VERSION 5.8 ;
BUSBITCHARS "[]" ;
DIVIDERCHAR "/" ;
UNITS
    DATABASE MICRONS 1000 ;
END UNITS

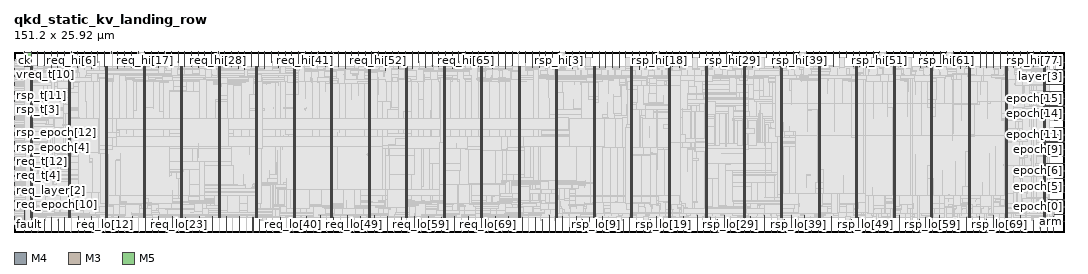
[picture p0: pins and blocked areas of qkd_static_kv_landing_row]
MACRO qkd_static_kv_landing_row
  FOREIGN qkd_static_kv_landing_row 0 0 ;
  CLASS BLOCK ;
  SIZE 151.2 BY 25.92 ;
  PIN arm
    DIRECTION INPUT ;
    USE SIGNAL ;
    PORT
      LAYER M4 ;
        RECT  151.116 1.488 151.2 1.512 ;
    END
    PORT
      LAYER M4 ;
        RECT  149.857 1.488 151.164 1.512 ;
    END
  END arm
  PIN ck
    DIRECTION INPUT ;
    USE SIGNAL ;
    PORT
      LAYER M3 ;
        RECT  1.476 25.882 1.494 25.92 ;
    END
    PORT
      LAYER M3 ;
        RECT  1.476 25.819 1.494 25.901 ;
    END
  END ck
  PIN epoch[0]
    DIRECTION INPUT ;
    USE SIGNAL ;
    PORT
      LAYER M4 ;
        RECT  151.116 2.544 151.2 2.568 ;
    END
    PORT
      LAYER M4 ;
        RECT  149.857 2.544 151.164 2.568 ;
    END
  END epoch[0]
  PIN epoch[10]
    DIRECTION INPUT ;
    USE SIGNAL ;
    PORT
      LAYER M4 ;
        RECT  151.116 12.96 151.2 12.984 ;
    END
    PORT
      LAYER M4 ;
        RECT  148.504 12.96 151.164 12.984 ;
    END
  END epoch[10]
  PIN epoch[11]
    DIRECTION INPUT ;
    USE SIGNAL ;
    PORT
      LAYER M4 ;
        RECT  151.116 13.968 151.2 13.992 ;
    END
    PORT
      LAYER M4 ;
        RECT  149.857 13.968 151.164 13.992 ;
    END
  END epoch[11]
  PIN epoch[12]
    DIRECTION INPUT ;
    USE SIGNAL ;
    PORT
      LAYER M4 ;
        RECT  151.116 15.024 151.2 15.048 ;
    END
    PORT
      LAYER M4 ;
        RECT  149.857 15.024 151.164 15.048 ;
    END
  END epoch[12]
  PIN epoch[13]
    DIRECTION INPUT ;
    USE SIGNAL ;
    PORT
      LAYER M4 ;
        RECT  151.116 16.08 151.2 16.104 ;
    END
    PORT
      LAYER M4 ;
        RECT  149.857 16.08 151.164 16.104 ;
    END
  END epoch[13]
  PIN epoch[14]
    DIRECTION INPUT ;
    USE SIGNAL ;
    PORT
      LAYER M4 ;
        RECT  151.116 17.088 151.2 17.112 ;
    END
    PORT
      LAYER M4 ;
        RECT  149.857 17.088 151.164 17.112 ;
    END
  END epoch[14]
  PIN epoch[15]
    DIRECTION INPUT ;
    USE SIGNAL ;
    PORT
      LAYER M4 ;
        RECT  151.116 18.144 151.2 18.168 ;
    END
    PORT
      LAYER M4 ;
        RECT  148.504 18.144 151.164 18.168 ;
    END
  END epoch[15]
  PIN epoch[1]
    DIRECTION INPUT ;
    USE SIGNAL ;
    PORT
      LAYER M4 ;
        RECT  151.116 3.6 151.2 3.624 ;
    END
    PORT
      LAYER M4 ;
        RECT  149.533 3.6 151.164 3.624 ;
    END
  END epoch[1]
  PIN epoch[2]
    DIRECTION INPUT ;
    USE SIGNAL ;
    PORT
      LAYER M4 ;
        RECT  151.116 4.608 151.2 4.632 ;
    END
    PORT
      LAYER M4 ;
        RECT  148.925 4.608 151.164 4.632 ;
    END
  END epoch[2]
  PIN epoch[3]
    DIRECTION INPUT ;
    USE SIGNAL ;
    PORT
      LAYER M4 ;
        RECT  151.116 5.664 151.2 5.688 ;
    END
    PORT
      LAYER M4 ;
        RECT  149.497 5.664 151.164 5.688 ;
    END
  END epoch[3]
  PIN epoch[4]
    DIRECTION INPUT ;
    USE SIGNAL ;
    PORT
      LAYER M4 ;
        RECT  151.116 6.72 151.2 6.744 ;
    END
    PORT
      LAYER M4 ;
        RECT  148.817 6.72 151.164 6.744 ;
    END
  END epoch[4]
  PIN epoch[5]
    DIRECTION INPUT ;
    USE SIGNAL ;
    PORT
      LAYER M4 ;
        RECT  151.116 7.728 151.2 7.752 ;
    END
    PORT
      LAYER M4 ;
        RECT  149.857 7.728 151.164 7.752 ;
    END
  END epoch[5]
  PIN epoch[6]
    DIRECTION INPUT ;
    USE SIGNAL ;
    PORT
      LAYER M4 ;
        RECT  151.116 8.784 151.2 8.808 ;
    END
    PORT
      LAYER M4 ;
        RECT  149.857 8.784 151.164 8.808 ;
    END
  END epoch[6]
  PIN epoch[7]
    DIRECTION INPUT ;
    USE SIGNAL ;
    PORT
      LAYER M4 ;
        RECT  151.116 9.84 151.2 9.864 ;
    END
    PORT
      LAYER M4 ;
        RECT  148.504 9.84 151.164 9.864 ;
    END
  END epoch[7]
  PIN epoch[8]
    DIRECTION INPUT ;
    USE SIGNAL ;
    PORT
      LAYER M4 ;
        RECT  151.116 10.848 151.2 10.872 ;
    END
    PORT
      LAYER M4 ;
        RECT  148.504 10.848 151.164 10.872 ;
    END
  END epoch[8]
  PIN epoch[9]
    DIRECTION INPUT ;
    USE SIGNAL ;
    PORT
      LAYER M4 ;
        RECT  151.116 11.904 151.2 11.928 ;
    END
    PORT
      LAYER M4 ;
        RECT  149.857 11.904 151.164 11.928 ;
    END
  END epoch[9]
  PIN fault
    DIRECTION OUTPUT ;
    USE SIGNAL ;
    PORT
      LAYER M4 ;
        RECT  0 1.104 0.084 1.128 ;
    END
  END fault
  PIN layer[0]
    DIRECTION INPUT ;
    USE SIGNAL ;
    PORT
      LAYER M4 ;
        RECT  151.116 19.2 151.2 19.224 ;
    END
    PORT
      LAYER M4 ;
        RECT  148.504 19.2 151.164 19.224 ;
    END
  END layer[0]
  PIN layer[1]
    DIRECTION INPUT ;
    USE SIGNAL ;
    PORT
      LAYER M4 ;
        RECT  151.116 20.208 151.2 20.232 ;
    END
    PORT
      LAYER M4 ;
        RECT  148.504 20.208 151.164 20.232 ;
    END
  END layer[1]
  PIN layer[2]
    DIRECTION INPUT ;
    USE SIGNAL ;
    PORT
      LAYER M4 ;
        RECT  151.116 21.264 151.2 21.288 ;
    END
    PORT
      LAYER M4 ;
        RECT  148.504 21.264 151.164 21.288 ;
    END
  END layer[2]
  PIN layer[3]
    DIRECTION INPUT ;
    USE SIGNAL ;
    PORT
      LAYER M4 ;
        RECT  151.116 22.32 151.2 22.344 ;
    END
    PORT
      LAYER M4 ;
        RECT  149.893 22.32 151.164 22.344 ;
    END
  END layer[3]
  PIN layer[4]
    DIRECTION INPUT ;
    USE SIGNAL ;
    PORT
      LAYER M4 ;
        RECT  151.116 23.328 151.2 23.352 ;
    END
    PORT
      LAYER M4 ;
        RECT  149.857 23.328 151.164 23.352 ;
    END
  END layer[4]
  PIN layer[5]
    DIRECTION INPUT ;
    USE SIGNAL ;
    PORT
      LAYER M4 ;
        RECT  151.116 24.384 151.2 24.408 ;
    END
    PORT
      LAYER M4 ;
        RECT  149.893 24.384 151.164 24.408 ;
    END
  END layer[5]
  PIN req_epoch[0]
    DIRECTION INPUT ;
    USE SIGNAL ;
    PORT
      LAYER M4 ;
        RECT  0 1.392 0.084 1.416 ;
    END
  END req_epoch[0]
  PIN req_epoch[10]
    DIRECTION INPUT ;
    USE SIGNAL ;
    PORT
      LAYER M4 ;
        RECT  0 3.936 0.084 3.96 ;
    END
  END req_epoch[10]
  PIN req_epoch[11]
    DIRECTION INPUT ;
    USE SIGNAL ;
    PORT
      LAYER M4 ;
        RECT  0 4.224 0.084 4.248 ;
    END
  END req_epoch[11]
  PIN req_epoch[12]
    DIRECTION INPUT ;
    USE SIGNAL ;
    PORT
      LAYER M4 ;
        RECT  0 4.464 0.084 4.488 ;
    END
  END req_epoch[12]
  PIN req_epoch[13]
    DIRECTION INPUT ;
    USE SIGNAL ;
    PORT
      LAYER M4 ;
        RECT  0 4.704 0.084 4.728 ;
    END
  END req_epoch[13]
  PIN req_epoch[14]
    DIRECTION INPUT ;
    USE SIGNAL ;
    PORT
      LAYER M4 ;
        RECT  0 4.992 0.084 5.016 ;
    END
  END req_epoch[14]
  PIN req_epoch[15]
    DIRECTION INPUT ;
    USE SIGNAL ;
    PORT
      LAYER M4 ;
        RECT  0 5.232 0.084 5.256 ;
    END
  END req_epoch[15]
  PIN req_epoch[1]
    DIRECTION INPUT ;
    USE SIGNAL ;
    PORT
      LAYER M4 ;
        RECT  0 1.632 0.084 1.656 ;
    END
  END req_epoch[1]
  PIN req_epoch[2]
    DIRECTION INPUT ;
    USE SIGNAL ;
    PORT
      LAYER M4 ;
        RECT  0 1.872 0.084 1.896 ;
    END
  END req_epoch[2]
  PIN req_epoch[3]
    DIRECTION INPUT ;
    USE SIGNAL ;
    PORT
      LAYER M4 ;
        RECT  0 2.16 0.084 2.184 ;
    END
  END req_epoch[3]
  PIN req_epoch[4]
    DIRECTION INPUT ;
    USE SIGNAL ;
    PORT
      LAYER M4 ;
        RECT  0 2.4 0.084 2.424 ;
    END
  END req_epoch[4]
  PIN req_epoch[5]
    DIRECTION INPUT ;
    USE SIGNAL ;
    PORT
      LAYER M4 ;
        RECT  0 2.64 0.084 2.664 ;
    END
  END req_epoch[5]
  PIN req_epoch[6]
    DIRECTION INPUT ;
    USE SIGNAL ;
    PORT
      LAYER M4 ;
        RECT  0 2.928 0.084 2.952 ;
    END
  END req_epoch[6]
  PIN req_epoch[7]
    DIRECTION INPUT ;
    USE SIGNAL ;
    PORT
      LAYER M4 ;
        RECT  0 3.168 0.084 3.192 ;
    END
  END req_epoch[7]
  PIN req_epoch[8]
    DIRECTION INPUT ;
    USE SIGNAL ;
    PORT
      LAYER M4 ;
        RECT  0 3.408 0.084 3.432 ;
    END
  END req_epoch[8]
  PIN req_epoch[9]
    DIRECTION INPUT ;
    USE SIGNAL ;
    PORT
      LAYER M4 ;
        RECT  0 3.696 0.084 3.72 ;
    END
  END req_epoch[9]
  PIN req_hi[0]
    DIRECTION OUTPUT ;
    USE SIGNAL ;
    PORT
      LAYER M5 ;
        RECT  2.448 25.836 2.472 25.92 ;
    END
    PORT
      LAYER M5 ;
        RECT  1.488 23.783 2.472 25.859 ;
    END
    PORT
      LAYER M5 ;
        RECT  2.448 25.859 2.472 25.872 ;
    END
  END req_hi[0]
  PIN req_hi[10]
    DIRECTION OUTPUT ;
    USE SIGNAL ;
    PORT
      LAYER M5 ;
        RECT  12.048 25.836 12.072 25.92 ;
    END
    PORT
      LAYER M5 ;
        RECT  12.048 24.469 12.072 25.872 ;
    END
  END req_hi[10]
  PIN req_hi[11]
    DIRECTION OUTPUT ;
    USE SIGNAL ;
    PORT
      LAYER M3 ;
        RECT  13.032 25.882 13.05 25.92 ;
    END
    PORT
      LAYER M3 ;
        RECT  13.032 23.777 13.05 25.901 ;
    END
  END req_hi[11]
  PIN req_hi[12]
    DIRECTION OUTPUT ;
    USE SIGNAL ;
    PORT
      LAYER M5 ;
        RECT  13.968 25.836 13.992 25.92 ;
    END
    PORT
      LAYER M5 ;
        RECT  13.968 25.765 13.992 25.872 ;
    END
  END req_hi[12]
  PIN req_hi[13]
    DIRECTION OUTPUT ;
    USE SIGNAL ;
    PORT
      LAYER M3 ;
        RECT  14.94 25.882 14.958 25.92 ;
    END
    PORT
      LAYER M3 ;
        RECT  14.94 23.585 14.958 25.901 ;
    END
  END req_hi[13]
  PIN req_hi[14]
    DIRECTION OUTPUT ;
    USE SIGNAL ;
    PORT
      LAYER M5 ;
        RECT  15.888 25.836 15.912 25.92 ;
    END
    PORT
      LAYER M5 ;
        RECT  15.888 23.893 15.912 25.872 ;
    END
  END req_hi[14]
  PIN req_hi[15]
    DIRECTION OUTPUT ;
    USE SIGNAL ;
    PORT
      LAYER M3 ;
        RECT  16.884 25.882 16.902 25.92 ;
    END
    PORT
      LAYER M3 ;
        RECT  16.884 23.729 16.902 25.901 ;
    END
  END req_hi[15]
  PIN req_hi[16]
    DIRECTION OUTPUT ;
    USE SIGNAL ;
    PORT
      LAYER M5 ;
        RECT  17.856 25.836 17.88 25.92 ;
    END
    PORT
      LAYER M5 ;
        RECT  17.856 25.765 17.88 25.872 ;
    END
  END req_hi[16]
  PIN req_hi[17]
    DIRECTION OUTPUT ;
    USE SIGNAL ;
    PORT
      LAYER M3 ;
        RECT  18.792 25.882 18.81 25.92 ;
    END
    PORT
      LAYER M3 ;
        RECT  18.792 25.805 18.81 25.901 ;
    END
  END req_hi[17]
  PIN req_hi[18]
    DIRECTION OUTPUT ;
    USE SIGNAL ;
    PORT
      LAYER M5 ;
        RECT  19.776 25.836 19.8 25.92 ;
    END
    PORT
      LAYER M5 ;
        RECT  19.776 23.893 19.8 25.872 ;
    END
  END req_hi[18]
  PIN req_hi[19]
    DIRECTION OUTPUT ;
    USE SIGNAL ;
    PORT
      LAYER M3 ;
        RECT  20.736 25.882 20.754 25.92 ;
    END
    PORT
      LAYER M3 ;
        RECT  20.736 23.729 20.754 25.901 ;
    END
  END req_hi[19]
  PIN req_hi[1]
    DIRECTION OUTPUT ;
    USE SIGNAL ;
    PORT
      LAYER M3 ;
        RECT  3.384 25.882 3.402 25.92 ;
    END
    PORT
      LAYER M3 ;
        RECT  3.384 23.933 3.402 25.901 ;
    END
  END req_hi[1]
  PIN req_hi[20]
    DIRECTION OUTPUT ;
    USE SIGNAL ;
    PORT
      LAYER M5 ;
        RECT  21.696 25.836 21.72 25.92 ;
    END
    PORT
      LAYER M5 ;
        RECT  21.696 25.765 21.72 25.872 ;
    END
  END req_hi[20]
  PIN req_hi[21]
    DIRECTION OUTPUT ;
    USE SIGNAL ;
    PORT
      LAYER M3 ;
        RECT  22.644 25.882 22.662 25.92 ;
    END
    PORT
      LAYER M3 ;
        RECT  22.644 25.861 22.734 25.889 ;
    END
    PORT
      LAYER M3 ;
        RECT  22.644 25.889 22.662 25.901 ;
    END
  END req_hi[21]
  PIN req_hi[22]
    DIRECTION OUTPUT ;
    USE SIGNAL ;
    PORT
      LAYER M5 ;
        RECT  23.616 25.836 23.64 25.92 ;
    END
    PORT
      LAYER M5 ;
        RECT  23.616 24.469 23.64 25.872 ;
    END
  END req_hi[22]
  PIN req_hi[23]
    DIRECTION OUTPUT ;
    USE SIGNAL ;
    PORT
      LAYER M3 ;
        RECT  24.588 25.882 24.606 25.92 ;
    END
    PORT
      LAYER M3 ;
        RECT  24.588 23.777 24.606 25.901 ;
    END
  END req_hi[23]
  PIN req_hi[24]
    DIRECTION OUTPUT ;
    USE SIGNAL ;
    PORT
      LAYER M5 ;
        RECT  25.536 25.836 25.56 25.92 ;
    END
    PORT
      LAYER M5 ;
        RECT  25.536 23.893 25.56 25.872 ;
    END
  END req_hi[24]
  PIN req_hi[25]
    DIRECTION OUTPUT ;
    USE SIGNAL ;
    PORT
      LAYER M3 ;
        RECT  26.496 25.882 26.514 25.92 ;
    END
    PORT
      LAYER M3 ;
        RECT  26.496 23.621 26.514 25.901 ;
    END
  END req_hi[25]
  PIN req_hi[26]
    DIRECTION OUTPUT ;
    USE SIGNAL ;
    PORT
      LAYER M5 ;
        RECT  27.456 25.836 27.48 25.92 ;
    END
    PORT
      LAYER M5 ;
        RECT  27.456 23.893 27.48 25.872 ;
    END
  END req_hi[26]
  PIN req_hi[27]
    DIRECTION OUTPUT ;
    USE SIGNAL ;
    PORT
      LAYER M3 ;
        RECT  28.44 25.882 28.458 25.92 ;
    END
    PORT
      LAYER M3 ;
        RECT  28.44 23.729 28.458 25.901 ;
    END
  END req_hi[27]
  PIN req_hi[28]
    DIRECTION OUTPUT ;
    USE SIGNAL ;
    PORT
      LAYER M5 ;
        RECT  29.376 25.836 29.4 25.92 ;
    END
    PORT
      LAYER M5 ;
        RECT  29.376 25.765 29.4 25.872 ;
    END
  END req_hi[28]
  PIN req_hi[29]
    DIRECTION OUTPUT ;
    USE SIGNAL ;
    PORT
      LAYER M3 ;
        RECT  30.348 25.882 30.366 25.92 ;
    END
    PORT
      LAYER M3 ;
        RECT  30.348 23.621 30.366 25.901 ;
    END
  END req_hi[29]
  PIN req_hi[2]
    DIRECTION OUTPUT ;
    USE SIGNAL ;
    PORT
      LAYER M5 ;
        RECT  4.368 25.836 4.392 25.92 ;
    END
    PORT
      LAYER M5 ;
        RECT  4.368 23.941 4.392 25.872 ;
    END
  END req_hi[2]
  PIN req_hi[30]
    DIRECTION OUTPUT ;
    USE SIGNAL ;
    PORT
      LAYER M5 ;
        RECT  31.296 25.836 31.32 25.92 ;
    END
    PORT
      LAYER M5 ;
        RECT  31.296 23.893 31.32 25.872 ;
    END
  END req_hi[30]
  PIN req_hi[31]
    DIRECTION OUTPUT ;
    USE SIGNAL ;
    PORT
      LAYER M3 ;
        RECT  32.292 25.882 32.31 25.92 ;
    END
    PORT
      LAYER M3 ;
        RECT  32.292 23.549 32.31 25.901 ;
    END
  END req_hi[31]
  PIN req_hi[32]
    DIRECTION OUTPUT ;
    USE SIGNAL ;
    PORT
      LAYER M5 ;
        RECT  33.216 25.836 33.24 25.92 ;
    END
    PORT
      LAYER M5 ;
        RECT  33.216 23.365 33.24 25.872 ;
    END
  END req_hi[32]
  PIN req_hi[33]
    DIRECTION OUTPUT ;
    USE SIGNAL ;
    PORT
      LAYER M3 ;
        RECT  34.2 25.882 34.218 25.92 ;
    END
    PORT
      LAYER M3 ;
        RECT  34.2 23.777 34.218 25.901 ;
    END
  END req_hi[33]
  PIN req_hi[34]
    DIRECTION OUTPUT ;
    USE SIGNAL ;
    PORT
      LAYER M5 ;
        RECT  35.184 25.836 35.208 25.92 ;
    END
    PORT
      LAYER M5 ;
        RECT  35.184 23.893 35.208 25.872 ;
    END
  END req_hi[34]
  PIN req_hi[35]
    DIRECTION OUTPUT ;
    USE SIGNAL ;
    PORT
      LAYER M3 ;
        RECT  36.108 25.882 36.126 25.92 ;
    END
    PORT
      LAYER M3 ;
        RECT  36.108 23.549 36.126 25.901 ;
    END
  END req_hi[35]
  PIN req_hi[36]
    DIRECTION OUTPUT ;
    USE SIGNAL ;
    PORT
      LAYER M5 ;
        RECT  37.104 25.836 37.128 25.92 ;
    END
    PORT
      LAYER M5 ;
        RECT  37.104 24.469 37.128 25.872 ;
    END
  END req_hi[36]
  PIN req_hi[37]
    DIRECTION OUTPUT ;
    USE SIGNAL ;
    PORT
      LAYER M3 ;
        RECT  38.052 25.882 38.07 25.92 ;
    END
    PORT
      LAYER M3 ;
        RECT  38.052 23.693 38.07 25.901 ;
    END
  END req_hi[37]
  PIN req_hi[38]
    DIRECTION OUTPUT ;
    USE SIGNAL ;
    PORT
      LAYER M5 ;
        RECT  39.024 25.836 39.048 25.92 ;
    END
    PORT
      LAYER M5 ;
        RECT  39.024 24.469 39.048 25.872 ;
    END
  END req_hi[38]
  PIN req_hi[39]
    DIRECTION OUTPUT ;
    USE SIGNAL ;
    PORT
      LAYER M3 ;
        RECT  39.96 25.882 39.978 25.92 ;
    END
    PORT
      LAYER M3 ;
        RECT  39.96 23.777 39.978 25.901 ;
    END
  END req_hi[39]
  PIN req_hi[3]
    DIRECTION OUTPUT ;
    USE SIGNAL ;
    PORT
      LAYER M3 ;
        RECT  5.328 25.882 5.346 25.92 ;
    END
    PORT
      LAYER M3 ;
        RECT  5.328 23.729 5.346 25.901 ;
    END
  END req_hi[3]
  PIN req_hi[40]
    DIRECTION OUTPUT ;
    USE SIGNAL ;
    PORT
      LAYER M5 ;
        RECT  40.944 25.836 40.968 25.92 ;
    END
    PORT
      LAYER M5 ;
        RECT  40.944 23.893 40.968 25.872 ;
    END
  END req_hi[40]
  PIN req_hi[41]
    DIRECTION OUTPUT ;
    USE SIGNAL ;
    PORT
      LAYER M3 ;
        RECT  41.904 25.882 41.922 25.92 ;
    END
    PORT
      LAYER M3 ;
        RECT  41.832 25.861 41.922 25.889 ;
    END
    PORT
      LAYER M3 ;
        RECT  41.904 25.889 41.922 25.901 ;
    END
  END req_hi[41]
  PIN req_hi[42]
    DIRECTION OUTPUT ;
    USE SIGNAL ;
    PORT
      LAYER M5 ;
        RECT  42.864 25.836 42.888 25.92 ;
    END
    PORT
      LAYER M5 ;
        RECT  42.864 24.469 42.888 25.872 ;
    END
  END req_hi[42]
  PIN req_hi[43]
    DIRECTION OUTPUT ;
    USE SIGNAL ;
    PORT
      LAYER M3 ;
        RECT  43.812 25.882 43.83 25.92 ;
    END
    PORT
      LAYER M3 ;
        RECT  43.74 25.861 43.83 25.889 ;
    END
    PORT
      LAYER M3 ;
        RECT  43.812 25.889 43.83 25.901 ;
    END
  END req_hi[43]
  PIN req_hi[44]
    DIRECTION OUTPUT ;
    USE SIGNAL ;
    PORT
      LAYER M5 ;
        RECT  44.784 25.836 44.808 25.92 ;
    END
    PORT
      LAYER M5 ;
        RECT  44.784 23.893 44.808 25.872 ;
    END
  END req_hi[44]
  PIN req_hi[45]
    DIRECTION OUTPUT ;
    USE SIGNAL ;
    PORT
      LAYER M3 ;
        RECT  45.756 25.882 45.774 25.92 ;
    END
    PORT
      LAYER M3 ;
        RECT  45.756 25.861 45.954 25.889 ;
    END
    PORT
      LAYER M3 ;
        RECT  45.756 25.889 45.774 25.901 ;
    END
  END req_hi[45]
  PIN req_hi[46]
    DIRECTION OUTPUT ;
    USE SIGNAL ;
    PORT
      LAYER M5 ;
        RECT  46.704 25.836 46.728 25.92 ;
    END
    PORT
      LAYER M5 ;
        RECT  46.704 23.769 46.728 25.872 ;
    END
  END req_hi[46]
  PIN req_hi[47]
    DIRECTION OUTPUT ;
    USE SIGNAL ;
    PORT
      LAYER M3 ;
        RECT  47.664 25.882 47.682 25.92 ;
    END
    PORT
      LAYER M3 ;
        RECT  47.664 23.585 47.682 25.901 ;
    END
  END req_hi[47]
  PIN req_hi[48]
    DIRECTION OUTPUT ;
    USE SIGNAL ;
    PORT
      LAYER M5 ;
        RECT  48.624 25.836 48.648 25.92 ;
    END
    PORT
      LAYER M5 ;
        RECT  48.624 24.469 48.648 25.872 ;
    END
  END req_hi[48]
  PIN req_hi[49]
    DIRECTION OUTPUT ;
    USE SIGNAL ;
    PORT
      LAYER M3 ;
        RECT  49.608 25.882 49.626 25.92 ;
    END
    PORT
      LAYER M3 ;
        RECT  49.608 24.509 49.626 25.901 ;
    END
  END req_hi[49]
  PIN req_hi[4]
    DIRECTION OUTPUT ;
    USE SIGNAL ;
    PORT
      LAYER M5 ;
        RECT  6.288 25.836 6.312 25.92 ;
    END
    PORT
      LAYER M5 ;
        RECT  6.288 23.701 6.312 25.872 ;
    END
  END req_hi[4]
  PIN req_hi[50]
    DIRECTION OUTPUT ;
    USE SIGNAL ;
    PORT
      LAYER M5 ;
        RECT  50.544 25.836 50.568 25.92 ;
    END
    PORT
      LAYER M5 ;
        RECT  50.544 23.783 50.568 25.872 ;
    END
  END req_hi[50]
  PIN req_hi[51]
    DIRECTION OUTPUT ;
    USE SIGNAL ;
    PORT
      LAYER M3 ;
        RECT  51.516 25.882 51.534 25.92 ;
    END
    PORT
      LAYER M3 ;
        RECT  51.516 23.777 51.534 25.901 ;
    END
  END req_hi[51]
  PIN req_hi[52]
    DIRECTION OUTPUT ;
    USE SIGNAL ;
    PORT
      LAYER M5 ;
        RECT  52.464 25.836 52.488 25.92 ;
    END
    PORT
      LAYER M5 ;
        RECT  52.464 24.469 52.488 25.872 ;
    END
  END req_hi[52]
  PIN req_hi[53]
    DIRECTION OUTPUT ;
    USE SIGNAL ;
    PORT
      LAYER M3 ;
        RECT  53.46 25.882 53.478 25.92 ;
    END
    PORT
      LAYER M3 ;
        RECT  53.46 23.279 53.478 25.901 ;
    END
  END req_hi[53]
  PIN req_hi[54]
    DIRECTION OUTPUT ;
    USE SIGNAL ;
    PORT
      LAYER M5 ;
        RECT  54.432 25.836 54.456 25.92 ;
    END
    PORT
      LAYER M5 ;
        RECT  54.432 24.469 54.456 25.872 ;
    END
  END req_hi[54]
  PIN req_hi[55]
    DIRECTION OUTPUT ;
    USE SIGNAL ;
    PORT
      LAYER M3 ;
        RECT  55.368 25.882 55.386 25.92 ;
    END
    PORT
      LAYER M3 ;
        RECT  55.368 23.585 55.386 25.901 ;
    END
  END req_hi[55]
  PIN req_hi[56]
    DIRECTION OUTPUT ;
    USE SIGNAL ;
    PORT
      LAYER M5 ;
        RECT  56.352 25.836 56.376 25.92 ;
    END
    PORT
      LAYER M5 ;
        RECT  56.352 24.469 56.376 25.872 ;
    END
  END req_hi[56]
  PIN req_hi[57]
    DIRECTION OUTPUT ;
    USE SIGNAL ;
    PORT
      LAYER M3 ;
        RECT  57.312 25.882 57.33 25.92 ;
    END
    PORT
      LAYER M3 ;
        RECT  57.312 23.507 57.33 25.901 ;
    END
  END req_hi[57]
  PIN req_hi[58]
    DIRECTION OUTPUT ;
    USE SIGNAL ;
    PORT
      LAYER M5 ;
        RECT  58.272 25.836 58.296 25.92 ;
    END
    PORT
      LAYER M5 ;
        RECT  58.272 24.469 58.296 25.872 ;
    END
  END req_hi[58]
  PIN req_hi[59]
    DIRECTION OUTPUT ;
    USE SIGNAL ;
    PORT
      LAYER M3 ;
        RECT  59.22 25.882 59.238 25.92 ;
    END
    PORT
      LAYER M3 ;
        RECT  59.22 23.621 59.238 25.901 ;
    END
  END req_hi[59]
  PIN req_hi[5]
    DIRECTION OUTPUT ;
    USE SIGNAL ;
    PORT
      LAYER M3 ;
        RECT  7.236 25.882 7.254 25.92 ;
    END
    PORT
      LAYER M3 ;
        RECT  7.236 23.777 7.254 25.901 ;
    END
  END req_hi[5]
  PIN req_hi[60]
    DIRECTION OUTPUT ;
    USE SIGNAL ;
    PORT
      LAYER M5 ;
        RECT  60.192 25.836 60.216 25.92 ;
    END
    PORT
      LAYER M5 ;
        RECT  60.192 23.893 60.216 25.872 ;
    END
  END req_hi[60]
  PIN req_hi[61]
    DIRECTION OUTPUT ;
    USE SIGNAL ;
    PORT
      LAYER M3 ;
        RECT  61.164 25.882 61.182 25.92 ;
    END
    PORT
      LAYER M3 ;
        RECT  61.164 23.777 61.182 25.901 ;
    END
  END req_hi[61]
  PIN req_hi[62]
    DIRECTION OUTPUT ;
    USE SIGNAL ;
    PORT
      LAYER M5 ;
        RECT  62.112 25.836 62.136 25.92 ;
    END
    PORT
      LAYER M5 ;
        RECT  62.112 23.893 62.136 25.872 ;
    END
  END req_hi[62]
  PIN req_hi[63]
    DIRECTION OUTPUT ;
    USE SIGNAL ;
    PORT
      LAYER M3 ;
        RECT  63.072 25.882 63.09 25.92 ;
    END
    PORT
      LAYER M3 ;
        RECT  63.072 23.549 63.09 25.901 ;
    END
  END req_hi[63]
  PIN req_hi[64]
    DIRECTION OUTPUT ;
    USE SIGNAL ;
    PORT
      LAYER M5 ;
        RECT  64.032 25.836 64.056 25.92 ;
    END
    PORT
      LAYER M5 ;
        RECT  64.032 24.469 64.056 25.872 ;
    END
  END req_hi[64]
  PIN req_hi[65]
    DIRECTION OUTPUT ;
    USE SIGNAL ;
    PORT
      LAYER M3 ;
        RECT  65.016 25.882 65.034 25.92 ;
    END
    PORT
      LAYER M3 ;
        RECT  65.016 24.509 65.034 25.901 ;
    END
  END req_hi[65]
  PIN req_hi[66]
    DIRECTION OUTPUT ;
    USE SIGNAL ;
    PORT
      LAYER M5 ;
        RECT  65.952 25.836 65.976 25.92 ;
    END
    PORT
      LAYER M5 ;
        RECT  65.952 24.469 65.976 25.872 ;
    END
  END req_hi[66]
  PIN req_hi[67]
    DIRECTION OUTPUT ;
    USE SIGNAL ;
    PORT
      LAYER M3 ;
        RECT  66.924 25.882 66.942 25.92 ;
    END
    PORT
      LAYER M3 ;
        RECT  66.924 23.777 66.942 25.901 ;
    END
  END req_hi[67]
  PIN req_hi[68]
    DIRECTION OUTPUT ;
    USE SIGNAL ;
    PORT
      LAYER M5 ;
        RECT  67.872 25.836 67.896 25.92 ;
    END
    PORT
      LAYER M5 ;
        RECT  67.872 24.469 67.896 25.872 ;
    END
  END req_hi[68]
  PIN req_hi[69]
    DIRECTION OUTPUT ;
    USE SIGNAL ;
    PORT
      LAYER M3 ;
        RECT  68.868 25.882 68.886 25.92 ;
    END
    PORT
      LAYER M3 ;
        RECT  68.868 23.585 68.886 25.901 ;
    END
  END req_hi[69]
  PIN req_hi[6]
    DIRECTION OUTPUT ;
    USE SIGNAL ;
    PORT
      LAYER M5 ;
        RECT  8.208 25.836 8.232 25.92 ;
    END
    PORT
      LAYER M5 ;
        RECT  8.208 25.765 8.232 25.872 ;
    END
  END req_hi[6]
  PIN req_hi[70]
    DIRECTION OUTPUT ;
    USE SIGNAL ;
    PORT
      LAYER M5 ;
        RECT  69.792 25.836 69.816 25.92 ;
    END
    PORT
      LAYER M5 ;
        RECT  69.792 23.941 69.816 25.872 ;
    END
  END req_hi[70]
  PIN req_hi[71]
    DIRECTION OUTPUT ;
    USE SIGNAL ;
    PORT
      LAYER M3 ;
        RECT  70.776 25.882 70.794 25.92 ;
    END
    PORT
      LAYER M3 ;
        RECT  70.776 23.549 70.794 25.901 ;
    END
  END req_hi[71]
  PIN req_hi[72]
    DIRECTION OUTPUT ;
    USE SIGNAL ;
    PORT
      LAYER M5 ;
        RECT  71.76 25.836 71.784 25.92 ;
    END
    PORT
      LAYER M5 ;
        RECT  71.76 23.941 71.784 25.872 ;
    END
  END req_hi[72]
  PIN req_hi[73]
    DIRECTION OUTPUT ;
    USE SIGNAL ;
    PORT
      LAYER M3 ;
        RECT  72.72 25.882 72.738 25.92 ;
    END
    PORT
      LAYER M3 ;
        RECT  72.576 25.861 72.738 25.889 ;
    END
    PORT
      LAYER M3 ;
        RECT  72.72 25.889 72.738 25.901 ;
    END
  END req_hi[73]
  PIN req_hi[74]
    DIRECTION OUTPUT ;
    USE SIGNAL ;
    PORT
      LAYER M5 ;
        RECT  73.68 25.836 73.704 25.92 ;
    END
    PORT
      LAYER M5 ;
        RECT  73.68 24.469 73.704 25.872 ;
    END
  END req_hi[74]
  PIN req_hi[75]
    DIRECTION OUTPUT ;
    USE SIGNAL ;
    PORT
      LAYER M3 ;
        RECT  74.628 25.882 74.646 25.92 ;
    END
    PORT
      LAYER M3 ;
        RECT  74.628 23.741 74.646 25.901 ;
    END
  END req_hi[75]
  PIN req_hi[7]
    DIRECTION OUTPUT ;
    USE SIGNAL ;
    PORT
      LAYER M3 ;
        RECT  9.18 25.882 9.198 25.92 ;
    END
    PORT
      LAYER M3 ;
        RECT  9.18 23.657 9.198 25.901 ;
    END
  END req_hi[7]
  PIN req_hi[8]
    DIRECTION OUTPUT ;
    USE SIGNAL ;
    PORT
      LAYER M5 ;
        RECT  10.128 25.836 10.152 25.92 ;
    END
    PORT
      LAYER M5 ;
        RECT  10.128 24.469 10.152 25.872 ;
    END
  END req_hi[8]
  PIN req_hi[9]
    DIRECTION OUTPUT ;
    USE SIGNAL ;
    PORT
      LAYER M3 ;
        RECT  11.088 25.882 11.106 25.92 ;
    END
    PORT
      LAYER M3 ;
        RECT  11.088 23.549 11.106 25.901 ;
    END
  END req_hi[9]
  PIN req_layer[0]
    DIRECTION INPUT ;
    USE SIGNAL ;
    PORT
      LAYER M4 ;
        RECT  0 5.472 0.084 5.496 ;
    END
  END req_layer[0]
  PIN req_layer[1]
    DIRECTION INPUT ;
    USE SIGNAL ;
    PORT
      LAYER M4 ;
        RECT  0 5.76 0.084 5.784 ;
    END
  END req_layer[1]
  PIN req_layer[2]
    DIRECTION INPUT ;
    USE SIGNAL ;
    PORT
      LAYER M4 ;
        RECT  0 6 0.084 6.024 ;
    END
  END req_layer[2]
  PIN req_layer[3]
    DIRECTION INPUT ;
    USE SIGNAL ;
    PORT
      LAYER M4 ;
        RECT  0 6.24 0.084 6.264 ;
    END
  END req_layer[3]
  PIN req_layer[4]
    DIRECTION INPUT ;
    USE SIGNAL ;
    PORT
      LAYER M4 ;
        RECT  0 6.528 0.084 6.552 ;
    END
  END req_layer[4]
  PIN req_layer[5]
    DIRECTION INPUT ;
    USE SIGNAL ;
    PORT
      LAYER M4 ;
        RECT  0 6.768 0.084 6.792 ;
    END
  END req_layer[5]
  PIN req_lo[0]
    DIRECTION OUTPUT ;
    USE SIGNAL ;
    PORT
      LAYER M3 ;
        RECT  1.476 0 1.494 0.038 ;
    END
    PORT
      LAYER M3 ;
        RECT  1.476 0.012 1.494 3.299 ;
    END
  END req_lo[0]
  PIN req_lo[10]
    DIRECTION OUTPUT ;
    USE SIGNAL ;
    PORT
      LAYER M3 ;
        RECT  11.16 0 11.178 0.038 ;
    END
    PORT
      LAYER M3 ;
        RECT  11.16 0.012 11.178 2.191 ;
    END
  END req_lo[10]
  PIN req_lo[11]
    DIRECTION OUTPUT ;
    USE SIGNAL ;
    PORT
      LAYER M5 ;
        RECT  12.144 0 12.168 0.084 ;
    END
    PORT
      LAYER M5 ;
        RECT  12.144 0.016 12.168 0.131 ;
    END
  END req_lo[11]
  PIN req_lo[12]
    DIRECTION OUTPUT ;
    USE SIGNAL ;
    PORT
      LAYER M3 ;
        RECT  13.104 0 13.122 0.038 ;
    END
    PORT
      LAYER M3 ;
        RECT  13.104 0.012 13.122 0.031 ;
    END
    PORT
      LAYER M3 ;
        RECT  13.104 0.031 13.194 0.059 ;
    END
  END req_lo[12]
  PIN req_lo[13]
    DIRECTION OUTPUT ;
    USE SIGNAL ;
    PORT
      LAYER M5 ;
        RECT  14.064 0 14.088 0.084 ;
    END
    PORT
      LAYER M5 ;
        RECT  14.064 0.016 14.088 0.131 ;
    END
  END req_lo[13]
  PIN req_lo[14]
    DIRECTION OUTPUT ;
    USE SIGNAL ;
    PORT
      LAYER M3 ;
        RECT  15.048 0 15.066 0.038 ;
    END
    PORT
      LAYER M3 ;
        RECT  15.048 0.012 15.066 2.191 ;
    END
  END req_lo[14]
  PIN req_lo[15]
    DIRECTION OUTPUT ;
    USE SIGNAL ;
    PORT
      LAYER M5 ;
        RECT  15.984 0 16.008 0.084 ;
    END
    PORT
      LAYER M5 ;
        RECT  15.984 0.016 16.008 0.131 ;
    END
  END req_lo[15]
  PIN req_lo[16]
    DIRECTION OUTPUT ;
    USE SIGNAL ;
    PORT
      LAYER M3 ;
        RECT  16.992 0 17.01 0.038 ;
    END
    PORT
      LAYER M3 ;
        RECT  16.992 0.012 17.01 2.263 ;
    END
  END req_lo[16]
  PIN req_lo[17]
    DIRECTION OUTPUT ;
    USE SIGNAL ;
    PORT
      LAYER M5 ;
        RECT  17.952 0 17.976 0.084 ;
    END
    PORT
      LAYER M5 ;
        RECT  17.952 0.016 17.976 0.131 ;
    END
  END req_lo[17]
  PIN req_lo[18]
    DIRECTION OUTPUT ;
    USE SIGNAL ;
    PORT
      LAYER M3 ;
        RECT  18.9 0 18.918 0.038 ;
    END
    PORT
      LAYER M3 ;
        RECT  18.9 0.012 18.918 2.143 ;
    END
  END req_lo[18]
  PIN req_lo[19]
    DIRECTION OUTPUT ;
    USE SIGNAL ;
    PORT
      LAYER M5 ;
        RECT  19.872 0 19.896 0.084 ;
    END
    PORT
      LAYER M5 ;
        RECT  19.872 0.016 19.896 1.763 ;
    END
  END req_lo[19]
  PIN req_lo[1]
    DIRECTION OUTPUT ;
    USE SIGNAL ;
    PORT
      LAYER M5 ;
        RECT  2.448 0 2.472 0.084 ;
    END
    PORT
      LAYER M5 ;
        RECT  2.448 0.016 2.472 2.137 ;
    END
  END req_lo[1]
  PIN req_lo[20]
    DIRECTION OUTPUT ;
    USE SIGNAL ;
    PORT
      LAYER M3 ;
        RECT  20.844 0 20.862 0.038 ;
    END
    PORT
      LAYER M3 ;
        RECT  20.844 0.012 20.862 2.191 ;
    END
  END req_lo[20]
  PIN req_lo[21]
    DIRECTION OUTPUT ;
    USE SIGNAL ;
    PORT
      LAYER M5 ;
        RECT  21.84 0 21.864 0.084 ;
    END
    PORT
      LAYER M5 ;
        RECT  21.84 0.016 21.864 0.131 ;
    END
  END req_lo[21]
  PIN req_lo[22]
    DIRECTION OUTPUT ;
    USE SIGNAL ;
    PORT
      LAYER M3 ;
        RECT  22.788 0 22.806 0.038 ;
    END
    PORT
      LAYER M3 ;
        RECT  22.788 0.012 22.806 2.191 ;
    END
  END req_lo[22]
  PIN req_lo[23]
    DIRECTION OUTPUT ;
    USE SIGNAL ;
    PORT
      LAYER M5 ;
        RECT  23.76 0 23.784 0.084 ;
    END
    PORT
      LAYER M5 ;
        RECT  23.76 0.016 23.784 0.131 ;
    END
  END req_lo[23]
  PIN req_lo[24]
    DIRECTION OUTPUT ;
    USE SIGNAL ;
    PORT
      LAYER M3 ;
        RECT  24.732 0 24.75 0.038 ;
    END
    PORT
      LAYER M3 ;
        RECT  24.732 0.012 24.75 2.143 ;
    END
  END req_lo[24]
  PIN req_lo[25]
    DIRECTION OUTPUT ;
    USE SIGNAL ;
    PORT
      LAYER M5 ;
        RECT  25.68 0 25.704 0.084 ;
    END
    PORT
      LAYER M5 ;
        RECT  25.68 0.016 25.704 0.131 ;
    END
  END req_lo[25]
  PIN req_lo[26]
    DIRECTION OUTPUT ;
    USE SIGNAL ;
    PORT
      LAYER M3 ;
        RECT  26.676 0 26.694 0.038 ;
    END
    PORT
      LAYER M3 ;
        RECT  26.676 0.012 26.694 2.191 ;
    END
  END req_lo[26]
  PIN req_lo[27]
    DIRECTION OUTPUT ;
    USE SIGNAL ;
    PORT
      LAYER M5 ;
        RECT  27.648 0 27.672 0.084 ;
    END
    PORT
      LAYER M5 ;
        RECT  27.648 0.016 27.672 0.131 ;
    END
  END req_lo[27]
  PIN req_lo[28]
    DIRECTION OUTPUT ;
    USE SIGNAL ;
    PORT
      LAYER M3 ;
        RECT  28.62 0 28.638 0.038 ;
    END
    PORT
      LAYER M3 ;
        RECT  28.62 0.012 28.638 2.191 ;
    END
  END req_lo[28]
  PIN req_lo[29]
    DIRECTION OUTPUT ;
    USE SIGNAL ;
    PORT
      LAYER M5 ;
        RECT  29.568 0 29.592 0.084 ;
    END
    PORT
      LAYER M5 ;
        RECT  29.568 0.016 29.592 0.131 ;
    END
  END req_lo[29]
  PIN req_lo[2]
    DIRECTION OUTPUT ;
    USE SIGNAL ;
    PORT
      LAYER M3 ;
        RECT  3.42 0 3.438 0.038 ;
    END
    PORT
      LAYER M3 ;
        RECT  3.42 0.012 3.438 0.031 ;
    END
    PORT
      LAYER M3 ;
        RECT  3.42 0.031 3.51 0.059 ;
    END
  END req_lo[2]
  PIN req_lo[30]
    DIRECTION OUTPUT ;
    USE SIGNAL ;
    PORT
      LAYER M3 ;
        RECT  30.528 0 30.546 0.038 ;
    END
    PORT
      LAYER M3 ;
        RECT  30.528 0.012 30.546 2.191 ;
    END
  END req_lo[30]
  PIN req_lo[31]
    DIRECTION OUTPUT ;
    USE SIGNAL ;
    PORT
      LAYER M5 ;
        RECT  31.488 0 31.512 0.084 ;
    END
    PORT
      LAYER M5 ;
        RECT  31.488 0.016 31.512 0.131 ;
    END
  END req_lo[31]
  PIN req_lo[32]
    DIRECTION OUTPUT ;
    USE SIGNAL ;
    PORT
      LAYER M3 ;
        RECT  32.472 0 32.49 0.038 ;
    END
    PORT
      LAYER M3 ;
        RECT  32.472 0.012 32.49 2.191 ;
    END
  END req_lo[32]
  PIN req_lo[33]
    DIRECTION OUTPUT ;
    USE SIGNAL ;
    PORT
      LAYER M5 ;
        RECT  33.456 0 33.48 0.084 ;
    END
    PORT
      LAYER M5 ;
        RECT  33.456 0.016 33.48 0.131 ;
    END
  END req_lo[33]
  PIN req_lo[34]
    DIRECTION OUTPUT ;
    USE SIGNAL ;
    PORT
      LAYER M3 ;
        RECT  34.416 0 34.434 0.038 ;
    END
    PORT
      LAYER M3 ;
        RECT  34.416 0.012 34.434 2.101 ;
    END
  END req_lo[34]
  PIN req_lo[35]
    DIRECTION OUTPUT ;
    USE SIGNAL ;
    PORT
      LAYER M5 ;
        RECT  35.376 0 35.4 0.084 ;
    END
    PORT
      LAYER M5 ;
        RECT  35.376 0.016 35.4 1.763 ;
    END
  END req_lo[35]
  PIN req_lo[36]
    DIRECTION OUTPUT ;
    USE SIGNAL ;
    PORT
      LAYER M3 ;
        RECT  36.36 0 36.378 0.038 ;
    END
    PORT
      LAYER M3 ;
        RECT  36.36 0.012 36.378 1.723 ;
    END
  END req_lo[36]
  PIN req_lo[37]
    DIRECTION OUTPUT ;
    USE SIGNAL ;
    PORT
      LAYER M5 ;
        RECT  37.296 0 37.32 0.084 ;
    END
    PORT
      LAYER M5 ;
        RECT  37.296 0.016 37.32 0.131 ;
    END
  END req_lo[37]
  PIN req_lo[38]
    DIRECTION OUTPUT ;
    USE SIGNAL ;
    PORT
      LAYER M3 ;
        RECT  38.304 0 38.322 0.038 ;
    END
    PORT
      LAYER M3 ;
        RECT  38.304 0.012 38.322 2.101 ;
    END
  END req_lo[38]
  PIN req_lo[39]
    DIRECTION OUTPUT ;
    USE SIGNAL ;
    PORT
      LAYER M5 ;
        RECT  39.264 0 39.288 0.084 ;
    END
    PORT
      LAYER M5 ;
        RECT  39.264 0.016 39.288 0.131 ;
    END
  END req_lo[39]
  PIN req_lo[3]
    DIRECTION OUTPUT ;
    USE SIGNAL ;
    PORT
      LAYER M5 ;
        RECT  4.368 0 4.392 0.084 ;
    END
    PORT
      LAYER M5 ;
        RECT  4.368 0.016 4.392 1.763 ;
    END
  END req_lo[3]
  PIN req_lo[40]
    DIRECTION OUTPUT ;
    USE SIGNAL ;
    PORT
      LAYER M3 ;
        RECT  40.212 0 40.23 0.038 ;
    END
    PORT
      LAYER M3 ;
        RECT  40.212 0.012 40.23 0.031 ;
    END
    PORT
      LAYER M3 ;
        RECT  40.14 0.031 40.23 0.059 ;
    END
  END req_lo[40]
  PIN req_lo[41]
    DIRECTION OUTPUT ;
    USE SIGNAL ;
    PORT
      LAYER M5 ;
        RECT  41.184 0 41.208 0.084 ;
    END
    PORT
      LAYER M5 ;
        RECT  41.184 0.016 41.208 0.131 ;
    END
  END req_lo[41]
  PIN req_lo[42]
    DIRECTION OUTPUT ;
    USE SIGNAL ;
    PORT
      LAYER M3 ;
        RECT  42.156 0 42.174 0.038 ;
    END
    PORT
      LAYER M3 ;
        RECT  42.156 0.012 42.174 2.191 ;
    END
  END req_lo[42]
  PIN req_lo[43]
    DIRECTION OUTPUT ;
    USE SIGNAL ;
    PORT
      LAYER M5 ;
        RECT  43.152 0 43.176 0.084 ;
    END
    PORT
      LAYER M5 ;
        RECT  43.152 0.016 43.176 0.131 ;
    END
  END req_lo[43]
  PIN req_lo[44]
    DIRECTION OUTPUT ;
    USE SIGNAL ;
    PORT
      LAYER M3 ;
        RECT  44.1 0 44.118 0.038 ;
    END
    PORT
      LAYER M3 ;
        RECT  44.1 0.012 44.118 2.335 ;
    END
  END req_lo[44]
  PIN req_lo[45]
    DIRECTION OUTPUT ;
    USE SIGNAL ;
    PORT
      LAYER M5 ;
        RECT  45.072 0 45.096 0.084 ;
    END
    PORT
      LAYER M5 ;
        RECT  45.072 0.016 45.096 0.131 ;
    END
  END req_lo[45]
  PIN req_lo[46]
    DIRECTION OUTPUT ;
    USE SIGNAL ;
    PORT
      LAYER M3 ;
        RECT  46.044 0 46.062 0.038 ;
    END
    PORT
      LAYER M3 ;
        RECT  46.044 0.012 46.062 2.143 ;
    END
  END req_lo[46]
  PIN req_lo[47]
    DIRECTION OUTPUT ;
    USE SIGNAL ;
    PORT
      LAYER M5 ;
        RECT  46.992 0 47.016 0.084 ;
    END
    PORT
      LAYER M5 ;
        RECT  46.992 0.016 47.016 0.131 ;
    END
  END req_lo[47]
  PIN req_lo[48]
    DIRECTION OUTPUT ;
    USE SIGNAL ;
    PORT
      LAYER M3 ;
        RECT  47.988 0 48.006 0.038 ;
    END
    PORT
      LAYER M3 ;
        RECT  47.988 0.012 48.006 2.335 ;
    END
  END req_lo[48]
  PIN req_lo[49]
    DIRECTION OUTPUT ;
    USE SIGNAL ;
    PORT
      LAYER M5 ;
        RECT  48.96 0 48.984 0.084 ;
    END
    PORT
      LAYER M5 ;
        RECT  48.96 0.016 48.984 0.131 ;
    END
  END req_lo[49]
  PIN req_lo[4]
    DIRECTION OUTPUT ;
    USE SIGNAL ;
    PORT
      LAYER M3 ;
        RECT  5.364 0 5.382 0.038 ;
    END
    PORT
      LAYER M3 ;
        RECT  5.364 0.012 5.382 2.101 ;
    END
  END req_lo[4]
  PIN req_lo[50]
    DIRECTION OUTPUT ;
    USE SIGNAL ;
    PORT
      LAYER M3 ;
        RECT  49.932 0 49.95 0.038 ;
    END
    PORT
      LAYER M3 ;
        RECT  49.932 0.012 49.95 2.191 ;
    END
  END req_lo[50]
  PIN req_lo[51]
    DIRECTION OUTPUT ;
    USE SIGNAL ;
    PORT
      LAYER M5 ;
        RECT  50.88 0 50.904 0.084 ;
    END
    PORT
      LAYER M5 ;
        RECT  50.88 0.016 50.904 0.131 ;
    END
  END req_lo[51]
  PIN req_lo[52]
    DIRECTION OUTPUT ;
    USE SIGNAL ;
    PORT
      LAYER M3 ;
        RECT  51.84 0 51.858 0.038 ;
    END
    PORT
      LAYER M3 ;
        RECT  51.84 0.012 51.858 2.371 ;
    END
  END req_lo[52]
  PIN req_lo[53]
    DIRECTION OUTPUT ;
    USE SIGNAL ;
    PORT
      LAYER M5 ;
        RECT  52.8 0 52.824 0.084 ;
    END
    PORT
      LAYER M5 ;
        RECT  52.8 0.016 52.824 0.131 ;
    END
  END req_lo[53]
  PIN req_lo[54]
    DIRECTION OUTPUT ;
    USE SIGNAL ;
    PORT
      LAYER M3 ;
        RECT  53.784 0 53.802 0.038 ;
    END
    PORT
      LAYER M3 ;
        RECT  53.784 0.012 53.802 2.191 ;
    END
  END req_lo[54]
  PIN req_lo[55]
    DIRECTION OUTPUT ;
    USE SIGNAL ;
    PORT
      LAYER M5 ;
        RECT  54.768 0 54.792 0.084 ;
    END
    PORT
      LAYER M5 ;
        RECT  54.768 0.016 54.792 0.131 ;
    END
  END req_lo[55]
  PIN req_lo[56]
    DIRECTION OUTPUT ;
    USE SIGNAL ;
    PORT
      LAYER M3 ;
        RECT  55.728 0 55.746 0.038 ;
    END
    PORT
      LAYER M3 ;
        RECT  55.728 0.012 55.746 2.143 ;
    END
  END req_lo[56]
  PIN req_lo[57]
    DIRECTION OUTPUT ;
    USE SIGNAL ;
    PORT
      LAYER M5 ;
        RECT  56.688 0 56.712 0.084 ;
    END
    PORT
      LAYER M5 ;
        RECT  56.688 0.016 56.712 0.563 ;
    END
  END req_lo[57]
  PIN req_lo[58]
    DIRECTION OUTPUT ;
    USE SIGNAL ;
    PORT
      LAYER M3 ;
        RECT  57.672 0 57.69 0.038 ;
    END
    PORT
      LAYER M3 ;
        RECT  57.672 0.012 57.69 2.191 ;
    END
  END req_lo[58]
  PIN req_lo[59]
    DIRECTION OUTPUT ;
    USE SIGNAL ;
    PORT
      LAYER M5 ;
        RECT  58.656 0 58.68 0.084 ;
    END
    PORT
      LAYER M5 ;
        RECT  58.656 0.016 58.68 0.131 ;
    END
  END req_lo[59]
  PIN req_lo[5]
    DIRECTION OUTPUT ;
    USE SIGNAL ;
    PORT
      LAYER M5 ;
        RECT  6.336 0 6.36 0.084 ;
    END
    PORT
      LAYER M5 ;
        RECT  6.336 0.016 6.36 1.763 ;
    END
  END req_lo[5]
  PIN req_lo[60]
    DIRECTION OUTPUT ;
    USE SIGNAL ;
    PORT
      LAYER M3 ;
        RECT  59.616 0 59.634 0.038 ;
    END
    PORT
      LAYER M3 ;
        RECT  59.616 0.012 59.634 2.191 ;
    END
  END req_lo[60]
  PIN req_lo[61]
    DIRECTION OUTPUT ;
    USE SIGNAL ;
    PORT
      LAYER M5 ;
        RECT  60.576 0 60.6 0.084 ;
    END
    PORT
      LAYER M5 ;
        RECT  60.576 0.016 60.6 0.131 ;
    END
  END req_lo[61]
  PIN req_lo[62]
    DIRECTION OUTPUT ;
    USE SIGNAL ;
    PORT
      LAYER M3 ;
        RECT  61.56 0 61.578 0.038 ;
    END
    PORT
      LAYER M3 ;
        RECT  61.56 0.012 61.578 2.143 ;
    END
  END req_lo[62]
  PIN req_lo[63]
    DIRECTION OUTPUT ;
    USE SIGNAL ;
    PORT
      LAYER M5 ;
        RECT  62.496 0 62.52 0.084 ;
    END
    PORT
      LAYER M5 ;
        RECT  62.496 0.016 62.52 0.131 ;
    END
  END req_lo[63]
  PIN req_lo[64]
    DIRECTION OUTPUT ;
    USE SIGNAL ;
    PORT
      LAYER M3 ;
        RECT  63.468 0 63.486 0.038 ;
    END
    PORT
      LAYER M3 ;
        RECT  63.468 0.012 63.486 2.227 ;
    END
  END req_lo[64]
  PIN req_lo[65]
    DIRECTION OUTPUT ;
    USE SIGNAL ;
    PORT
      LAYER M5 ;
        RECT  64.464 0 64.488 0.084 ;
    END
    PORT
      LAYER M5 ;
        RECT  64.464 0.016 64.488 0.131 ;
    END
  END req_lo[65]
  PIN req_lo[66]
    DIRECTION OUTPUT ;
    USE SIGNAL ;
    PORT
      LAYER M3 ;
        RECT  65.412 0 65.43 0.038 ;
    END
    PORT
      LAYER M3 ;
        RECT  65.412 0.012 65.43 2.191 ;
    END
  END req_lo[66]
  PIN req_lo[67]
    DIRECTION OUTPUT ;
    USE SIGNAL ;
    PORT
      LAYER M5 ;
        RECT  66.384 0 66.408 0.084 ;
    END
    PORT
      LAYER M5 ;
        RECT  66.384 0.016 66.408 0.131 ;
    END
  END req_lo[67]
  PIN req_lo[68]
    DIRECTION OUTPUT ;
    USE SIGNAL ;
    PORT
      LAYER M3 ;
        RECT  67.356 0 67.374 0.038 ;
    END
    PORT
      LAYER M3 ;
        RECT  67.356 0.012 67.374 2.143 ;
    END
  END req_lo[68]
  PIN req_lo[69]
    DIRECTION OUTPUT ;
    USE SIGNAL ;
    PORT
      LAYER M5 ;
        RECT  68.304 0 68.328 0.084 ;
    END
    PORT
      LAYER M5 ;
        RECT  68.304 0.016 68.328 0.131 ;
    END
  END req_lo[69]
  PIN req_lo[6]
    DIRECTION OUTPUT ;
    USE SIGNAL ;
    PORT
      LAYER M3 ;
        RECT  7.272 0 7.29 0.038 ;
    END
    PORT
      LAYER M3 ;
        RECT  7.272 0.012 7.29 2.101 ;
    END
  END req_lo[6]
  PIN req_lo[70]
    DIRECTION OUTPUT ;
    USE SIGNAL ;
    PORT
      LAYER M3 ;
        RECT  69.3 0 69.318 0.038 ;
    END
    PORT
      LAYER M3 ;
        RECT  69.3 0.012 69.318 2.191 ;
    END
  END req_lo[70]
  PIN req_lo[71]
    DIRECTION OUTPUT ;
    USE SIGNAL ;
    PORT
      LAYER M5 ;
        RECT  70.272 0 70.296 0.084 ;
    END
    PORT
      LAYER M5 ;
        RECT  70.272 0.016 70.296 0.131 ;
    END
  END req_lo[71]
  PIN req_lo[72]
    DIRECTION OUTPUT ;
    USE SIGNAL ;
    PORT
      LAYER M3 ;
        RECT  71.244 0 71.262 0.038 ;
    END
    PORT
      LAYER M3 ;
        RECT  71.244 0.012 71.262 2.191 ;
    END
  END req_lo[72]
  PIN req_lo[73]
    DIRECTION OUTPUT ;
    USE SIGNAL ;
    PORT
      LAYER M5 ;
        RECT  72.192 0 72.216 0.084 ;
    END
    PORT
      LAYER M5 ;
        RECT  72.192 0.016 72.216 0.131 ;
    END
  END req_lo[73]
  PIN req_lo[74]
    DIRECTION OUTPUT ;
    USE SIGNAL ;
    PORT
      LAYER M3 ;
        RECT  73.152 0 73.17 0.038 ;
    END
    PORT
      LAYER M3 ;
        RECT  73.152 0.012 73.17 2.143 ;
    END
  END req_lo[74]
  PIN req_lo[75]
    DIRECTION OUTPUT ;
    USE SIGNAL ;
    PORT
      LAYER M5 ;
        RECT  74.112 0 74.136 0.084 ;
    END
    PORT
      LAYER M5 ;
        RECT  74.112 0.016 74.136 0.131 ;
    END
  END req_lo[75]
  PIN req_lo[7]
    DIRECTION OUTPUT ;
    USE SIGNAL ;
    PORT
      LAYER M5 ;
        RECT  8.256 0 8.28 0.084 ;
    END
    PORT
      LAYER M5 ;
        RECT  8.256 0.016 8.28 0.131 ;
    END
  END req_lo[7]
  PIN req_lo[8]
    DIRECTION OUTPUT ;
    USE SIGNAL ;
    PORT
      LAYER M3 ;
        RECT  9.216 0 9.234 0.038 ;
    END
    PORT
      LAYER M3 ;
        RECT  9.216 0.012 9.234 2.191 ;
    END
  END req_lo[8]
  PIN req_lo[9]
    DIRECTION OUTPUT ;
    USE SIGNAL ;
    PORT
      LAYER M5 ;
        RECT  10.176 0 10.2 0.084 ;
    END
    PORT
      LAYER M5 ;
        RECT  10.176 0.016 10.2 1.763 ;
    END
  END req_lo[9]
  PIN req_t[0]
    DIRECTION INPUT ;
    USE SIGNAL ;
    PORT
      LAYER M4 ;
        RECT  0 7.056 0.084 7.08 ;
    END
  END req_t[0]
  PIN req_t[10]
    DIRECTION INPUT ;
    USE SIGNAL ;
    PORT
      LAYER M4 ;
        RECT  0 9.6 0.084 9.624 ;
    END
  END req_t[10]
  PIN req_t[11]
    DIRECTION INPUT ;
    USE SIGNAL ;
    PORT
      LAYER M4 ;
        RECT  0 9.84 0.084 9.864 ;
    END
  END req_t[11]
  PIN req_t[12]
    DIRECTION INPUT ;
    USE SIGNAL ;
    PORT
      LAYER M4 ;
        RECT  0 10.128 0.084 10.152 ;
    END
  END req_t[12]
  PIN req_t[13]
    DIRECTION INPUT ;
    USE SIGNAL ;
    PORT
      LAYER M4 ;
        RECT  0 10.368 0.084 10.392 ;
    END
  END req_t[13]
  PIN req_t[1]
    DIRECTION INPUT ;
    USE SIGNAL ;
    PORT
      LAYER M4 ;
        RECT  0 7.296 0.084 7.32 ;
    END
  END req_t[1]
  PIN req_t[2]
    DIRECTION INPUT ;
    USE SIGNAL ;
    PORT
      LAYER M4 ;
        RECT  0 7.536 0.084 7.56 ;
    END
  END req_t[2]
  PIN req_t[3]
    DIRECTION INPUT ;
    USE SIGNAL ;
    PORT
      LAYER M4 ;
        RECT  0 7.824 0.084 7.848 ;
    END
  END req_t[3]
  PIN req_t[4]
    DIRECTION INPUT ;
    USE SIGNAL ;
    PORT
      LAYER M4 ;
        RECT  0 8.064 0.084 8.088 ;
    END
  END req_t[4]
  PIN req_t[5]
    DIRECTION INPUT ;
    USE SIGNAL ;
    PORT
      LAYER M4 ;
        RECT  0 8.304 0.084 8.328 ;
    END
  END req_t[5]
  PIN req_t[6]
    DIRECTION INPUT ;
    USE SIGNAL ;
    PORT
      LAYER M4 ;
        RECT  0 8.592 0.084 8.616 ;
    END
  END req_t[6]
  PIN req_t[7]
    DIRECTION INPUT ;
    USE SIGNAL ;
    PORT
      LAYER M4 ;
        RECT  0 8.832 0.084 8.856 ;
    END
  END req_t[7]
  PIN req_t[8]
    DIRECTION INPUT ;
    USE SIGNAL ;
    PORT
      LAYER M4 ;
        RECT  0 9.072 0.084 9.096 ;
    END
  END req_t[8]
  PIN req_t[9]
    DIRECTION INPUT ;
    USE SIGNAL ;
    PORT
      LAYER M4 ;
        RECT  0 9.36 0.084 9.384 ;
    END
  END req_t[9]
  PIN req_v
    DIRECTION INPUT ;
    USE SIGNAL ;
    PORT
      LAYER M4 ;
        RECT  0 10.656 0.084 10.68 ;
    END
  END req_v
  PIN req_valid
    DIRECTION INPUT ;
    USE SIGNAL ;
    PORT
      LAYER M4 ;
        RECT  0 10.896 0.084 10.92 ;
    END
  END req_valid
  PIN rsp_epoch[0]
    DIRECTION OUTPUT ;
    USE SIGNAL ;
    PORT
      LAYER M4 ;
        RECT  0 11.136 0.084 11.16 ;
    END
  END rsp_epoch[0]
  PIN rsp_epoch[10]
    DIRECTION OUTPUT ;
    USE SIGNAL ;
    PORT
      LAYER M4 ;
        RECT  0 13.728 0.084 13.752 ;
    END
  END rsp_epoch[10]
  PIN rsp_epoch[11]
    DIRECTION OUTPUT ;
    USE SIGNAL ;
    PORT
      LAYER M4 ;
        RECT  0 13.968 0.084 13.992 ;
    END
  END rsp_epoch[11]
  PIN rsp_epoch[12]
    DIRECTION OUTPUT ;
    USE SIGNAL ;
    PORT
      LAYER M4 ;
        RECT  0 14.256 0.084 14.28 ;
    END
  END rsp_epoch[12]
  PIN rsp_epoch[13]
    DIRECTION OUTPUT ;
    USE SIGNAL ;
    PORT
      LAYER M4 ;
        RECT  0 14.496 0.084 14.52 ;
    END
  END rsp_epoch[13]
  PIN rsp_epoch[14]
    DIRECTION OUTPUT ;
    USE SIGNAL ;
    PORT
      LAYER M4 ;
        RECT  0 14.736 0.084 14.76 ;
    END
  END rsp_epoch[14]
  PIN rsp_epoch[15]
    DIRECTION OUTPUT ;
    USE SIGNAL ;
    PORT
      LAYER M4 ;
        RECT  0 15.024 0.084 15.048 ;
    END
  END rsp_epoch[15]
  PIN rsp_epoch[1]
    DIRECTION OUTPUT ;
    USE SIGNAL ;
    PORT
      LAYER M4 ;
        RECT  0 11.424 0.084 11.448 ;
    END
  END rsp_epoch[1]
  PIN rsp_epoch[2]
    DIRECTION OUTPUT ;
    USE SIGNAL ;
    PORT
      LAYER M4 ;
        RECT  0 11.664 0.084 11.688 ;
    END
  END rsp_epoch[2]
  PIN rsp_epoch[3]
    DIRECTION OUTPUT ;
    USE SIGNAL ;
    PORT
      LAYER M4 ;
        RECT  0 11.904 0.084 11.928 ;
    END
  END rsp_epoch[3]
  PIN rsp_epoch[4]
    DIRECTION OUTPUT ;
    USE SIGNAL ;
    PORT
      LAYER M4 ;
        RECT  0 12.192 0.084 12.216 ;
    END
  END rsp_epoch[4]
  PIN rsp_epoch[5]
    DIRECTION OUTPUT ;
    USE SIGNAL ;
    PORT
      LAYER M4 ;
        RECT  0 12.432 0.084 12.456 ;
    END
  END rsp_epoch[5]
  PIN rsp_epoch[6]
    DIRECTION OUTPUT ;
    USE SIGNAL ;
    PORT
      LAYER M4 ;
        RECT  0 12.672 0.084 12.696 ;
    END
  END rsp_epoch[6]
  PIN rsp_epoch[7]
    DIRECTION OUTPUT ;
    USE SIGNAL ;
    PORT
      LAYER M4 ;
        RECT  0 12.96 0.084 12.984 ;
    END
  END rsp_epoch[7]
  PIN rsp_epoch[8]
    DIRECTION OUTPUT ;
    USE SIGNAL ;
    PORT
      LAYER M4 ;
        RECT  0 13.2 0.084 13.224 ;
    END
  END rsp_epoch[8]
  PIN rsp_epoch[9]
    DIRECTION OUTPUT ;
    USE SIGNAL ;
    PORT
      LAYER M4 ;
        RECT  0 13.44 0.084 13.464 ;
    END
  END rsp_epoch[9]
  PIN rsp_hi[0]
    DIRECTION INPUT ;
    USE SIGNAL ;
    PORT
      LAYER M5 ;
        RECT  75.6 25.836 75.624 25.92 ;
    END
    PORT
      LAYER M5 ;
        RECT  75.6 23.701 75.624 25.872 ;
    END
  END rsp_hi[0]
  PIN rsp_hi[10]
    DIRECTION INPUT ;
    USE SIGNAL ;
    PORT
      LAYER M5 ;
        RECT  85.2 25.836 85.224 25.92 ;
    END
    PORT
      LAYER M5 ;
        RECT  85.2 23.701 85.224 25.872 ;
    END
  END rsp_hi[10]
  PIN rsp_hi[11]
    DIRECTION INPUT ;
    USE SIGNAL ;
    PORT
      LAYER M3 ;
        RECT  86.184 25.882 86.202 25.92 ;
    END
    PORT
      LAYER M3 ;
        RECT  86.184 23.741 86.202 25.901 ;
    END
  END rsp_hi[11]
  PIN rsp_hi[12]
    DIRECTION INPUT ;
    USE SIGNAL ;
    PORT
      LAYER M5 ;
        RECT  87.12 25.836 87.144 25.92 ;
    END
    PORT
      LAYER M5 ;
        RECT  87.12 23.701 87.144 25.872 ;
    END
  END rsp_hi[12]
  PIN rsp_hi[13]
    DIRECTION INPUT ;
    USE SIGNAL ;
    PORT
      LAYER M3 ;
        RECT  88.092 25.882 88.11 25.92 ;
    END
    PORT
      LAYER M3 ;
        RECT  88.092 25.133 88.11 25.901 ;
    END
  END rsp_hi[13]
  PIN rsp_hi[14]
    DIRECTION INPUT ;
    USE SIGNAL ;
    PORT
      LAYER M5 ;
        RECT  89.088 25.836 89.112 25.92 ;
    END
    PORT
      LAYER M5 ;
        RECT  89.088 25.093 89.112 25.872 ;
    END
  END rsp_hi[14]
  PIN rsp_hi[15]
    DIRECTION INPUT ;
    USE SIGNAL ;
    PORT
      LAYER M3 ;
        RECT  90.036 25.882 90.054 25.92 ;
    END
    PORT
      LAYER M3 ;
        RECT  90.036 23.431 90.054 25.901 ;
    END
  END rsp_hi[15]
  PIN rsp_hi[16]
    DIRECTION INPUT ;
    USE SIGNAL ;
    PORT
      LAYER M5 ;
        RECT  91.008 25.836 91.032 25.92 ;
    END
    PORT
      LAYER M5 ;
        RECT  91.008 23.701 91.032 25.872 ;
    END
  END rsp_hi[16]
  PIN rsp_hi[17]
    DIRECTION INPUT ;
    USE SIGNAL ;
    PORT
      LAYER M3 ;
        RECT  91.944 25.882 91.962 25.92 ;
    END
    PORT
      LAYER M3 ;
        RECT  91.944 23.549 91.962 25.901 ;
    END
  END rsp_hi[17]
  PIN rsp_hi[18]
    DIRECTION INPUT ;
    USE SIGNAL ;
    PORT
      LAYER M5 ;
        RECT  92.928 25.836 92.952 25.92 ;
    END
    PORT
      LAYER M5 ;
        RECT  92.928 25.765 92.952 25.872 ;
    END
  END rsp_hi[18]
  PIN rsp_hi[19]
    DIRECTION INPUT ;
    USE SIGNAL ;
    PORT
      LAYER M3 ;
        RECT  93.888 25.882 93.906 25.92 ;
    END
    PORT
      LAYER M3 ;
        RECT  93.888 23.777 93.906 25.901 ;
    END
  END rsp_hi[19]
  PIN rsp_hi[1]
    DIRECTION INPUT ;
    USE SIGNAL ;
    PORT
      LAYER M3 ;
        RECT  76.572 25.882 76.59 25.92 ;
    END
    PORT
      LAYER M3 ;
        RECT  76.572 25.133 76.59 25.901 ;
    END
  END rsp_hi[1]
  PIN rsp_hi[20]
    DIRECTION INPUT ;
    USE SIGNAL ;
    PORT
      LAYER M5 ;
        RECT  94.848 25.836 94.872 25.92 ;
    END
    PORT
      LAYER M5 ;
        RECT  94.848 23.893 94.872 25.872 ;
    END
  END rsp_hi[20]
  PIN rsp_hi[21]
    DIRECTION INPUT ;
    USE SIGNAL ;
    PORT
      LAYER M3 ;
        RECT  95.796 25.882 95.814 25.92 ;
    END
    PORT
      LAYER M3 ;
        RECT  95.796 23.741 95.814 25.901 ;
    END
  END rsp_hi[21]
  PIN rsp_hi[22]
    DIRECTION INPUT ;
    USE SIGNAL ;
    PORT
      LAYER M5 ;
        RECT  96.768 25.836 96.792 25.92 ;
    END
    PORT
      LAYER M5 ;
        RECT  96.768 23.701 96.792 25.872 ;
    END
  END rsp_hi[22]
  PIN rsp_hi[23]
    DIRECTION INPUT ;
    USE SIGNAL ;
    PORT
      LAYER M3 ;
        RECT  97.74 25.882 97.758 25.92 ;
    END
    PORT
      LAYER M3 ;
        RECT  97.74 25.133 97.758 25.901 ;
    END
  END rsp_hi[23]
  PIN rsp_hi[24]
    DIRECTION INPUT ;
    USE SIGNAL ;
    PORT
      LAYER M5 ;
        RECT  98.688 25.836 98.712 25.92 ;
    END
    PORT
      LAYER M5 ;
        RECT  98.688 25.093 98.712 25.872 ;
    END
  END rsp_hi[24]
  PIN rsp_hi[25]
    DIRECTION INPUT ;
    USE SIGNAL ;
    PORT
      LAYER M3 ;
        RECT  99.648 25.882 99.666 25.92 ;
    END
    PORT
      LAYER M3 ;
        RECT  99.648 23.933 99.666 25.901 ;
    END
  END rsp_hi[25]
  PIN rsp_hi[26]
    DIRECTION INPUT ;
    USE SIGNAL ;
    PORT
      LAYER M5 ;
        RECT  100.608 25.836 100.632 25.92 ;
    END
    PORT
      LAYER M5 ;
        RECT  100.608 23.893 100.632 25.872 ;
    END
  END rsp_hi[26]
  PIN rsp_hi[27]
    DIRECTION INPUT ;
    USE SIGNAL ;
    PORT
      LAYER M3 ;
        RECT  101.592 25.882 101.61 25.92 ;
    END
    PORT
      LAYER M3 ;
        RECT  101.592 23.933 101.61 25.901 ;
    END
  END rsp_hi[27]
  PIN rsp_hi[28]
    DIRECTION INPUT ;
    USE SIGNAL ;
    PORT
      LAYER M5 ;
        RECT  102.528 25.836 102.552 25.92 ;
    END
    PORT
      LAYER M5 ;
        RECT  102.528 23.893 102.552 25.872 ;
    END
  END rsp_hi[28]
  PIN rsp_hi[29]
    DIRECTION INPUT ;
    USE SIGNAL ;
    PORT
      LAYER M3 ;
        RECT  103.5 25.882 103.518 25.92 ;
    END
    PORT
      LAYER M3 ;
        RECT  103.5 25.133 103.518 25.901 ;
    END
  END rsp_hi[29]
  PIN rsp_hi[2]
    DIRECTION INPUT ;
    USE SIGNAL ;
    PORT
      LAYER M5 ;
        RECT  77.52 25.836 77.544 25.92 ;
    END
    PORT
      LAYER M5 ;
        RECT  77.52 25.093 77.544 25.872 ;
    END
  END rsp_hi[2]
  PIN rsp_hi[30]
    DIRECTION INPUT ;
    USE SIGNAL ;
    PORT
      LAYER M5 ;
        RECT  104.448 25.836 104.472 25.92 ;
    END
    PORT
      LAYER M5 ;
        RECT  104.448 25.093 104.472 25.872 ;
    END
  END rsp_hi[30]
  PIN rsp_hi[31]
    DIRECTION INPUT ;
    USE SIGNAL ;
    PORT
      LAYER M3 ;
        RECT  105.444 25.882 105.462 25.92 ;
    END
    PORT
      LAYER M3 ;
        RECT  105.444 23.777 105.462 25.901 ;
    END
  END rsp_hi[31]
  PIN rsp_hi[32]
    DIRECTION INPUT ;
    USE SIGNAL ;
    PORT
      LAYER M5 ;
        RECT  106.368 25.836 106.392 25.92 ;
    END
    PORT
      LAYER M5 ;
        RECT  106.368 23.701 106.392 25.872 ;
    END
  END rsp_hi[32]
  PIN rsp_hi[33]
    DIRECTION INPUT ;
    USE SIGNAL ;
    PORT
      LAYER M3 ;
        RECT  107.352 25.882 107.37 25.92 ;
    END
    PORT
      LAYER M3 ;
        RECT  107.352 25.133 107.37 25.901 ;
    END
  END rsp_hi[33]
  PIN rsp_hi[34]
    DIRECTION INPUT ;
    USE SIGNAL ;
    PORT
      LAYER M5 ;
        RECT  108.336 25.836 108.36 25.92 ;
    END
    PORT
      LAYER M5 ;
        RECT  108.336 25.093 108.36 25.872 ;
    END
  END rsp_hi[34]
  PIN rsp_hi[35]
    DIRECTION INPUT ;
    USE SIGNAL ;
    PORT
      LAYER M3 ;
        RECT  109.296 25.882 109.314 25.92 ;
    END
    PORT
      LAYER M3 ;
        RECT  109.296 23.741 109.314 25.901 ;
    END
  END rsp_hi[35]
  PIN rsp_hi[36]
    DIRECTION INPUT ;
    USE SIGNAL ;
    PORT
      LAYER M5 ;
        RECT  110.256 25.836 110.28 25.92 ;
    END
    PORT
      LAYER M5 ;
        RECT  110.256 23.783 110.28 25.872 ;
    END
  END rsp_hi[36]
  PIN rsp_hi[37]
    DIRECTION INPUT ;
    USE SIGNAL ;
    PORT
      LAYER M3 ;
        RECT  111.204 25.882 111.222 25.92 ;
    END
    PORT
      LAYER M3 ;
        RECT  111.204 23.777 111.222 25.901 ;
    END
  END rsp_hi[37]
  PIN rsp_hi[38]
    DIRECTION INPUT ;
    USE SIGNAL ;
    PORT
      LAYER M5 ;
        RECT  112.176 25.836 112.2 25.92 ;
    END
    PORT
      LAYER M5 ;
        RECT  112.176 23.701 112.2 25.872 ;
    END
  END rsp_hi[38]
  PIN rsp_hi[39]
    DIRECTION INPUT ;
    USE SIGNAL ;
    PORT
      LAYER M3 ;
        RECT  113.148 25.882 113.166 25.92 ;
    END
    PORT
      LAYER M3 ;
        RECT  113.148 25.805 113.166 25.901 ;
    END
  END rsp_hi[39]
  PIN rsp_hi[3]
    DIRECTION INPUT ;
    USE SIGNAL ;
    PORT
      LAYER M3 ;
        RECT  78.48 25.882 78.498 25.92 ;
    END
    PORT
      LAYER M3 ;
        RECT  78.48 25.805 78.498 25.901 ;
    END
  END rsp_hi[3]
  PIN rsp_hi[40]
    DIRECTION INPUT ;
    USE SIGNAL ;
    PORT
      LAYER M5 ;
        RECT  114.096 25.836 114.12 25.92 ;
    END
    PORT
      LAYER M5 ;
        RECT  114.096 25.765 114.12 25.872 ;
    END
  END rsp_hi[40]
  PIN rsp_hi[41]
    DIRECTION INPUT ;
    USE SIGNAL ;
    PORT
      LAYER M3 ;
        RECT  115.056 25.882 115.074 25.92 ;
    END
    PORT
      LAYER M3 ;
        RECT  115.056 25.133 115.074 25.901 ;
    END
  END rsp_hi[41]
  PIN rsp_hi[42]
    DIRECTION INPUT ;
    USE SIGNAL ;
    PORT
      LAYER M5 ;
        RECT  116.016 25.836 116.04 25.92 ;
    END
    PORT
      LAYER M5 ;
        RECT  116.016 25.093 116.04 25.872 ;
    END
  END rsp_hi[42]
  PIN rsp_hi[43]
    DIRECTION INPUT ;
    USE SIGNAL ;
    PORT
      LAYER M3 ;
        RECT  117 25.882 117.018 25.92 ;
    END
    PORT
      LAYER M3 ;
        RECT  117 23.933 117.018 25.901 ;
    END
  END rsp_hi[43]
  PIN rsp_hi[44]
    DIRECTION INPUT ;
    USE SIGNAL ;
    PORT
      LAYER M5 ;
        RECT  117.936 25.836 117.96 25.92 ;
    END
    PORT
      LAYER M5 ;
        RECT  117.936 23.893 117.96 25.872 ;
    END
  END rsp_hi[44]
  PIN rsp_hi[45]
    DIRECTION INPUT ;
    USE SIGNAL ;
    PORT
      LAYER M3 ;
        RECT  118.908 25.882 118.926 25.92 ;
    END
    PORT
      LAYER M3 ;
        RECT  118.908 25.133 118.926 25.901 ;
    END
  END rsp_hi[45]
  PIN rsp_hi[46]
    DIRECTION INPUT ;
    USE SIGNAL ;
    PORT
      LAYER M5 ;
        RECT  119.856 25.836 119.88 25.92 ;
    END
    PORT
      LAYER M5 ;
        RECT  119.856 25.093 119.88 25.872 ;
    END
  END rsp_hi[46]
  PIN rsp_hi[47]
    DIRECTION INPUT ;
    USE SIGNAL ;
    PORT
      LAYER M3 ;
        RECT  120.816 25.882 120.834 25.92 ;
    END
    PORT
      LAYER M3 ;
        RECT  120.816 23.777 120.834 25.901 ;
    END
  END rsp_hi[47]
  PIN rsp_hi[48]
    DIRECTION INPUT ;
    USE SIGNAL ;
    PORT
      LAYER M5 ;
        RECT  121.776 25.836 121.8 25.92 ;
    END
    PORT
      LAYER M5 ;
        RECT  121.776 23.783 121.8 25.872 ;
    END
  END rsp_hi[48]
  PIN rsp_hi[49]
    DIRECTION INPUT ;
    USE SIGNAL ;
    PORT
      LAYER M3 ;
        RECT  122.76 25.882 122.778 25.92 ;
    END
    PORT
      LAYER M3 ;
        RECT  122.76 23.665 122.778 25.901 ;
    END
  END rsp_hi[49]
  PIN rsp_hi[4]
    DIRECTION INPUT ;
    USE SIGNAL ;
    PORT
      LAYER M5 ;
        RECT  79.44 25.836 79.464 25.92 ;
    END
    PORT
      LAYER M5 ;
        RECT  79.44 25.765 79.464 25.872 ;
    END
  END rsp_hi[4]
  PIN rsp_hi[50]
    DIRECTION INPUT ;
    USE SIGNAL ;
    PORT
      LAYER M5 ;
        RECT  123.696 25.836 123.72 25.92 ;
    END
    PORT
      LAYER M5 ;
        RECT  123.696 25.093 123.72 25.872 ;
    END
  END rsp_hi[50]
  PIN rsp_hi[51]
    DIRECTION INPUT ;
    USE SIGNAL ;
    PORT
      LAYER M3 ;
        RECT  124.668 25.882 124.686 25.92 ;
    END
    PORT
      LAYER M3 ;
        RECT  124.668 25.805 124.686 25.901 ;
    END
  END rsp_hi[51]
  PIN rsp_hi[52]
    DIRECTION INPUT ;
    USE SIGNAL ;
    PORT
      LAYER M5 ;
        RECT  125.664 25.836 125.688 25.92 ;
    END
    PORT
      LAYER M5 ;
        RECT  125.664 25.765 125.688 25.872 ;
    END
  END rsp_hi[52]
  PIN rsp_hi[53]
    DIRECTION INPUT ;
    USE SIGNAL ;
    PORT
      LAYER M3 ;
        RECT  126.612 25.882 126.63 25.92 ;
    END
    PORT
      LAYER M3 ;
        RECT  126.612 23.855 126.63 25.901 ;
    END
  END rsp_hi[53]
  PIN rsp_hi[54]
    DIRECTION INPUT ;
    USE SIGNAL ;
    PORT
      LAYER M5 ;
        RECT  127.584 25.836 127.608 25.92 ;
    END
    PORT
      LAYER M5 ;
        RECT  127.584 23.893 127.608 25.872 ;
    END
  END rsp_hi[54]
  PIN rsp_hi[55]
    DIRECTION INPUT ;
    USE SIGNAL ;
    PORT
      LAYER M3 ;
        RECT  128.52 25.882 128.538 25.92 ;
    END
    PORT
      LAYER M3 ;
        RECT  128.52 25.133 128.538 25.901 ;
    END
  END rsp_hi[55]
  PIN rsp_hi[56]
    DIRECTION INPUT ;
    USE SIGNAL ;
    PORT
      LAYER M5 ;
        RECT  129.504 25.836 129.528 25.92 ;
    END
    PORT
      LAYER M5 ;
        RECT  129.504 25.093 129.528 25.872 ;
    END
  END rsp_hi[56]
  PIN rsp_hi[57]
    DIRECTION INPUT ;
    USE SIGNAL ;
    PORT
      LAYER M3 ;
        RECT  130.464 25.882 130.482 25.92 ;
    END
    PORT
      LAYER M3 ;
        RECT  130.464 23.741 130.482 25.901 ;
    END
  END rsp_hi[57]
  PIN rsp_hi[58]
    DIRECTION INPUT ;
    USE SIGNAL ;
    PORT
      LAYER M5 ;
        RECT  131.424 25.836 131.448 25.92 ;
    END
    PORT
      LAYER M5 ;
        RECT  131.424 23.783 131.448 25.872 ;
    END
  END rsp_hi[58]
  PIN rsp_hi[59]
    DIRECTION INPUT ;
    USE SIGNAL ;
    PORT
      LAYER M3 ;
        RECT  132.372 25.882 132.39 25.92 ;
    END
    PORT
      LAYER M3 ;
        RECT  132.372 23.933 132.39 25.901 ;
    END
  END rsp_hi[59]
  PIN rsp_hi[5]
    DIRECTION INPUT ;
    USE SIGNAL ;
    PORT
      LAYER M3 ;
        RECT  80.388 25.882 80.406 25.92 ;
    END
    PORT
      LAYER M3 ;
        RECT  80.388 23.549 80.406 25.901 ;
    END
  END rsp_hi[5]
  PIN rsp_hi[60]
    DIRECTION INPUT ;
    USE SIGNAL ;
    PORT
      LAYER M5 ;
        RECT  133.344 25.836 133.368 25.92 ;
    END
    PORT
      LAYER M5 ;
        RECT  133.344 23.893 133.368 25.872 ;
    END
  END rsp_hi[60]
  PIN rsp_hi[61]
    DIRECTION INPUT ;
    USE SIGNAL ;
    PORT
      LAYER M3 ;
        RECT  134.316 25.882 134.334 25.92 ;
    END
    PORT
      LAYER M3 ;
        RECT  134.316 25.805 134.334 25.901 ;
    END
  END rsp_hi[61]
  PIN rsp_hi[62]
    DIRECTION INPUT ;
    USE SIGNAL ;
    PORT
      LAYER M5 ;
        RECT  135.264 25.836 135.288 25.92 ;
    END
    PORT
      LAYER M5 ;
        RECT  135.264 25.765 135.288 25.872 ;
    END
  END rsp_hi[62]
  PIN rsp_hi[63]
    DIRECTION INPUT ;
    USE SIGNAL ;
    PORT
      LAYER M3 ;
        RECT  136.224 25.882 136.242 25.92 ;
    END
    PORT
      LAYER M3 ;
        RECT  136.224 23.557 136.242 25.901 ;
    END
  END rsp_hi[63]
  PIN rsp_hi[64]
    DIRECTION INPUT ;
    USE SIGNAL ;
    PORT
      LAYER M5 ;
        RECT  137.184 25.836 137.208 25.92 ;
    END
    PORT
      LAYER M5 ;
        RECT  137.184 23.893 137.208 25.872 ;
    END
  END rsp_hi[64]
  PIN rsp_hi[65]
    DIRECTION INPUT ;
    USE SIGNAL ;
    PORT
      LAYER M3 ;
        RECT  138.168 25.882 138.186 25.92 ;
    END
    PORT
      LAYER M3 ;
        RECT  138.168 23.777 138.186 25.901 ;
    END
  END rsp_hi[65]
  PIN rsp_hi[66]
    DIRECTION INPUT ;
    USE SIGNAL ;
    PORT
      LAYER M5 ;
        RECT  139.104 25.836 139.128 25.92 ;
    END
    PORT
      LAYER M5 ;
        RECT  139.104 23.701 139.128 25.872 ;
    END
  END rsp_hi[66]
  PIN rsp_hi[67]
    DIRECTION INPUT ;
    USE SIGNAL ;
    PORT
      LAYER M3 ;
        RECT  140.076 25.882 140.094 25.92 ;
    END
    PORT
      LAYER M3 ;
        RECT  140.076 23.741 140.094 25.901 ;
    END
  END rsp_hi[67]
  PIN rsp_hi[68]
    DIRECTION INPUT ;
    USE SIGNAL ;
    PORT
      LAYER M5 ;
        RECT  141.024 25.836 141.048 25.92 ;
    END
    PORT
      LAYER M5 ;
        RECT  141.024 23.701 141.048 25.872 ;
    END
  END rsp_hi[68]
  PIN rsp_hi[69]
    DIRECTION INPUT ;
    USE SIGNAL ;
    PORT
      LAYER M3 ;
        RECT  142.02 25.882 142.038 25.92 ;
    END
    PORT
      LAYER M3 ;
        RECT  142.02 23.557 142.038 25.901 ;
    END
  END rsp_hi[69]
  PIN rsp_hi[6]
    DIRECTION INPUT ;
    USE SIGNAL ;
    PORT
      LAYER M5 ;
        RECT  81.36 25.836 81.384 25.92 ;
    END
    PORT
      LAYER M5 ;
        RECT  81.36 23.893 81.384 25.872 ;
    END
  END rsp_hi[6]
  PIN rsp_hi[70]
    DIRECTION INPUT ;
    USE SIGNAL ;
    PORT
      LAYER M5 ;
        RECT  142.992 25.836 143.016 25.92 ;
    END
    PORT
      LAYER M5 ;
        RECT  142.992 23.783 143.016 25.872 ;
    END
  END rsp_hi[70]
  PIN rsp_hi[71]
    DIRECTION INPUT ;
    USE SIGNAL ;
    PORT
      LAYER M3 ;
        RECT  143.928 25.882 143.946 25.92 ;
    END
    PORT
      LAYER M3 ;
        RECT  143.928 23.665 143.946 25.901 ;
    END
  END rsp_hi[71]
  PIN rsp_hi[72]
    DIRECTION INPUT ;
    USE SIGNAL ;
    PORT
      LAYER M5 ;
        RECT  144.912 25.836 144.936 25.92 ;
    END
    PORT
      LAYER M5 ;
        RECT  144.912 23.701 144.936 25.872 ;
    END
  END rsp_hi[72]
  PIN rsp_hi[73]
    DIRECTION INPUT ;
    USE SIGNAL ;
    PORT
      LAYER M3 ;
        RECT  145.872 25.882 145.89 25.92 ;
    END
    PORT
      LAYER M3 ;
        RECT  145.872 23.933 145.89 25.901 ;
    END
  END rsp_hi[73]
  PIN rsp_hi[74]
    DIRECTION INPUT ;
    USE SIGNAL ;
    PORT
      LAYER M5 ;
        RECT  146.832 25.836 146.856 25.92 ;
    END
    PORT
      LAYER M5 ;
        RECT  146.832 23.893 146.856 25.872 ;
    END
  END rsp_hi[74]
  PIN rsp_hi[75]
    DIRECTION INPUT ;
    USE SIGNAL ;
    PORT
      LAYER M3 ;
        RECT  147.78 25.882 147.798 25.92 ;
    END
    PORT
      LAYER M3 ;
        RECT  147.78 23.777 147.798 25.901 ;
    END
  END rsp_hi[75]
  PIN rsp_hi[76]
    DIRECTION INPUT ;
    USE SIGNAL ;
    PORT
      LAYER M5 ;
        RECT  148.752 25.836 148.776 25.92 ;
    END
    PORT
      LAYER M5 ;
        RECT  148.752 23.783 148.776 25.872 ;
    END
  END rsp_hi[76]
  PIN rsp_hi[77]
    DIRECTION INPUT ;
    USE SIGNAL ;
    PORT
      LAYER M3 ;
        RECT  149.724 25.882 149.742 25.92 ;
    END
    PORT
      LAYER M3 ;
        RECT  149.724 24.413 149.742 25.901 ;
    END
  END rsp_hi[77]
  PIN rsp_hi[7]
    DIRECTION INPUT ;
    USE SIGNAL ;
    PORT
      LAYER M3 ;
        RECT  82.332 25.882 82.35 25.92 ;
    END
    PORT
      LAYER M3 ;
        RECT  82.332 25.133 82.35 25.901 ;
    END
  END rsp_hi[7]
  PIN rsp_hi[8]
    DIRECTION INPUT ;
    USE SIGNAL ;
    PORT
      LAYER M5 ;
        RECT  83.28 25.836 83.304 25.92 ;
    END
    PORT
      LAYER M5 ;
        RECT  83.28 25.093 83.304 25.872 ;
    END
  END rsp_hi[8]
  PIN rsp_hi[9]
    DIRECTION INPUT ;
    USE SIGNAL ;
    PORT
      LAYER M3 ;
        RECT  84.24 25.882 84.258 25.92 ;
    END
    PORT
      LAYER M3 ;
        RECT  84.24 23.741 84.258 25.901 ;
    END
  END rsp_hi[9]
  PIN rsp_layer[0]
    DIRECTION OUTPUT ;
    USE SIGNAL ;
    PORT
      LAYER M4 ;
        RECT  0 15.264 0.084 15.288 ;
    END
  END rsp_layer[0]
  PIN rsp_layer[1]
    DIRECTION OUTPUT ;
    USE SIGNAL ;
    PORT
      LAYER M4 ;
        RECT  0 15.504 0.084 15.528 ;
    END
  END rsp_layer[1]
  PIN rsp_layer[2]
    DIRECTION OUTPUT ;
    USE SIGNAL ;
    PORT
      LAYER M4 ;
        RECT  0 15.792 0.084 15.816 ;
    END
  END rsp_layer[2]
  PIN rsp_layer[3]
    DIRECTION OUTPUT ;
    USE SIGNAL ;
    PORT
      LAYER M4 ;
        RECT  0 16.032 0.084 16.056 ;
    END
  END rsp_layer[3]
  PIN rsp_layer[4]
    DIRECTION OUTPUT ;
    USE SIGNAL ;
    PORT
      LAYER M4 ;
        RECT  0 16.272 0.084 16.296 ;
    END
  END rsp_layer[4]
  PIN rsp_layer[5]
    DIRECTION OUTPUT ;
    USE SIGNAL ;
    PORT
      LAYER M4 ;
        RECT  0 16.56 0.084 16.584 ;
    END
  END rsp_layer[5]
  PIN rsp_lo[0]
    DIRECTION INPUT ;
    USE SIGNAL ;
    PORT
      LAYER M3 ;
        RECT  75.096 0 75.114 0.038 ;
    END
    PORT
      LAYER M3 ;
        RECT  75.096 0.012 75.114 2.101 ;
    END
  END rsp_lo[0]
  PIN rsp_lo[10]
    DIRECTION INPUT ;
    USE SIGNAL ;
    PORT
      LAYER M3 ;
        RECT  84.78 0 84.798 0.038 ;
    END
    PORT
      LAYER M3 ;
        RECT  84.78 0.012 84.798 2.291 ;
    END
  END rsp_lo[10]
  PIN rsp_lo[11]
    DIRECTION INPUT ;
    USE SIGNAL ;
    PORT
      LAYER M5 ;
        RECT  85.776 0 85.8 0.084 ;
    END
    PORT
      LAYER M5 ;
        RECT  85.776 0.016 85.8 1.763 ;
    END
  END rsp_lo[11]
  PIN rsp_lo[12]
    DIRECTION INPUT ;
    USE SIGNAL ;
    PORT
      LAYER M3 ;
        RECT  86.724 0 86.742 0.038 ;
    END
    PORT
      LAYER M3 ;
        RECT  86.724 0.012 86.742 1.723 ;
    END
  END rsp_lo[12]
  PIN rsp_lo[13]
    DIRECTION INPUT ;
    USE SIGNAL ;
    PORT
      LAYER M5 ;
        RECT  87.696 0 87.72 0.084 ;
    END
    PORT
      LAYER M5 ;
        RECT  87.696 0.016 87.72 1.763 ;
    END
  END rsp_lo[13]
  PIN rsp_lo[14]
    DIRECTION INPUT ;
    USE SIGNAL ;
    PORT
      LAYER M3 ;
        RECT  88.668 0 88.686 0.038 ;
    END
    PORT
      LAYER M3 ;
        RECT  88.668 0.012 88.686 2.143 ;
    END
  END rsp_lo[14]
  PIN rsp_lo[15]
    DIRECTION INPUT ;
    USE SIGNAL ;
    PORT
      LAYER M5 ;
        RECT  89.616 0 89.64 0.084 ;
    END
    PORT
      LAYER M5 ;
        RECT  89.616 0.016 89.64 0.611 ;
    END
  END rsp_lo[15]
  PIN rsp_lo[16]
    DIRECTION INPUT ;
    USE SIGNAL ;
    PORT
      LAYER M3 ;
        RECT  90.612 0 90.63 0.038 ;
    END
    PORT
      LAYER M3 ;
        RECT  90.612 0.012 90.63 1.723 ;
    END
  END rsp_lo[16]
  PIN rsp_lo[17]
    DIRECTION INPUT ;
    USE SIGNAL ;
    PORT
      LAYER M5 ;
        RECT  91.584 0 91.608 0.084 ;
    END
    PORT
      LAYER M5 ;
        RECT  91.584 0.016 91.608 1.763 ;
    END
  END rsp_lo[17]
  PIN rsp_lo[18]
    DIRECTION INPUT ;
    USE SIGNAL ;
    PORT
      LAYER M3 ;
        RECT  92.556 0 92.574 0.038 ;
    END
    PORT
      LAYER M3 ;
        RECT  92.556 0.012 92.574 2.291 ;
    END
  END rsp_lo[18]
  PIN rsp_lo[19]
    DIRECTION INPUT ;
    USE SIGNAL ;
    PORT
      LAYER M5 ;
        RECT  93.504 0 93.528 0.084 ;
    END
    PORT
      LAYER M5 ;
        RECT  93.504 0.016 93.528 0.611 ;
    END
  END rsp_lo[19]
  PIN rsp_lo[1]
    DIRECTION INPUT ;
    USE SIGNAL ;
    PORT
      LAYER M5 ;
        RECT  76.08 0 76.104 0.084 ;
    END
    PORT
      LAYER M5 ;
        RECT  76.08 0.016 76.104 1.763 ;
    END
  END rsp_lo[1]
  PIN rsp_lo[20]
    DIRECTION INPUT ;
    USE SIGNAL ;
    PORT
      LAYER M3 ;
        RECT  94.5 0 94.518 0.038 ;
    END
    PORT
      LAYER M3 ;
        RECT  94.5 0.012 94.518 1.723 ;
    END
  END rsp_lo[20]
  PIN rsp_lo[21]
    DIRECTION INPUT ;
    USE SIGNAL ;
    PORT
      LAYER M5 ;
        RECT  95.472 0 95.496 0.084 ;
    END
    PORT
      LAYER M5 ;
        RECT  95.472 0.016 95.496 1.763 ;
    END
  END rsp_lo[21]
  PIN rsp_lo[22]
    DIRECTION INPUT ;
    USE SIGNAL ;
    PORT
      LAYER M3 ;
        RECT  96.408 0 96.426 0.038 ;
    END
    PORT
      LAYER M3 ;
        RECT  96.408 0.012 96.426 2.263 ;
    END
  END rsp_lo[22]
  PIN rsp_lo[23]
    DIRECTION INPUT ;
    USE SIGNAL ;
    PORT
      LAYER M5 ;
        RECT  97.392 0 97.416 0.084 ;
    END
    PORT
      LAYER M5 ;
        RECT  97.392 0.016 97.416 1.763 ;
    END
  END rsp_lo[23]
  PIN rsp_lo[24]
    DIRECTION INPUT ;
    USE SIGNAL ;
    PORT
      LAYER M3 ;
        RECT  98.352 0 98.37 0.038 ;
    END
    PORT
      LAYER M3 ;
        RECT  98.352 0.012 98.37 2.371 ;
    END
  END rsp_lo[24]
  PIN rsp_lo[25]
    DIRECTION INPUT ;
    USE SIGNAL ;
    PORT
      LAYER M5 ;
        RECT  99.312 0 99.336 0.084 ;
    END
    PORT
      LAYER M5 ;
        RECT  99.312 0.016 99.336 0.611 ;
    END
  END rsp_lo[25]
  PIN rsp_lo[26]
    DIRECTION INPUT ;
    USE SIGNAL ;
    PORT
      LAYER M3 ;
        RECT  100.296 0 100.314 0.038 ;
    END
    PORT
      LAYER M3 ;
        RECT  100.296 0.012 100.314 2.143 ;
    END
  END rsp_lo[26]
  PIN rsp_lo[27]
    DIRECTION INPUT ;
    USE SIGNAL ;
    PORT
      LAYER M5 ;
        RECT  101.28 0 101.304 0.084 ;
    END
    PORT
      LAYER M5 ;
        RECT  101.28 0.016 101.304 1.763 ;
    END
  END rsp_lo[27]
  PIN rsp_lo[28]
    DIRECTION INPUT ;
    USE SIGNAL ;
    PORT
      LAYER M3 ;
        RECT  102.24 0 102.258 0.038 ;
    END
    PORT
      LAYER M3 ;
        RECT  102.24 0.012 102.258 2.371 ;
    END
  END rsp_lo[28]
  PIN rsp_lo[29]
    DIRECTION INPUT ;
    USE SIGNAL ;
    PORT
      LAYER M5 ;
        RECT  103.2 0 103.224 0.084 ;
    END
    PORT
      LAYER M5 ;
        RECT  103.2 0.016 103.224 0.611 ;
    END
  END rsp_lo[29]
  PIN rsp_lo[2]
    DIRECTION INPUT ;
    USE SIGNAL ;
    PORT
      LAYER M3 ;
        RECT  77.04 0 77.058 0.038 ;
    END
    PORT
      LAYER M3 ;
        RECT  77.04 0.012 77.058 2.371 ;
    END
  END rsp_lo[2]
  PIN rsp_lo[30]
    DIRECTION INPUT ;
    USE SIGNAL ;
    PORT
      LAYER M3 ;
        RECT  104.184 0 104.202 0.038 ;
    END
    PORT
      LAYER M3 ;
        RECT  104.184 0.012 104.202 1.723 ;
    END
  END rsp_lo[30]
  PIN rsp_lo[31]
    DIRECTION INPUT ;
    USE SIGNAL ;
    PORT
      LAYER M5 ;
        RECT  105.12 0 105.144 0.084 ;
    END
    PORT
      LAYER M5 ;
        RECT  105.12 0.016 105.144 2.137 ;
    END
  END rsp_lo[31]
  PIN rsp_lo[32]
    DIRECTION INPUT ;
    USE SIGNAL ;
    PORT
      LAYER M3 ;
        RECT  106.092 0 106.11 0.038 ;
    END
    PORT
      LAYER M3 ;
        RECT  106.092 0.012 106.11 2.191 ;
    END
  END rsp_lo[32]
  PIN rsp_lo[33]
    DIRECTION INPUT ;
    USE SIGNAL ;
    PORT
      LAYER M5 ;
        RECT  107.088 0 107.112 0.084 ;
    END
    PORT
      LAYER M5 ;
        RECT  107.088 0.016 107.112 1.763 ;
    END
  END rsp_lo[33]
  PIN rsp_lo[34]
    DIRECTION INPUT ;
    USE SIGNAL ;
    PORT
      LAYER M3 ;
        RECT  108.036 0 108.054 0.038 ;
    END
    PORT
      LAYER M3 ;
        RECT  108.036 0.012 108.054 2.371 ;
    END
  END rsp_lo[34]
  PIN rsp_lo[35]
    DIRECTION INPUT ;
    USE SIGNAL ;
    PORT
      LAYER M5 ;
        RECT  109.008 0 109.032 0.084 ;
    END
    PORT
      LAYER M5 ;
        RECT  109.008 0.016 109.032 0.611 ;
    END
  END rsp_lo[35]
  PIN rsp_lo[36]
    DIRECTION INPUT ;
    USE SIGNAL ;
    PORT
      LAYER M3 ;
        RECT  109.98 0 109.998 0.038 ;
    END
    PORT
      LAYER M3 ;
        RECT  109.98 0.012 109.998 1.723 ;
    END
  END rsp_lo[36]
  PIN rsp_lo[37]
    DIRECTION INPUT ;
    USE SIGNAL ;
    PORT
      LAYER M5 ;
        RECT  110.928 0 110.952 0.084 ;
    END
    PORT
      LAYER M5 ;
        RECT  110.928 0.016 110.952 1.763 ;
    END
  END rsp_lo[37]
  PIN rsp_lo[38]
    DIRECTION INPUT ;
    USE SIGNAL ;
    PORT
      LAYER M3 ;
        RECT  111.924 0 111.942 0.038 ;
    END
    PORT
      LAYER M3 ;
        RECT  111.924 0.012 111.942 2.371 ;
    END
  END rsp_lo[38]
  PIN rsp_lo[39]
    DIRECTION INPUT ;
    USE SIGNAL ;
    PORT
      LAYER M5 ;
        RECT  112.896 0 112.92 0.084 ;
    END
    PORT
      LAYER M5 ;
        RECT  112.896 0.016 112.92 0.611 ;
    END
  END rsp_lo[39]
  PIN rsp_lo[3]
    DIRECTION INPUT ;
    USE SIGNAL ;
    PORT
      LAYER M5 ;
        RECT  78 0 78.024 0.084 ;
    END
    PORT
      LAYER M5 ;
        RECT  78 0.016 78.024 2.137 ;
    END
  END rsp_lo[3]
  PIN rsp_lo[40]
    DIRECTION INPUT ;
    USE SIGNAL ;
    PORT
      LAYER M3 ;
        RECT  113.868 0 113.886 0.038 ;
    END
    PORT
      LAYER M3 ;
        RECT  113.868 0.012 113.886 2.371 ;
    END
  END rsp_lo[40]
  PIN rsp_lo[41]
    DIRECTION INPUT ;
    USE SIGNAL ;
    PORT
      LAYER M5 ;
        RECT  114.816 0 114.84 0.084 ;
    END
    PORT
      LAYER M5 ;
        RECT  114.816 0.016 114.84 0.611 ;
    END
  END rsp_lo[41]
  PIN rsp_lo[42]
    DIRECTION INPUT ;
    USE SIGNAL ;
    PORT
      LAYER M3 ;
        RECT  115.812 0 115.83 0.038 ;
    END
    PORT
      LAYER M3 ;
        RECT  115.812 0.012 115.83 1.723 ;
    END
  END rsp_lo[42]
  PIN rsp_lo[43]
    DIRECTION INPUT ;
    USE SIGNAL ;
    PORT
      LAYER M5 ;
        RECT  116.784 0 116.808 0.084 ;
    END
    PORT
      LAYER M5 ;
        RECT  116.784 0.016 116.808 1.763 ;
    END
  END rsp_lo[43]
  PIN rsp_lo[44]
    DIRECTION INPUT ;
    USE SIGNAL ;
    PORT
      LAYER M3 ;
        RECT  117.72 0 117.738 0.038 ;
    END
    PORT
      LAYER M3 ;
        RECT  117.72 0.012 117.738 2.291 ;
    END
  END rsp_lo[44]
  PIN rsp_lo[45]
    DIRECTION INPUT ;
    USE SIGNAL ;
    PORT
      LAYER M5 ;
        RECT  118.704 0 118.728 0.084 ;
    END
    PORT
      LAYER M5 ;
        RECT  118.704 0.016 118.728 0.611 ;
    END
  END rsp_lo[45]
  PIN rsp_lo[46]
    DIRECTION INPUT ;
    USE SIGNAL ;
    PORT
      LAYER M3 ;
        RECT  119.664 0 119.682 0.038 ;
    END
    PORT
      LAYER M3 ;
        RECT  119.664 0.012 119.682 1.723 ;
    END
  END rsp_lo[46]
  PIN rsp_lo[47]
    DIRECTION INPUT ;
    USE SIGNAL ;
    PORT
      LAYER M5 ;
        RECT  120.624 0 120.648 0.084 ;
    END
    PORT
      LAYER M5 ;
        RECT  120.624 0.016 120.648 1.763 ;
    END
  END rsp_lo[47]
  PIN rsp_lo[48]
    DIRECTION INPUT ;
    USE SIGNAL ;
    PORT
      LAYER M3 ;
        RECT  121.608 0 121.626 0.038 ;
    END
    PORT
      LAYER M3 ;
        RECT  121.608 0.012 121.626 2.101 ;
    END
  END rsp_lo[48]
  PIN rsp_lo[49]
    DIRECTION INPUT ;
    USE SIGNAL ;
    PORT
      LAYER M5 ;
        RECT  122.592 0 122.616 0.084 ;
    END
    PORT
      LAYER M5 ;
        RECT  122.592 0.016 122.616 0.611 ;
    END
  END rsp_lo[49]
  PIN rsp_lo[4]
    DIRECTION INPUT ;
    USE SIGNAL ;
    PORT
      LAYER M3 ;
        RECT  78.984 0 79.002 0.038 ;
    END
    PORT
      LAYER M3 ;
        RECT  78.984 0.012 79.002 2.191 ;
    END
  END rsp_lo[4]
  PIN rsp_lo[50]
    DIRECTION INPUT ;
    USE SIGNAL ;
    PORT
      LAYER M3 ;
        RECT  123.552 0 123.57 0.038 ;
    END
    PORT
      LAYER M3 ;
        RECT  123.552 0.012 123.57 1.723 ;
    END
  END rsp_lo[50]
  PIN rsp_lo[51]
    DIRECTION INPUT ;
    USE SIGNAL ;
    PORT
      LAYER M5 ;
        RECT  124.512 0 124.536 0.084 ;
    END
    PORT
      LAYER M5 ;
        RECT  124.512 0.016 124.536 1.763 ;
    END
  END rsp_lo[51]
  PIN rsp_lo[52]
    DIRECTION INPUT ;
    USE SIGNAL ;
    PORT
      LAYER M3 ;
        RECT  125.496 0 125.514 0.038 ;
    END
    PORT
      LAYER M3 ;
        RECT  125.496 0.012 125.514 1.723 ;
    END
  END rsp_lo[52]
  PIN rsp_lo[53]
    DIRECTION INPUT ;
    USE SIGNAL ;
    PORT
      LAYER M5 ;
        RECT  126.432 0 126.456 0.084 ;
    END
    PORT
      LAYER M5 ;
        RECT  126.432 0.016 126.456 1.763 ;
    END
  END rsp_lo[53]
  PIN rsp_lo[54]
    DIRECTION INPUT ;
    USE SIGNAL ;
    PORT
      LAYER M3 ;
        RECT  127.44 0 127.458 0.038 ;
    END
    PORT
      LAYER M3 ;
        RECT  127.44 0.012 127.458 2.371 ;
    END
  END rsp_lo[54]
  PIN rsp_lo[55]
    DIRECTION INPUT ;
    USE SIGNAL ;
    PORT
      LAYER M5 ;
        RECT  128.4 0 128.424 0.084 ;
    END
    PORT
      LAYER M5 ;
        RECT  128.4 0.016 128.424 0.611 ;
    END
  END rsp_lo[55]
  PIN rsp_lo[56]
    DIRECTION INPUT ;
    USE SIGNAL ;
    PORT
      LAYER M3 ;
        RECT  129.348 0 129.366 0.038 ;
    END
    PORT
      LAYER M3 ;
        RECT  129.348 0.012 129.366 1.723 ;
    END
  END rsp_lo[56]
  PIN rsp_lo[57]
    DIRECTION INPUT ;
    USE SIGNAL ;
    PORT
      LAYER M5 ;
        RECT  130.32 0 130.344 0.084 ;
    END
    PORT
      LAYER M5 ;
        RECT  130.32 0.016 130.344 1.763 ;
    END
  END rsp_lo[57]
  PIN rsp_lo[58]
    DIRECTION INPUT ;
    USE SIGNAL ;
    PORT
      LAYER M3 ;
        RECT  131.292 0 131.31 0.038 ;
    END
    PORT
      LAYER M3 ;
        RECT  131.292 0.012 131.31 2.143 ;
    END
  END rsp_lo[58]
  PIN rsp_lo[59]
    DIRECTION INPUT ;
    USE SIGNAL ;
    PORT
      LAYER M5 ;
        RECT  132.288 0 132.312 0.084 ;
    END
    PORT
      LAYER M5 ;
        RECT  132.288 0.016 132.312 0.611 ;
    END
  END rsp_lo[59]
  PIN rsp_lo[5]
    DIRECTION INPUT ;
    USE SIGNAL ;
    PORT
      LAYER M5 ;
        RECT  79.968 0 79.992 0.084 ;
    END
    PORT
      LAYER M5 ;
        RECT  79.968 0.016 79.992 0.611 ;
    END
  END rsp_lo[5]
  PIN rsp_lo[60]
    DIRECTION INPUT ;
    USE SIGNAL ;
    PORT
      LAYER M3 ;
        RECT  133.236 0 133.254 0.038 ;
    END
    PORT
      LAYER M3 ;
        RECT  133.236 0.012 133.254 2.371 ;
    END
  END rsp_lo[60]
  PIN rsp_lo[61]
    DIRECTION INPUT ;
    USE SIGNAL ;
    PORT
      LAYER M5 ;
        RECT  134.208 0 134.232 0.084 ;
    END
    PORT
      LAYER M5 ;
        RECT  134.208 0.016 134.232 1.763 ;
    END
  END rsp_lo[61]
  PIN rsp_lo[62]
    DIRECTION INPUT ;
    USE SIGNAL ;
    PORT
      LAYER M3 ;
        RECT  135.18 0 135.198 0.038 ;
    END
    PORT
      LAYER M3 ;
        RECT  135.18 0.012 135.198 1.723 ;
    END
  END rsp_lo[62]
  PIN rsp_lo[63]
    DIRECTION INPUT ;
    USE SIGNAL ;
    PORT
      LAYER M5 ;
        RECT  136.128 0 136.152 0.084 ;
    END
    PORT
      LAYER M5 ;
        RECT  136.128 0.016 136.152 1.763 ;
    END
  END rsp_lo[63]
  PIN rsp_lo[64]
    DIRECTION INPUT ;
    USE SIGNAL ;
    PORT
      LAYER M3 ;
        RECT  137.124 0 137.142 0.038 ;
    END
    PORT
      LAYER M3 ;
        RECT  137.124 0.012 137.142 2.143 ;
    END
  END rsp_lo[64]
  PIN rsp_lo[65]
    DIRECTION INPUT ;
    USE SIGNAL ;
    PORT
      LAYER M5 ;
        RECT  138.096 0 138.12 0.084 ;
    END
    PORT
      LAYER M5 ;
        RECT  138.096 0.016 138.12 0.611 ;
    END
  END rsp_lo[65]
  PIN rsp_lo[66]
    DIRECTION INPUT ;
    USE SIGNAL ;
    PORT
      LAYER M3 ;
        RECT  139.032 0 139.05 0.038 ;
    END
    PORT
      LAYER M3 ;
        RECT  139.032 0.012 139.05 2.263 ;
    END
  END rsp_lo[66]
  PIN rsp_lo[67]
    DIRECTION INPUT ;
    USE SIGNAL ;
    PORT
      LAYER M5 ;
        RECT  140.016 0 140.04 0.084 ;
    END
    PORT
      LAYER M5 ;
        RECT  140.016 0.016 140.04 1.763 ;
    END
  END rsp_lo[67]
  PIN rsp_lo[68]
    DIRECTION INPUT ;
    USE SIGNAL ;
    PORT
      LAYER M3 ;
        RECT  140.976 0 140.994 0.038 ;
    END
    PORT
      LAYER M3 ;
        RECT  140.976 0.012 140.994 2.371 ;
    END
  END rsp_lo[68]
  PIN rsp_lo[69]
    DIRECTION INPUT ;
    USE SIGNAL ;
    PORT
      LAYER M5 ;
        RECT  141.936 0 141.96 0.084 ;
    END
    PORT
      LAYER M5 ;
        RECT  141.936 0.016 141.96 0.611 ;
    END
  END rsp_lo[69]
  PIN rsp_lo[6]
    DIRECTION INPUT ;
    USE SIGNAL ;
    PORT
      LAYER M3 ;
        RECT  80.928 0 80.946 0.038 ;
    END
    PORT
      LAYER M3 ;
        RECT  80.928 0.012 80.946 2.191 ;
    END
  END rsp_lo[6]
  PIN rsp_lo[70]
    DIRECTION INPUT ;
    USE SIGNAL ;
    PORT
      LAYER M3 ;
        RECT  142.92 0 142.938 0.038 ;
    END
    PORT
      LAYER M3 ;
        RECT  142.92 0.012 142.938 1.723 ;
    END
  END rsp_lo[70]
  PIN rsp_lo[71]
    DIRECTION INPUT ;
    USE SIGNAL ;
    PORT
      LAYER M5 ;
        RECT  143.904 0 143.928 0.084 ;
    END
    PORT
      LAYER M5 ;
        RECT  143.904 0.016 143.928 1.763 ;
    END
  END rsp_lo[71]
  PIN rsp_lo[72]
    DIRECTION INPUT ;
    USE SIGNAL ;
    PORT
      LAYER M3 ;
        RECT  144.864 0 144.882 0.038 ;
    END
    PORT
      LAYER M3 ;
        RECT  144.864 0.012 144.882 2.371 ;
    END
  END rsp_lo[72]
  PIN rsp_lo[73]
    DIRECTION INPUT ;
    USE SIGNAL ;
    PORT
      LAYER M5 ;
        RECT  145.824 0 145.848 0.084 ;
    END
    PORT
      LAYER M5 ;
        RECT  145.824 0.016 145.848 1.763 ;
    END
  END rsp_lo[73]
  PIN rsp_lo[74]
    DIRECTION INPUT ;
    USE SIGNAL ;
    PORT
      LAYER M3 ;
        RECT  146.808 0 146.826 0.038 ;
    END
    PORT
      LAYER M3 ;
        RECT  146.808 0.012 146.826 1.723 ;
    END
  END rsp_lo[74]
  PIN rsp_lo[75]
    DIRECTION INPUT ;
    USE SIGNAL ;
    PORT
      LAYER M5 ;
        RECT  147.744 0 147.768 0.084 ;
    END
    PORT
      LAYER M5 ;
        RECT  147.744 0.016 147.768 0.611 ;
    END
  END rsp_lo[75]
  PIN rsp_lo[76]
    DIRECTION INPUT ;
    USE SIGNAL ;
    PORT
      LAYER M3 ;
        RECT  148.752 0 148.77 0.038 ;
    END
    PORT
      LAYER M3 ;
        RECT  148.752 0.012 148.77 2.143 ;
    END
  END rsp_lo[76]
  PIN rsp_lo[77]
    DIRECTION INPUT ;
    USE SIGNAL ;
    PORT
      LAYER M5 ;
        RECT  149.712 0 149.736 0.084 ;
    END
    PORT
      LAYER M5 ;
        RECT  149.712 0.016 149.736 2.291 ;
    END
  END rsp_lo[77]
  PIN rsp_lo[7]
    DIRECTION INPUT ;
    USE SIGNAL ;
    PORT
      LAYER M5 ;
        RECT  81.888 0 81.912 0.084 ;
    END
    PORT
      LAYER M5 ;
        RECT  81.888 0.016 81.912 1.763 ;
    END
  END rsp_lo[7]
  PIN rsp_lo[8]
    DIRECTION INPUT ;
    USE SIGNAL ;
    PORT
      LAYER M3 ;
        RECT  82.872 0 82.89 0.038 ;
    END
    PORT
      LAYER M3 ;
        RECT  82.872 0.012 82.89 2.143 ;
    END
  END rsp_lo[8]
  PIN rsp_lo[9]
    DIRECTION INPUT ;
    USE SIGNAL ;
    PORT
      LAYER M5 ;
        RECT  83.808 0 83.832 0.084 ;
    END
    PORT
      LAYER M5 ;
        RECT  83.808 0.016 83.832 0.611 ;
    END
  END rsp_lo[9]
  PIN rsp_t[0]
    DIRECTION OUTPUT ;
    USE SIGNAL ;
    PORT
      LAYER M4 ;
        RECT  0 16.8 0.084 16.824 ;
    END
  END rsp_t[0]
  PIN rsp_t[10]
    DIRECTION OUTPUT ;
    USE SIGNAL ;
    PORT
      LAYER M4 ;
        RECT  0 19.392 0.084 19.416 ;
    END
  END rsp_t[10]
  PIN rsp_t[11]
    DIRECTION OUTPUT ;
    USE SIGNAL ;
    PORT
      LAYER M4 ;
        RECT  0 19.632 0.084 19.656 ;
    END
  END rsp_t[11]
  PIN rsp_t[12]
    DIRECTION OUTPUT ;
    USE SIGNAL ;
    PORT
      LAYER M4 ;
        RECT  0 19.872 0.084 19.896 ;
    END
  END rsp_t[12]
  PIN rsp_t[13]
    DIRECTION OUTPUT ;
    USE SIGNAL ;
    PORT
      LAYER M4 ;
        RECT  0 20.16 0.084 20.184 ;
    END
  END rsp_t[13]
  PIN rsp_t[1]
    DIRECTION OUTPUT ;
    USE SIGNAL ;
    PORT
      LAYER M4 ;
        RECT  0 17.04 0.084 17.064 ;
    END
  END rsp_t[1]
  PIN rsp_t[2]
    DIRECTION OUTPUT ;
    USE SIGNAL ;
    PORT
      LAYER M4 ;
        RECT  0 17.328 0.084 17.352 ;
    END
  END rsp_t[2]
  PIN rsp_t[3]
    DIRECTION OUTPUT ;
    USE SIGNAL ;
    PORT
      LAYER M4 ;
        RECT  0 17.568 0.084 17.592 ;
    END
  END rsp_t[3]
  PIN rsp_t[4]
    DIRECTION OUTPUT ;
    USE SIGNAL ;
    PORT
      LAYER M4 ;
        RECT  0 17.856 0.084 17.88 ;
    END
  END rsp_t[4]
  PIN rsp_t[5]
    DIRECTION OUTPUT ;
    USE SIGNAL ;
    PORT
      LAYER M4 ;
        RECT  0 18.096 0.084 18.12 ;
    END
  END rsp_t[5]
  PIN rsp_t[6]
    DIRECTION OUTPUT ;
    USE SIGNAL ;
    PORT
      LAYER M4 ;
        RECT  0 18.336 0.084 18.36 ;
    END
  END rsp_t[6]
  PIN rsp_t[7]
    DIRECTION OUTPUT ;
    USE SIGNAL ;
    PORT
      LAYER M4 ;
        RECT  0 18.624 0.084 18.648 ;
    END
  END rsp_t[7]
  PIN rsp_t[8]
    DIRECTION OUTPUT ;
    USE SIGNAL ;
    PORT
      LAYER M4 ;
        RECT  0 18.864 0.084 18.888 ;
    END
  END rsp_t[8]
  PIN rsp_t[9]
    DIRECTION OUTPUT ;
    USE SIGNAL ;
    PORT
      LAYER M4 ;
        RECT  0 19.104 0.084 19.128 ;
    END
  END rsp_t[9]
  PIN rsp_v
    DIRECTION OUTPUT ;
    USE SIGNAL ;
    PORT
      LAYER M4 ;
        RECT  0 20.4 0.084 20.424 ;
    END
  END rsp_v
  PIN rsp_valid
    DIRECTION OUTPUT ;
    USE SIGNAL ;
    PORT
      LAYER M4 ;
        RECT  0 20.688 0.084 20.712 ;
    END
  END rsp_valid
  PIN rst_n
    DIRECTION INPUT ;
    USE SIGNAL ;
    PORT
      LAYER M4 ;
        RECT  0 20.928 0.084 20.952 ;
    END
  END rst_n
  PIN vreq_t[0]
    DIRECTION INPUT ;
    USE SIGNAL ;
    PORT
      LAYER M4 ;
        RECT  0 21.168 0.084 21.192 ;
    END
  END vreq_t[0]
  PIN vreq_t[10]
    DIRECTION INPUT ;
    USE SIGNAL ;
    PORT
      LAYER M4 ;
        RECT  0 23.76 0.084 23.784 ;
    END
  END vreq_t[10]
  PIN vreq_t[11]
    DIRECTION INPUT ;
    USE SIGNAL ;
    PORT
      LAYER M4 ;
        RECT  0 24 0.084 24.024 ;
    END
  END vreq_t[11]
  PIN vreq_t[12]
    DIRECTION INPUT ;
    USE SIGNAL ;
    PORT
      LAYER M4 ;
        RECT  0 24.288 0.084 24.312 ;
    END
  END vreq_t[12]
  PIN vreq_t[13]
    DIRECTION INPUT ;
    USE SIGNAL ;
    PORT
      LAYER M4 ;
        RECT  0 24.528 0.084 24.552 ;
    END
  END vreq_t[13]
  PIN vreq_t[1]
    DIRECTION INPUT ;
    USE SIGNAL ;
    PORT
      LAYER M4 ;
        RECT  0 21.456 0.084 21.48 ;
    END
  END vreq_t[1]
  PIN vreq_t[2]
    DIRECTION INPUT ;
    USE SIGNAL ;
    PORT
      LAYER M4 ;
        RECT  0 21.696 0.084 21.72 ;
    END
  END vreq_t[2]
  PIN vreq_t[3]
    DIRECTION INPUT ;
    USE SIGNAL ;
    PORT
      LAYER M4 ;
        RECT  0 21.936 0.084 21.96 ;
    END
  END vreq_t[3]
  PIN vreq_t[4]
    DIRECTION INPUT ;
    USE SIGNAL ;
    PORT
      LAYER M4 ;
        RECT  0 22.224 0.084 22.248 ;
    END
  END vreq_t[4]
  PIN vreq_t[5]
    DIRECTION INPUT ;
    USE SIGNAL ;
    PORT
      LAYER M4 ;
        RECT  0 22.464 0.084 22.488 ;
    END
  END vreq_t[5]
  PIN vreq_t[6]
    DIRECTION INPUT ;
    USE SIGNAL ;
    PORT
      LAYER M4 ;
        RECT  0 22.704 0.084 22.728 ;
    END
  END vreq_t[6]
  PIN vreq_t[7]
    DIRECTION INPUT ;
    USE SIGNAL ;
    PORT
      LAYER M4 ;
        RECT  0 22.992 0.084 23.016 ;
    END
  END vreq_t[7]
  PIN vreq_t[8]
    DIRECTION INPUT ;
    USE SIGNAL ;
    PORT
      LAYER M4 ;
        RECT  0 23.232 0.084 23.256 ;
    END
  END vreq_t[8]
  PIN vreq_t[9]
    DIRECTION INPUT ;
    USE SIGNAL ;
    PORT
      LAYER M4 ;
        RECT  0 23.472 0.084 23.496 ;
    END
  END vreq_t[9]
  PIN vreq_valid
    DIRECTION INPUT ;
    USE SIGNAL ;
    PORT
      LAYER M4 ;
        RECT  0 24.768 0.084 24.792 ;
    END
  END vreq_valid
  PIN VDD
    DIRECTION INOUT ;
    USE POWER ;
    PORT
      LAYER M5 ;
        RECT  148.392 2.151 148.512 23.769 ;
        RECT  142.992 2.151 143.112 23.769 ;
        RECT  137.592 2.151 137.712 23.769 ;
        RECT  132.192 2.151 132.312 23.769 ;
        RECT  126.792 2.151 126.912 23.769 ;
        RECT  121.392 2.151 121.512 23.769 ;
        RECT  115.992 2.151 116.112 23.769 ;
        RECT  110.592 2.151 110.712 23.769 ;
        RECT  105.192 2.151 105.312 23.769 ;
        RECT  99.792 2.151 99.912 23.769 ;
        RECT  94.392 2.151 94.512 23.769 ;
        RECT  88.992 2.151 89.112 23.769 ;
        RECT  83.592 2.151 83.712 23.769 ;
        RECT  78.192 2.151 78.312 23.769 ;
        RECT  72.792 2.151 72.912 23.769 ;
        RECT  67.392 2.151 67.512 23.769 ;
        RECT  61.992 2.151 62.112 23.769 ;
        RECT  56.592 2.151 56.712 23.769 ;
        RECT  51.192 2.151 51.312 23.769 ;
        RECT  45.792 2.151 45.912 23.769 ;
        RECT  40.392 2.151 40.512 23.769 ;
        RECT  34.992 2.151 35.112 23.769 ;
        RECT  29.592 2.151 29.712 23.769 ;
        RECT  24.192 2.151 24.312 23.769 ;
        RECT  18.792 2.151 18.912 23.769 ;
        RECT  13.392 2.151 13.512 23.769 ;
        RECT  7.992 2.151 8.112 23.769 ;
        RECT  2.592 2.151 2.712 23.769 ;
    END
  END VDD
  PIN VSS
    DIRECTION INOUT ;
    USE GROUND ;
    PORT
      LAYER M5 ;
        RECT  148.2 2.137 148.32 23.783 ;
        RECT  142.8 2.137 142.92 23.783 ;
        RECT  137.4 2.137 137.52 23.783 ;
        RECT  132 2.137 132.12 23.783 ;
        RECT  126.6 2.137 126.72 23.783 ;
        RECT  121.2 2.137 121.32 23.783 ;
        RECT  115.8 2.137 115.92 23.783 ;
        RECT  110.4 2.137 110.52 23.783 ;
        RECT  105 2.137 105.12 23.783 ;
        RECT  99.6 2.137 99.72 23.783 ;
        RECT  94.2 2.137 94.32 23.783 ;
        RECT  88.8 2.137 88.92 23.783 ;
        RECT  83.4 2.137 83.52 23.783 ;
        RECT  78 2.137 78.12 23.783 ;
        RECT  72.6 2.137 72.72 23.783 ;
        RECT  67.2 2.137 67.32 23.783 ;
        RECT  61.8 2.137 61.92 23.783 ;
        RECT  56.4 2.137 56.52 23.783 ;
        RECT  51 2.137 51.12 23.783 ;
        RECT  45.6 2.137 45.72 23.783 ;
        RECT  40.2 2.137 40.32 23.783 ;
        RECT  34.8 2.137 34.92 23.783 ;
        RECT  29.4 2.137 29.52 23.783 ;
        RECT  24 2.137 24.12 23.783 ;
        RECT  18.6 2.137 18.72 23.783 ;
        RECT  13.2 2.137 13.32 23.783 ;
        RECT  7.8 2.137 7.92 23.783 ;
        RECT  2.4 2.137 2.52 23.783 ;
    END
  END VSS
  # OT_OBS_CLOSED layer=M5 d_um=1.536 added=46
  OBS
    LAYER RVTN ;
     RECT  2.16 2.16 149.04 2.295 ;
     RECT  2.16 2.565 149.04 2.835 ;
     RECT  2.16 3.105 149.04 3.375 ;
     RECT  2.16 3.645 149.04 3.915 ;
     RECT  2.16 4.185 149.04 4.455 ;
     RECT  2.16 4.725 149.04 4.995 ;
     RECT  2.16 5.265 149.04 5.535 ;
     RECT  2.16 5.805 149.04 6.075 ;
     RECT  2.16 6.345 149.04 6.615 ;
     RECT  2.16 6.885 149.04 7.155 ;
     RECT  2.16 7.425 149.04 7.695 ;
     RECT  2.16 7.965 149.04 8.235 ;
     RECT  2.16 8.505 149.04 8.775 ;
     RECT  2.16 9.045 149.04 9.315 ;
     RECT  2.16 9.585 149.04 9.855 ;
     RECT  2.16 10.125 149.04 10.395 ;
     RECT  2.16 10.665 149.04 10.935 ;
     RECT  2.16 11.205 149.04 11.475 ;
     RECT  2.16 11.745 149.04 12.015 ;
     RECT  2.16 12.285 149.04 12.555 ;
     RECT  2.16 12.825 149.04 13.095 ;
     RECT  2.16 13.365 149.04 13.635 ;
     RECT  2.16 13.905 149.04 14.175 ;
     RECT  2.16 14.445 149.04 14.715 ;
     RECT  2.16 14.985 149.04 15.255 ;
     RECT  2.16 15.525 149.04 15.795 ;
     RECT  2.16 16.065 149.04 16.335 ;
     RECT  2.16 16.605 149.04 16.875 ;
     RECT  2.16 17.145 149.04 17.415 ;
     RECT  2.16 17.685 149.04 17.955 ;
     RECT  2.16 18.225 149.04 18.495 ;
     RECT  2.16 18.765 149.04 19.035 ;
     RECT  2.16 19.305 149.04 19.575 ;
     RECT  2.16 19.845 149.04 20.115 ;
     RECT  2.16 20.385 149.04 20.655 ;
     RECT  2.16 20.925 149.04 21.195 ;
     RECT  2.16 21.465 149.04 21.735 ;
     RECT  2.16 22.005 149.04 22.275 ;
     RECT  2.16 22.545 149.04 22.815 ;
     RECT  2.16 23.085 149.04 23.355 ;
     RECT  2.16 23.625 149.04 23.76 ;
    LAYER RVTP ;
     RECT  2.16 2.295 149.04 2.565 ;
     RECT  2.16 2.835 149.04 3.105 ;
     RECT  2.16 3.375 149.04 3.645 ;
     RECT  2.16 3.915 149.04 4.185 ;
     RECT  2.16 4.455 149.04 4.725 ;
     RECT  2.16 4.995 149.04 5.265 ;
     RECT  2.16 5.535 149.04 5.805 ;
     RECT  2.16 6.075 149.04 6.345 ;
     RECT  2.16 6.615 149.04 6.885 ;
     RECT  2.16 7.155 149.04 7.425 ;
     RECT  2.16 7.695 149.04 7.965 ;
     RECT  2.16 8.235 149.04 8.505 ;
     RECT  2.16 8.775 149.04 9.045 ;
     RECT  2.16 9.315 149.04 9.585 ;
     RECT  2.16 9.855 149.04 10.125 ;
     RECT  2.16 10.395 149.04 10.665 ;
     RECT  2.16 10.935 149.04 11.205 ;
     RECT  2.16 11.475 149.04 11.745 ;
     RECT  2.16 12.015 149.04 12.285 ;
     RECT  2.16 12.555 149.04 12.825 ;
     RECT  2.16 13.095 149.04 13.365 ;
     RECT  2.16 13.635 149.04 13.905 ;
     RECT  2.16 14.175 149.04 14.445 ;
     RECT  2.16 14.715 149.04 14.985 ;
     RECT  2.16 15.255 149.04 15.525 ;
     RECT  2.16 15.795 149.04 16.065 ;
     RECT  2.16 16.335 149.04 16.605 ;
     RECT  2.16 16.875 149.04 17.145 ;
     RECT  2.16 17.415 149.04 17.685 ;
     RECT  2.16 17.955 149.04 18.225 ;
     RECT  2.16 18.495 149.04 18.765 ;
     RECT  2.16 19.035 149.04 19.305 ;
     RECT  2.16 19.575 149.04 19.845 ;
     RECT  2.16 20.115 149.04 20.385 ;
     RECT  2.16 20.655 149.04 20.925 ;
     RECT  2.16 21.195 149.04 21.465 ;
     RECT  2.16 21.735 149.04 22.005 ;
     RECT  2.16 22.275 149.04 22.545 ;
     RECT  2.16 22.815 149.04 23.085 ;
     RECT  2.16 23.355 149.04 23.625 ;
    LAYER M1 ;
     RECT  2.16 2.151 149.04 23.769 ;
    LAYER M2 ;
     RECT  1.147 23.256 1.687 23.346 ;
     RECT  1.471 3.276 2.16 3.294 ;
     RECT  0.103 10.296 2.16 10.314 ;
     RECT  0.535 11.214 2.16 11.97 ;
     RECT  0.103 12.798 2.16 12.816 ;
     RECT  0.535 18 2.16 18.018 ;
     RECT  1.147 21.204 2.16 21.222 ;
     RECT  0.103 22.212 2.16 22.23 ;
     RECT  1.687 23.058 2.16 23.346 ;
     RECT  2.16 2.151 2.299 23.769 ;
     RECT  2.299 2.034 3.335 23.769 ;
     RECT  3.415 0.036 3.515 0.054 ;
     RECT  3.335 2.106 4.523 23.769 ;
     RECT  4.523 2.151 5.863 23.769 ;
     RECT  5.863 2.106 6.611 23.769 ;
     RECT  13.099 0.036 13.199 0.054 ;
     RECT  22.639 25.866 22.739 25.884 ;
     RECT  6.611 2.151 34.951 23.769 ;
     RECT  34.951 2.106 35.375 23.769 ;
     RECT  35.375 2.151 37.651 23.769 ;
     RECT  37.651 2.106 38.363 23.769 ;
     RECT  40.135 0.036 40.235 0.054 ;
     RECT  41.827 25.866 41.927 25.884 ;
     RECT  43.735 25.866 43.835 25.884 ;
     RECT  45.751 25.866 45.959 25.884 ;
     RECT  72.571 25.866 72.743 25.884 ;
     RECT  38.363 2.151 74.695 23.769 ;
     RECT  74.695 2.106 75.515 23.769 ;
     RECT  75.515 2.151 99.427 23.769 ;
     RECT  99.427 2.151 99.671 23.922 ;
     RECT  99.671 2.151 115.735 23.769 ;
     RECT  115.735 1.728 115.835 23.769 ;
     RECT  115.835 2.151 122.323 23.769 ;
     RECT  122.323 2.106 122.603 23.769 ;
     RECT  122.603 2.151 126.535 23.769 ;
     RECT  126.535 2.151 126.635 23.85 ;
     RECT  126.635 2.151 129.127 23.769 ;
     RECT  129.127 1.728 129.371 23.769 ;
     RECT  129.371 2.151 142.699 23.769 ;
     RECT  142.699 1.728 142.943 23.769 ;
     RECT  142.943 2.151 146.587 23.769 ;
     RECT  146.587 1.728 146.831 23.769 ;
     RECT  146.831 2.151 149.04 23.769 ;
     RECT  149.04 9.9 149.243 9.918 ;
     RECT  149.04 19.35 149.243 19.368 ;
     RECT  149.04 4.698 149.315 4.716 ;
     RECT  149.04 13.068 149.315 13.086 ;
     RECT  149.04 18.198 149.315 18.216 ;
     RECT  149.04 6.696 149.387 6.714 ;
     RECT  149.04 20.16 149.387 20.178 ;
     RECT  149.04 21.24 149.387 21.258 ;
     RECT  149.04 10.98 149.423 10.998 ;
     RECT  149.04 5.85 149.531 5.868 ;
     RECT  149.04 2.268 149.567 3.708 ;
     RECT  149.567 2.268 149.711 3.096 ;
     RECT  149.711 2.268 149.891 2.826 ;
     RECT  149.04 7.74 149.891 7.758 ;
     RECT  149.04 8.82 149.891 8.838 ;
     RECT  149.04 11.952 149.891 11.97 ;
     RECT  149.04 14.148 149.891 14.166 ;
     RECT  149.04 15.03 149.891 15.048 ;
     RECT  149.04 16.11 149.891 16.128 ;
     RECT  149.04 17.082 149.891 17.1 ;
     RECT  149.04 23.13 149.891 23.346 ;
     RECT  149.04 22.212 149.927 22.23 ;
     RECT  149.891 23.13 149.927 23.148 ;
    LAYER M3 ;
     RECT  3.492 0.059 3.51 1.099 ;
     RECT  2.772 1.099 3.51 1.387 ;
     RECT  2.34 1.387 3.51 1.867 ;
     RECT  4.536 1.723 4.554 2.101 ;
     RECT  6.336 1.723 6.354 2.101 ;
     RECT  35.82 1.723 36.378 2.101 ;
     RECT  37.26 0.091 37.278 2.101 ;
     RECT  74.088 0.091 74.106 2.101 ;
     RECT  75.852 1.723 75.87 2.101 ;
     RECT  122.58 0.571 122.598 2.101 ;
     RECT  5.364 2.101 7.29 2.143 ;
     RECT  8.208 0.091 8.226 2.143 ;
     RECT  13.176 0.059 13.194 2.143 ;
     RECT  17.928 0.091 17.946 2.143 ;
     RECT  23.724 0.091 23.742 2.143 ;
     RECT  29.556 0.091 29.574 2.143 ;
     RECT  40.14 0.059 40.158 2.143 ;
     RECT  45 0.091 45.018 2.143 ;
     RECT  50.832 0.091 50.85 2.143 ;
     RECT  56.556 0.523 56.574 2.143 ;
     RECT  62.496 0.091 62.514 2.143 ;
     RECT  72.144 0.091 72.162 2.143 ;
     RECT  77.796 1.723 77.814 2.143 ;
     RECT  83.808 0.571 83.826 2.143 ;
     RECT  89.604 0.571 89.622 2.143 ;
     RECT  93.492 0.571 93.51 2.143 ;
     RECT  94.5 1.723 95.238 2.143 ;
     RECT  99.18 0.571 99.198 2.143 ;
     RECT  104.184 1.723 104.922 2.143 ;
     RECT  115.74 1.723 115.83 2.143 ;
     RECT  116.568 1.723 116.586 2.143 ;
     RECT  121.608 2.101 122.598 2.143 ;
     RECT  125.496 1.723 126.234 2.143 ;
     RECT  132.264 0.571 132.282 2.143 ;
     RECT  138.024 0.571 138.042 2.143 ;
     RECT  147.636 0.571 147.654 2.143 ;
     RECT  2.304 1.867 3.51 2.191 ;
     RECT  4.5 2.101 4.554 2.191 ;
     RECT  10.188 1.723 10.206 2.191 ;
     RECT  15.948 0.091 15.966 2.191 ;
     RECT  19.872 1.723 19.89 2.191 ;
     RECT  21.816 0.091 21.834 2.191 ;
     RECT  23.724 2.143 24.75 2.191 ;
     RECT  25.668 0.091 25.686 2.191 ;
     RECT  27.612 0.091 27.63 2.191 ;
     RECT  29.415 2.143 29.574 2.191 ;
     RECT  31.428 0.091 31.446 2.191 ;
     RECT  33.444 0.091 33.462 2.191 ;
     RECT  39.204 0.091 39.222 2.191 ;
     RECT  40.14 2.143 40.305 2.191 ;
     RECT  41.22 0.091 41.238 2.191 ;
     RECT  43.092 0.091 43.11 2.191 ;
     RECT  48.96 0.091 48.978 2.191 ;
     RECT  54.72 0.091 54.738 2.191 ;
     RECT  55.728 2.143 56.574 2.191 ;
     RECT  58.608 0.091 58.626 2.191 ;
     RECT  60.552 0.091 60.57 2.191 ;
     RECT  64.44 0.091 64.458 2.191 ;
     RECT  67.215 2.143 67.374 2.191 ;
     RECT  68.256 0.091 68.274 2.191 ;
     RECT  72.144 2.143 73.17 2.191 ;
     RECT  77.796 2.143 78.105 2.191 ;
     RECT  81.684 1.723 81.702 2.191 ;
     RECT  82.872 2.143 83.826 2.191 ;
     RECT  104.184 2.143 105.105 2.191 ;
     RECT  146.592 1.723 146.826 2.191 ;
     RECT  147.636 2.143 148.77 2.191 ;
     RECT  12.096 0.091 12.114 2.227 ;
     RECT  20.772 2.191 20.862 2.227 ;
     RECT  21.816 2.191 22.806 2.227 ;
     RECT  149.868 1.483 149.886 2.251 ;
     RECT  77.796 2.191 79.002 2.255 ;
     RECT  80.928 2.191 83.826 2.255 ;
     RECT  85.572 1.723 85.59 2.255 ;
     RECT  93.492 2.143 95.238 2.255 ;
     RECT  99.18 2.143 100.314 2.255 ;
     RECT  101.052 1.723 101.07 2.255 ;
     RECT  103.176 0.571 103.194 2.255 ;
     RECT  104.184 2.191 106.11 2.255 ;
     RECT  106.848 1.723 106.866 2.255 ;
     RECT  114.696 0.571 114.714 2.255 ;
     RECT  119.664 1.723 120.402 2.255 ;
     RECT  123.552 1.723 124.29 2.255 ;
     RECT  125.496 2.143 126.705 2.255 ;
     RECT  129.132 1.723 129.366 2.255 ;
     RECT  130.104 1.723 130.122 2.255 ;
     RECT  135.18 1.723 135.918 2.255 ;
     RECT  137.124 2.143 138.042 2.255 ;
     RECT  139.788 1.723 139.806 2.255 ;
     RECT  143.676 1.723 143.694 2.255 ;
     RECT  12.096 2.227 12.294 2.263 ;
     RECT  14.04 0.091 14.058 2.263 ;
     RECT  29.415 2.191 30.69 2.263 ;
     RECT  31.428 2.191 32.49 2.263 ;
     RECT  34.416 2.101 36.378 2.263 ;
     RECT  37.26 2.101 38.358 2.263 ;
     RECT  48.924 2.191 48.978 2.263 ;
     RECT  49.896 2.191 49.95 2.263 ;
     RECT  50.832 2.143 51.105 2.263 ;
     RECT  61.56 2.143 62.514 2.263 ;
     RECT  63.288 2.227 63.486 2.263 ;
     RECT  67.14 2.191 69.354 2.263 ;
     RECT  70.272 0.091 70.29 2.263 ;
     RECT  71.244 2.191 73.17 2.263 ;
     RECT  97.164 1.723 97.182 2.263 ;
     RECT  115.74 2.143 116.586 2.263 ;
     RECT  125.496 2.255 125.802 2.263 ;
     RECT  131.292 2.143 132.282 2.263 ;
     RECT  34.416 2.263 38.358 2.291 ;
     RECT  53.784 2.191 60.57 2.291 ;
     RECT  86.724 1.723 87.462 2.291 ;
     RECT  90.612 1.723 91.35 2.291 ;
     RECT  93.492 2.255 94.806 2.291 ;
     RECT  95.868 2.263 97.182 2.291 ;
     RECT  99.504 2.255 100.314 2.291 ;
     RECT  112.896 0.571 112.914 2.291 ;
     RECT  119.664 2.255 119.898 2.291 ;
     RECT  124.92 2.263 125.802 2.291 ;
     RECT  137.124 2.255 137.697 2.291 ;
     RECT  17.928 2.143 18.918 2.299 ;
     RECT  61.56 2.263 63.486 2.299 ;
     RECT  2.304 2.191 4.626 2.335 ;
     RECT  5.364 2.143 8.226 2.335 ;
     RECT  9.18 2.191 11.178 2.335 ;
     RECT  13.176 2.143 13.305 2.335 ;
     RECT  14.04 2.263 14.31 2.335 ;
     RECT  15.048 2.191 15.966 2.335 ;
     RECT  17.928 2.299 18.99 2.335 ;
     RECT  19.872 2.191 19.962 2.335 ;
     RECT  20.772 2.227 22.806 2.335 ;
     RECT  23.724 2.191 26.694 2.335 ;
     RECT  27.612 2.191 28.638 2.335 ;
     RECT  29.415 2.263 32.49 2.335 ;
     RECT  33.444 2.191 33.606 2.335 ;
     RECT  38.196 2.291 38.358 2.335 ;
     RECT  39.132 2.191 40.305 2.335 ;
     RECT  45 2.143 46.062 2.335 ;
     RECT  46.944 0.091 46.962 2.335 ;
     RECT  48.924 2.263 49.95 2.335 ;
     RECT  61.56 2.299 63.666 2.335 ;
     RECT  64.44 2.191 65.43 2.335 ;
     RECT  66.384 0.091 66.402 2.335 ;
     RECT  2.304 2.335 11.178 2.371 ;
     RECT  11.916 2.263 12.294 2.371 ;
     RECT  13.104 2.335 13.305 2.371 ;
     RECT  14.04 2.335 15.966 2.371 ;
     RECT  16.992 2.263 17.118 2.371 ;
     RECT  17.928 2.335 19.962 2.371 ;
     RECT  20.772 2.335 28.638 2.371 ;
     RECT  29.415 2.335 33.606 2.371 ;
     RECT  34.416 2.291 37.278 2.371 ;
     RECT  38.196 2.335 40.338 2.371 ;
     RECT  41.22 2.191 41.418 2.371 ;
     RECT  42.156 2.191 43.11 2.371 ;
     RECT  44.1 2.335 46.962 2.371 ;
     RECT  47.988 2.335 49.95 2.371 ;
     RECT  50.688 2.263 51.105 2.371 ;
     RECT  52.776 0.091 52.794 2.371 ;
     RECT  53.784 2.291 53.982 2.371 ;
     RECT  58.608 2.291 60.57 2.371 ;
     RECT  61.308 2.335 63.666 2.371 ;
     RECT  64.44 2.335 66.402 2.371 ;
     RECT  67.14 2.263 73.17 2.371 ;
     RECT  74.088 2.101 75.87 2.371 ;
     RECT  79.956 0.571 79.974 2.371 ;
     RECT  87.012 2.291 87.462 2.371 ;
     RECT  88.668 2.143 89.622 2.371 ;
     RECT  90.9 2.291 91.35 2.371 ;
     RECT  96.84 2.291 97.182 2.371 ;
     RECT  104.184 2.255 105.75 2.371 ;
     RECT  109.008 0.571 109.026 2.371 ;
     RECT  109.98 1.723 110.682 2.371 ;
     RECT  115.2 2.263 116.586 2.371 ;
     RECT  118.692 0.571 118.71 2.371 ;
     RECT  121.215 2.143 122.598 2.371 ;
     RECT  123.552 2.255 123.822 2.371 ;
     RECT  126.615 2.255 126.705 2.371 ;
     RECT  128.376 0.571 128.394 2.371 ;
     RECT  131.292 2.263 132.354 2.371 ;
     RECT  133.992 1.723 134.01 2.371 ;
     RECT  135.18 2.255 135.486 2.371 ;
     RECT  141.948 0.571 141.966 2.371 ;
     RECT  145.62 1.723 145.638 2.371 ;
     RECT  146.592 2.191 148.77 2.371 ;
     RECT  142.704 1.723 142.938 2.413 ;
     RECT  2.304 2.371 12.294 2.461 ;
     RECT  16.992 2.371 19.998 2.461 ;
     RECT  20.772 2.371 37.278 2.461 ;
     RECT  2.304 2.461 12.366 2.489 ;
     RECT  13.104 2.371 16.11 2.489 ;
     RECT  16.884 2.461 37.278 2.489 ;
     RECT  43.884 2.371 53.982 2.489 ;
     RECT  54.72 2.291 56.898 2.489 ;
     RECT  58.608 2.371 63.666 2.489 ;
     RECT  64.404 2.371 66.402 2.489 ;
     RECT  67.14 2.371 76.014 2.489 ;
     RECT  76.968 2.371 77.058 2.489 ;
     RECT  79.884 2.371 79.974 2.489 ;
     RECT  81.504 2.255 83.826 2.489 ;
     RECT  88.596 2.371 89.622 2.489 ;
     RECT  90.9 2.371 91.53 2.489 ;
     RECT  101.664 2.371 102.33 2.489 ;
     RECT  107.964 2.371 108.054 2.489 ;
     RECT  113.22 2.371 113.886 2.489 ;
     RECT  115.2 2.371 116.802 2.489 ;
     RECT  120.924 2.371 122.598 2.489 ;
     RECT  128.34 2.371 128.394 2.489 ;
     RECT  129.42 2.263 129.69 2.489 ;
     RECT  133.2 2.371 133.254 2.489 ;
     RECT  133.992 2.371 134.19 2.489 ;
     RECT  135.144 2.371 135.486 2.489 ;
     RECT  140.328 2.371 140.994 2.489 ;
     RECT  141.876 2.371 141.966 2.489 ;
     RECT  2.304 2.489 10.962 2.525 ;
     RECT  13.104 2.489 14.274 2.525 ;
     RECT  15.156 2.489 16.038 2.525 ;
     RECT  19.728 2.489 37.278 2.525 ;
     RECT  43.884 2.489 43.902 2.525 ;
     RECT  47.232 2.489 50.274 2.525 ;
     RECT  64.404 2.489 65.214 2.525 ;
     RECT  66.168 2.489 66.402 2.525 ;
     RECT  67.14 2.489 73.386 2.525 ;
     RECT  64.404 2.525 64.926 2.561 ;
     RECT  11.736 2.489 12.366 2.569 ;
     RECT  13.104 2.525 13.497 2.569 ;
     RECT  61.776 2.489 63.666 2.569 ;
     RECT  16.884 2.489 18.954 2.597 ;
     RECT  51.015 2.489 53.982 2.597 ;
     RECT  57.672 2.291 57.87 2.597 ;
     RECT  38.196 2.371 43.11 2.605 ;
     RECT  2.304 2.525 10.926 2.633 ;
     RECT  44.856 2.489 46.206 2.633 ;
     RECT  74.124 2.489 76.014 2.633 ;
     RECT  2.304 2.633 9.99 2.635 ;
     RECT  123.48 2.371 123.822 2.635 ;
     RECT  67.14 2.525 68.562 2.641 ;
     RECT  74.808 2.633 76.014 2.641 ;
     RECT  78.015 2.255 79.002 2.641 ;
     RECT  83.415 2.489 83.826 2.641 ;
     RECT  87.012 2.371 87.642 2.641 ;
     RECT  88.596 2.489 89.097 2.641 ;
     RECT  96.84 2.371 97.362 2.641 ;
     RECT  98.316 2.371 98.37 2.641 ;
     RECT  106.992 2.371 107.01 2.641 ;
     RECT  108.936 2.371 109.026 2.641 ;
     RECT  109.764 2.371 111.942 2.641 ;
     RECT  118.008 2.371 118.71 2.641 ;
     RECT  126.615 2.371 127.458 2.641 ;
     RECT  130.644 2.371 132.354 2.641 ;
     RECT  138.528 2.263 139.05 2.641 ;
     RECT  142.704 2.413 143.19 2.641 ;
     RECT  144.18 2.371 148.77 2.641 ;
     RECT  61.776 2.569 64.098 2.669 ;
     RECT  70.704 2.525 73.386 2.669 ;
     RECT  11.736 2.569 13.497 2.759 ;
     RECT  15.156 2.525 15.246 2.759 ;
     RECT  16.884 2.597 16.902 2.759 ;
     RECT  27.972 2.525 37.278 2.759 ;
     RECT  38.196 2.605 43.182 2.759 ;
     RECT  64.836 2.561 64.926 2.759 ;
     RECT  10.908 2.633 10.926 2.795 ;
     RECT  19.728 2.525 20.97 2.795 ;
     RECT  39.024 2.759 41.202 2.795 ;
     RECT  149.688 2.251 149.886 2.831 ;
     RECT  74.808 2.641 76.446 2.861 ;
     RECT  54.936 2.489 56.898 2.867 ;
     RECT  96.84 2.641 98.658 3.001 ;
     RECT  106.992 2.641 107.298 3.001 ;
     RECT  114.048 2.641 114.138 3.001 ;
     RECT  33.588 2.759 37.278 3.005 ;
     RECT  114.048 3.001 114.282 3.019 ;
     RECT  115.2 2.489 116.097 3.019 ;
     RECT  118.008 2.641 118.746 3.019 ;
     RECT  19.728 2.795 20.862 3.029 ;
     RECT  87.012 2.641 89.097 3.029 ;
     RECT  114.048 3.019 114.354 3.037 ;
     RECT  115.128 3.019 116.097 3.037 ;
     RECT  0.108 2.923 0.126 3.053 ;
     RECT  2.268 2.635 9.99 3.065 ;
     RECT  61.815 2.669 64.098 3.065 ;
     RECT  125.784 2.291 125.802 3.073 ;
     RECT  126.615 2.641 127.71 3.073 ;
     RECT  27.972 2.759 32.814 3.101 ;
     RECT  149.688 2.831 149.706 3.101 ;
     RECT  102.492 2.641 102.654 3.109 ;
     RECT  103.5 2.371 105.75 3.109 ;
     RECT  106.596 3.001 107.298 3.109 ;
     RECT  129.672 2.489 129.69 3.109 ;
     RECT  117.936 3.019 118.746 3.115 ;
     RECT  102.492 3.109 107.298 3.137 ;
     RECT  83.415 2.641 84.006 3.145 ;
     RECT  100.62 2.371 100.638 3.145 ;
     RECT  33.624 3.005 37.278 3.181 ;
     RECT  38.196 2.759 38.286 3.181 ;
     RECT  53.964 2.597 53.982 3.181 ;
     RECT  93.816 2.291 94.806 3.181 ;
     RECT  95.868 2.291 95.886 3.181 ;
     RECT  96.84 3.001 98.766 3.181 ;
     RECT  99.504 2.291 99.897 3.181 ;
     RECT  100.62 3.145 100.854 3.181 ;
     RECT  102.492 3.137 106.254 3.209 ;
     RECT  22.068 2.525 27.126 3.271 ;
     RECT  59.256 2.489 60.786 3.271 ;
     RECT  86.04 2.371 86.058 3.271 ;
     RECT  86.796 3.145 86.814 3.271 ;
     RECT  92.916 2.371 92.934 3.271 ;
     RECT  101.664 2.489 101.682 3.271 ;
     RECT  102.492 3.209 106.182 3.271 ;
     RECT  107.064 3.137 107.298 3.271 ;
     RECT  113.22 2.489 113.238 3.271 ;
     RECT  114.048 3.037 116.097 3.271 ;
     RECT  122.832 2.635 123.822 3.271 ;
     RECT  125.784 3.073 127.71 3.271 ;
     RECT  135.468 2.489 135.486 3.271 ;
     RECT  136.44 2.371 136.458 3.271 ;
     RECT  140.328 2.489 140.346 3.271 ;
     RECT  78.015 2.641 79.326 3.299 ;
     RECT  87.768 3.029 89.097 3.299 ;
     RECT  93.816 3.181 94.95 3.299 ;
     RECT  95.868 3.181 100.854 3.299 ;
     RECT  101.664 3.271 106.182 3.299 ;
     RECT  120.924 2.489 121.986 3.299 ;
     RECT  125.784 3.271 127.818 3.299 ;
     RECT  129.672 3.109 129.906 3.299 ;
     RECT  141.228 2.641 141.462 3.299 ;
     RECT  144.18 2.641 148.806 3.299 ;
     RECT  77.256 2.641 77.274 3.301 ;
     RECT  78.015 3.299 79.002 3.301 ;
     RECT  95.868 3.299 98.658 3.335 ;
     RECT  77.256 3.301 79.002 3.341 ;
     RECT  87.768 3.299 87.822 3.341 ;
     RECT  78.015 3.341 79.002 3.344 ;
     RECT  133.524 2.641 133.65 3.355 ;
     RECT  134.532 2.641 134.658 3.355 ;
     RECT  137.415 2.291 137.697 3.355 ;
     RECT  138.528 2.641 139.302 3.355 ;
     RECT  20.52 3.029 20.862 3.371 ;
     RECT  14.256 2.525 14.274 3.379 ;
     RECT  52.524 2.597 53.154 3.379 ;
     RECT  53.964 3.181 54.162 3.379 ;
     RECT  69.516 2.525 69.534 3.379 ;
     RECT  91.764 2.641 91.782 3.379 ;
     RECT  108.288 2.641 112.194 3.379 ;
     RECT  117.108 2.641 117.126 3.379 ;
     RECT  117.936 3.115 118.782 3.379 ;
     RECT  119.88 2.291 119.898 3.379 ;
     RECT  120.924 3.299 121.698 3.379 ;
     RECT  122.832 3.271 123.93 3.379 ;
     RECT  124.92 2.291 124.938 3.379 ;
     RECT  130.644 2.641 132.57 3.379 ;
     RECT  133.524 3.355 134.658 3.379 ;
     RECT  136.44 3.271 136.566 3.379 ;
     RECT  137.415 3.355 139.302 3.379 ;
     RECT  142.2 2.641 143.19 3.379 ;
     RECT  0.144 3.163 0.162 3.389 ;
     RECT  18 2.597 18.954 3.403 ;
     RECT  19.728 3.029 19.746 3.403 ;
     RECT  21.78 3.271 27.126 3.403 ;
     RECT  27.972 3.101 32.526 3.403 ;
     RECT  83.415 3.145 84.186 3.403 ;
     RECT  85.068 2.371 85.086 3.403 ;
     RECT  86.04 3.271 86.814 3.403 ;
     RECT  99.396 3.299 100.854 3.403 ;
     RECT  101.664 3.299 106.11 3.403 ;
     RECT  133.344 3.379 134.658 3.403 ;
     RECT  135.468 3.271 135.594 3.403 ;
     RECT  95.868 3.335 98.514 3.407 ;
     RECT  133.344 3.403 135.594 3.407 ;
     RECT  44.856 2.633 46.134 3.415 ;
     RECT  82.044 2.489 82.278 3.415 ;
     RECT  83.415 3.403 85.086 3.415 ;
     RECT  85.932 3.403 86.814 3.415 ;
     RECT  91.764 3.379 91.998 3.415 ;
     RECT  122.472 3.379 123.93 3.415 ;
     RECT  124.92 3.379 125.586 3.415 ;
     RECT  128.664 2.641 128.682 3.415 ;
     RECT  129.456 3.379 129.474 3.415 ;
     RECT  140.328 3.271 140.454 3.415 ;
     RECT  141.876 3.379 143.19 3.415 ;
     RECT  21.78 3.403 32.526 3.437 ;
     RECT  33.624 3.181 38.286 3.437 ;
     RECT  97.704 3.407 98.514 3.437 ;
     RECT  122.472 3.415 125.586 3.437 ;
     RECT  133.344 3.407 133.362 3.437 ;
     RECT  44.64 3.415 46.134 3.451 ;
     RECT  47.232 2.525 49.122 3.451 ;
     RECT  50.256 2.525 50.274 3.451 ;
     RECT  51.015 2.597 51.297 3.451 ;
     RECT  59.256 3.271 60.822 3.451 ;
     RECT  66.456 2.641 68.562 3.451 ;
     RECT  69.516 3.379 69.822 3.451 ;
     RECT  74.844 2.861 76.446 3.451 ;
     RECT  80.172 2.641 80.19 3.451 ;
     RECT  95.868 3.407 96.93 3.451 ;
     RECT  113.22 3.271 116.097 3.451 ;
     RECT  117.108 3.379 118.782 3.451 ;
     RECT  126.36 3.299 127.818 3.451 ;
     RECT  130.32 3.379 132.57 3.451 ;
     RECT  134.136 3.407 135.594 3.451 ;
     RECT  136.44 3.379 139.302 3.451 ;
     RECT  39.276 2.795 41.202 3.568 ;
     RECT  11.736 2.759 12.294 3.569 ;
     RECT  13.176 2.759 13.497 3.569 ;
     RECT  70.776 2.669 73.386 3.569 ;
     RECT  90.9 2.489 90.918 3.569 ;
     RECT  95.58 3.451 96.93 3.569 ;
     RECT  99.396 3.403 106.11 3.569 ;
     RECT  20.844 3.371 20.862 3.577 ;
     RECT  44.64 3.451 51.297 3.577 ;
     RECT  52.524 3.379 54.162 3.577 ;
     RECT  77.256 3.341 77.274 3.605 ;
     RECT  82.044 3.415 82.494 3.605 ;
     RECT  99.396 3.569 100.602 3.605 ;
     RECT  101.412 3.569 106.11 3.605 ;
     RECT  134.136 3.451 135.666 3.605 ;
     RECT  136.44 3.451 139.59 3.605 ;
     RECT  33.912 3.437 38.286 3.613 ;
     RECT  39.24 3.568 41.202 3.613 ;
     RECT  42.156 2.759 43.182 3.613 ;
     RECT  44.424 3.577 51.297 3.613 ;
     RECT  63.936 3.065 64.098 3.613 ;
     RECT  64.836 2.759 64.854 3.613 ;
     RECT  66.456 3.451 69.822 3.613 ;
     RECT  72.54 3.569 73.386 3.613 ;
     RECT  117.108 3.451 118.926 3.613 ;
     RECT  119.88 3.379 119.934 3.613 ;
     RECT  78.015 3.344 78.786 3.641 ;
     RECT  134.532 3.605 135.666 3.641 ;
     RECT  138.42 3.605 139.59 3.641 ;
     RECT  138.636 3.641 139.59 3.643 ;
     RECT  140.328 3.415 141.102 3.643 ;
     RECT  42.156 3.613 43.362 3.649 ;
     RECT  44.172 3.613 51.297 3.649 ;
     RECT  79.92 3.451 80.19 3.649 ;
     RECT  80.964 3.451 80.982 3.649 ;
     RECT  113.22 3.451 116.19 3.649 ;
     RECT  117.108 3.613 119.934 3.649 ;
     RECT  2.304 3.065 9.99 3.685 ;
     RECT  15.156 2.759 15.174 3.685 ;
     RECT  16.02 2.525 16.038 3.685 ;
     RECT  33.912 3.613 41.202 3.685 ;
     RECT  42.156 3.649 51.297 3.685 ;
     RECT  59.256 3.451 61.002 3.685 ;
     RECT  61.815 3.065 63.162 3.685 ;
     RECT  63.936 3.613 64.854 3.685 ;
     RECT  89.856 2.641 89.91 3.685 ;
     RECT  90.756 3.577 90.774 3.685 ;
     RECT  149.544 3.595 149.562 3.713 ;
     RECT  12.24 3.569 12.294 3.721 ;
     RECT  13.215 3.569 13.497 3.721 ;
     RECT  14.256 3.379 14.382 3.721 ;
     RECT  52.092 3.577 54.162 3.721 ;
     RECT  55.044 2.867 56.898 3.721 ;
     RECT  57.852 2.597 57.87 3.721 ;
     RECT  72.54 3.613 74.07 3.721 ;
     RECT  74.844 3.451 76.482 3.721 ;
     RECT  91.728 3.415 91.998 3.721 ;
     RECT  12.24 3.721 12.402 3.725 ;
     RECT  72.54 3.721 77.202 3.725 ;
     RECT  18 3.403 19.746 3.749 ;
     RECT  33.912 3.685 51.297 3.749 ;
     RECT  79.92 3.649 80.982 3.749 ;
     RECT  107.064 3.271 107.37 3.811 ;
     RECT  63.936 3.685 64.998 3.835 ;
     RECT  2.304 3.685 10.098 3.839 ;
     RECT  20.844 3.577 21.006 3.839 ;
     RECT  21.78 3.437 21.798 3.839 ;
     RECT  63.9 3.835 64.998 3.839 ;
     RECT  83.415 3.415 86.814 3.839 ;
     RECT  91.692 3.721 91.998 3.839 ;
     RECT  101.412 3.605 102.618 3.839 ;
     RECT  126.36 3.451 127.854 3.839 ;
     RECT  85.824 3.839 86.814 3.847 ;
     RECT  92.916 3.271 93.042 3.847 ;
     RECT  13.215 3.721 14.382 3.875 ;
     RECT  84.744 3.839 84.87 3.875 ;
     RECT  85.824 3.847 86.922 3.875 ;
     RECT  101.412 3.839 101.502 3.875 ;
     RECT  141.876 3.415 143.406 3.875 ;
     RECT  145.8 3.299 148.806 3.875 ;
     RECT  34.815 3.749 51.297 3.877 ;
     RECT  52.092 3.721 57.87 3.877 ;
     RECT  34.815 3.877 57.87 3.883 ;
     RECT  142.815 3.875 143.406 3.883 ;
     RECT  144.18 3.299 144.99 3.883 ;
     RECT  10.08 3.839 10.098 3.911 ;
     RECT  34.815 3.883 58.23 3.911 ;
     RECT  63.9 3.839 64.746 3.911 ;
     RECT  36.792 3.911 58.23 3.917 ;
     RECT  134.604 3.641 135.666 3.917 ;
     RECT  108.288 3.379 112.41 3.919 ;
     RECT  113.22 3.649 119.934 3.919 ;
     RECT  120.888 3.379 121.698 3.919 ;
     RECT  128.664 3.415 129.474 3.919 ;
     RECT  145.8 3.875 146.322 3.92 ;
     RECT  107.064 3.811 107.442 3.931 ;
     RECT  108.288 3.919 121.698 3.931 ;
     RECT  36.792 3.917 51.57 3.947 ;
     RECT  59.256 3.685 63.162 3.955 ;
     RECT  66.132 3.613 69.822 3.955 ;
     RECT  91.692 3.839 91.71 3.955 ;
     RECT  135.288 3.917 135.666 3.955 ;
     RECT  136.44 3.605 137.697 3.955 ;
     RECT  20.844 3.839 20.862 3.965 ;
     RECT  36.792 3.947 47.898 3.965 ;
     RECT  44.172 3.965 47.898 3.983 ;
     RECT  48.672 3.947 51.57 3.983 ;
     RECT  64.152 3.911 64.746 3.983 ;
     RECT  107.064 3.931 121.698 3.983 ;
     RECT  138.636 3.643 141.102 3.983 ;
     RECT  145.8 3.92 145.962 3.983 ;
     RECT  66.132 3.955 69.966 3.991 ;
     RECT  82.116 3.605 82.494 3.991 ;
     RECT  83.415 3.839 83.697 3.991 ;
     RECT  111.6 3.983 121.698 4.013 ;
     RECT  135.288 3.955 137.697 4.013 ;
     RECT  111.6 4.013 114.534 4.019 ;
     RECT  122.472 3.437 125.442 4.019 ;
     RECT  44.172 3.983 47.79 4.061 ;
     RECT  14.4 3.979 14.418 4.081 ;
     RECT  15.156 3.685 16.038 4.081 ;
     RECT  22.608 3.437 32.526 4.109 ;
     RECT  34.815 3.911 36.018 4.109 ;
     RECT  59.256 3.955 63.306 4.109 ;
     RECT  76.428 3.725 77.202 4.109 ;
     RECT  82.116 3.991 83.697 4.109 ;
     RECT  92.52 3.847 93.042 4.109 ;
     RECT  95.58 3.569 96.75 4.109 ;
     RECT  123.588 4.019 125.442 4.109 ;
     RECT  128.376 3.919 129.474 4.109 ;
     RECT  147.06 3.875 148.806 4.109 ;
     RECT  48.924 3.983 51.57 4.115 ;
     RECT  123.66 4.109 125.442 4.115 ;
     RECT  52.488 3.917 58.23 4.117 ;
     RECT  65.556 3.991 69.966 4.117 ;
     RECT  70.776 3.569 71.766 4.117 ;
     RECT  103.536 3.605 106.11 4.117 ;
     RECT  107.064 3.983 110.862 4.117 ;
     RECT  14.4 4.081 16.038 4.145 ;
     RECT  49.068 4.115 51.57 4.145 ;
     RECT  65.556 4.117 71.766 4.145 ;
     RECT  111.6 4.019 113.994 4.145 ;
     RECT  135.612 4.013 137.697 4.145 ;
     RECT  139.5 3.983 141.102 4.145 ;
     RECT  22.752 4.109 32.526 4.153 ;
     RECT  52.488 4.117 58.518 4.153 ;
     RECT  59.256 4.109 62.19 4.153 ;
     RECT  65.556 4.145 68.85 4.157 ;
     RECT  122.472 4.019 122.67 4.157 ;
     RECT  126.36 3.839 127.566 4.157 ;
     RECT  128.52 4.109 129.474 4.157 ;
     RECT  130.32 3.451 133.218 4.157 ;
     RECT  88.632 3.299 89.097 4.171 ;
     RECT  89.856 3.685 90.774 4.171 ;
     RECT  36.792 3.965 43.434 4.181 ;
     RECT  44.172 4.061 44.19 4.181 ;
     RECT  45 4.061 47.79 4.181 ;
     RECT  115.38 4.013 121.698 4.181 ;
     RECT  22.752 4.153 32.706 4.189 ;
     RECT  88.632 4.171 90.774 4.205 ;
     RECT  91.548 3.955 91.71 4.205 ;
     RECT  131.472 4.157 133.218 4.205 ;
     RECT  14.544 4.145 16.038 4.225 ;
     RECT  22.752 4.189 32.814 4.225 ;
     RECT  33.912 3.749 33.93 4.225 ;
     RECT  18.615 3.749 19.746 4.253 ;
     RECT  36.792 4.181 39.258 4.253 ;
     RECT  76.428 4.109 77.13 4.253 ;
     RECT  82.116 4.109 82.134 4.253 ;
     RECT  78.015 3.641 78.678 4.261 ;
     RECT  93.816 3.299 94.698 4.261 ;
     RECT  97.704 3.437 98.046 4.261 ;
     RECT  119.412 4.181 121.698 4.261 ;
     RECT  122.472 4.157 122.562 4.261 ;
     RECT  125.028 4.115 125.442 4.261 ;
     RECT  126.36 4.157 126.897 4.261 ;
     RECT  128.772 4.157 129.474 4.261 ;
     RECT  133.2 4.205 133.218 4.261 ;
     RECT  140.4 4.145 141.102 4.261 ;
     RECT  141.876 3.875 142.074 4.261 ;
     RECT  142.815 3.883 144.99 4.261 ;
     RECT  147.204 4.109 148.806 4.261 ;
     RECT  113.544 4.145 113.994 4.289 ;
     RECT  115.38 4.181 118.17 4.289 ;
     RECT  119.412 4.261 122.562 4.289 ;
     RECT  125.028 4.261 126.897 4.289 ;
     RECT  128.772 4.261 129.798 4.289 ;
     RECT  136.548 4.145 137.697 4.289 ;
     RECT  120.6 4.289 122.562 4.301 ;
     RECT  12.276 3.725 12.402 4.379 ;
     RECT  14.544 4.225 16.146 4.379 ;
     RECT  49.716 4.145 51.57 4.379 ;
     RECT  62.964 4.109 63.306 4.379 ;
     RECT  69.624 4.145 71.766 4.379 ;
     RECT  77.976 4.261 78.678 4.379 ;
     RECT  86.652 3.875 86.922 4.379 ;
     RECT  97.704 4.261 98.442 4.379 ;
     RECT  120.6 4.301 122.022 4.379 ;
     RECT  103.536 4.117 110.862 4.387 ;
     RECT  95.58 4.109 96.102 4.397 ;
     RECT  113.76 4.289 113.994 4.397 ;
     RECT  22.752 4.225 33.93 4.415 ;
     RECT  40.215 4.181 43.434 4.415 ;
     RECT  52.488 4.153 62.19 4.415 ;
     RECT  113.76 4.397 113.886 4.415 ;
     RECT  117.648 4.289 118.17 4.415 ;
     RECT  125.424 4.289 126.897 4.415 ;
     RECT  129.24 4.289 129.798 4.415 ;
     RECT  133.2 4.261 133.686 4.415 ;
     RECT  140.4 4.261 142.074 4.415 ;
     RECT  11.16 3.685 11.322 4.445 ;
     RECT  14.544 4.379 15.318 4.445 ;
     RECT  16.128 4.379 16.146 4.451 ;
     RECT  93.564 4.261 94.698 4.451 ;
     RECT  125.892 4.415 126.897 4.451 ;
     RECT  93.6 4.451 94.698 4.459 ;
     RECT  36.792 4.253 38.358 4.487 ;
     RECT  40.215 4.415 41.058 4.487 ;
     RECT  42.084 4.415 43.434 4.487 ;
     RECT  45.072 4.181 47.79 4.487 ;
     RECT  49.716 4.379 51.297 4.487 ;
     RECT  52.488 4.415 57.69 4.487 ;
     RECT  58.68 4.415 59.094 4.487 ;
     RECT  59.94 4.415 62.19 4.487 ;
     RECT  103.5 4.387 110.862 4.487 ;
     RECT  115.38 4.289 116.766 4.487 ;
     RECT  45.072 4.487 46.638 4.493 ;
     RECT  92.52 4.109 92.79 4.493 ;
     RECT  25.092 4.415 33.93 4.523 ;
     RECT  42.228 4.487 43.398 4.523 ;
     RECT  45.615 4.493 46.638 4.523 ;
     RECT  47.52 4.487 47.79 4.523 ;
     RECT  49.716 4.487 49.734 4.523 ;
     RECT  50.76 4.487 51.297 4.523 ;
     RECT  72.54 3.725 75.69 4.523 ;
     RECT  93.6 4.459 94.77 4.523 ;
     RECT  107.064 4.487 110.862 4.523 ;
     RECT  118.152 4.415 118.17 4.523 ;
     RECT  69.912 4.379 71.766 4.531 ;
     RECT  72.54 4.523 74.394 4.531 ;
     RECT  79.92 3.749 80.91 4.531 ;
     RECT  65.556 4.157 67.986 4.541 ;
     RECT  42.228 4.523 42.246 4.559 ;
     RECT  53.064 4.487 57.294 4.559 ;
     RECT  75.636 4.523 75.69 4.559 ;
     RECT  121.104 4.379 122.022 4.559 ;
     RECT  138.492 4.459 138.51 4.559 ;
     RECT  147.204 4.261 148.878 4.603 ;
     RECT  141.372 4.415 142.074 4.621 ;
     RECT  142.815 4.261 145.278 4.621 ;
     RECT  47.7 4.523 47.79 4.649 ;
     RECT  69.912 4.531 74.394 4.649 ;
     RECT  43.164 4.523 43.398 4.685 ;
     RECT  47.7 4.649 47.718 4.685 ;
     RECT  53.82 4.559 57.294 4.691 ;
     RECT  27.432 4.523 33.93 4.693 ;
     RECT  34.815 4.109 35.622 4.693 ;
     RECT  147.204 4.603 149.31 4.721 ;
     RECT  43.164 4.685 43.182 4.757 ;
     RECT  22.752 4.415 24.297 4.793 ;
     RECT  141.372 4.621 145.278 4.793 ;
     RECT  18.615 4.253 19.422 4.829 ;
     RECT  69.912 4.649 73.422 4.829 ;
     RECT  138.528 4.729 138.546 4.829 ;
     RECT  27.432 4.693 35.622 4.891 ;
     RECT  147.204 4.721 148.914 4.891 ;
     RECT  121.104 4.559 121.497 4.928 ;
     RECT  142.704 4.793 145.278 4.928 ;
     RECT  142.815 4.928 145.278 4.973 ;
     RECT  146.484 4.891 148.914 4.991 ;
     RECT  146.484 4.991 147.258 5.021 ;
     RECT  69.912 4.829 71.766 5.063 ;
     RECT  25.092 4.523 26.694 5.099 ;
     RECT  68.832 4.157 68.85 5.161 ;
     RECT  77.976 4.379 78.354 5.161 ;
     RECT  134.532 4.459 134.55 5.197 ;
     RECT  27.432 4.891 36.018 5.233 ;
     RECT  36.792 4.487 37.89 5.233 ;
     RECT  62.964 4.379 63.162 5.233 ;
     RECT  64.152 3.983 64.17 5.233 ;
     RECT  68.832 5.161 69.174 5.261 ;
     RECT  61.2 4.487 62.19 5.269 ;
     RECT  62.964 5.233 64.17 5.269 ;
     RECT  2.304 3.839 9.198 5.305 ;
     RECT  59.94 4.487 60.246 5.305 ;
     RECT  65.7 4.541 67.986 5.341 ;
     RECT  75.672 4.559 75.69 5.341 ;
     RECT  134.532 5.197 134.73 5.459 ;
     RECT  72.615 4.829 73.422 5.467 ;
     RECT  72.615 5.467 73.458 5.539 ;
     RECT  75.672 5.341 75.726 5.539 ;
     RECT  76.464 4.253 77.13 5.539 ;
     RECT  77.976 5.161 78.462 5.563 ;
     RECT  79.2 4.531 80.91 5.563 ;
     RECT  74.376 4.649 74.394 5.575 ;
     RECT  72.615 5.539 73.53 5.611 ;
     RECT  74.376 5.575 74.79 5.611 ;
     RECT  145.26 4.973 145.278 5.611 ;
     RECT  72.615 5.611 74.79 5.645 ;
     RECT  142.815 4.973 144.306 5.645 ;
     RECT  148.176 4.991 148.914 5.659 ;
     RECT  27.432 5.233 37.89 5.701 ;
     RECT  39.24 4.253 39.258 5.773 ;
     RECT  27.432 5.701 37.926 5.803 ;
     RECT  38.988 5.773 39.258 5.803 ;
     RECT  70.092 5.063 71.766 5.809 ;
     RECT  142.815 5.645 143.334 5.809 ;
     RECT  70.092 5.809 71.874 5.845 ;
     RECT  72.615 5.645 74.394 5.845 ;
     RECT  148.176 5.659 149.526 5.873 ;
     RECT  148.176 5.873 148.878 5.881 ;
     RECT  142.56 5.809 143.334 5.909 ;
     RECT  22.752 4.793 22.77 5.999 ;
     RECT  68.832 5.261 68.85 6.007 ;
     RECT  70.092 5.845 74.394 6.007 ;
     RECT  75.672 5.539 77.13 6.007 ;
     RECT  148.068 5.881 148.878 6.035 ;
     RECT  65.376 5.341 67.986 6.079 ;
     RECT  68.832 6.007 74.394 6.079 ;
     RECT  145.26 5.611 145.962 6.107 ;
     RECT  75.132 6.007 77.13 6.115 ;
     RECT  77.976 5.563 80.91 6.115 ;
     RECT  75.132 6.115 80.91 6.283 ;
     RECT  27.432 5.803 39.258 6.305 ;
     RECT  115.38 4.487 116.586 6.305 ;
     RECT  34.2 6.305 39.258 6.341 ;
     RECT  123.66 4.115 123.678 6.341 ;
     RECT  145.26 6.107 145.386 6.539 ;
     RECT  144.288 5.645 144.306 6.575 ;
     RECT  58.68 4.487 58.698 6.583 ;
     RECT  103.5 4.487 106.182 6.583 ;
     RECT  136.584 4.289 137.697 6.611 ;
     RECT  144.432 6.655 144.45 6.691 ;
     RECT  145.26 6.539 145.278 6.691 ;
     RECT  148.176 6.035 148.878 6.691 ;
     RECT  144.432 6.691 145.278 6.701 ;
     RECT  147.204 5.021 147.258 6.715 ;
     RECT  27.432 6.305 33.318 6.719 ;
     RECT  144.576 6.701 145.278 6.749 ;
     RECT  148.176 6.691 149.382 6.749 ;
     RECT  82.188 6.421 82.206 6.763 ;
     RECT  75.132 6.283 81.27 6.781 ;
     RECT  82.188 6.763 82.278 6.781 ;
     RECT  146.88 6.715 147.258 6.808 ;
     RECT  27.432 6.719 32.238 6.809 ;
     RECT  34.38 6.341 39.258 6.809 ;
     RECT  65.376 6.079 74.394 6.817 ;
     RECT  75.132 6.781 82.278 6.817 ;
     RECT  25.308 5.099 26.694 6.845 ;
     RECT  33.012 6.719 33.318 6.845 ;
     RECT  34.452 6.809 39.258 6.845 ;
     RECT  146.736 6.808 147.258 6.845 ;
     RECT  34.488 6.845 37.926 6.917 ;
     RECT  65.376 6.817 82.278 6.925 ;
     RECT  83.052 4.109 83.697 6.925 ;
     RECT  65.376 6.925 83.697 6.953 ;
     RECT  34.815 6.917 37.926 7.079 ;
     RECT  38.736 6.845 39.258 7.079 ;
     RECT  115.416 6.305 116.586 7.115 ;
     RECT  139.5 4.145 139.518 7.151 ;
     RECT  70.128 6.953 83.697 7.187 ;
     RECT  103.428 6.583 106.182 7.195 ;
     RECT  107.064 4.523 109.53 7.195 ;
     RECT  70.128 7.187 82.278 7.223 ;
     RECT  70.128 7.223 82.242 7.259 ;
     RECT  70.128 7.259 81.054 7.385 ;
     RECT  70.272 7.385 81.054 7.421 ;
     RECT  82.224 7.259 82.242 7.421 ;
     RECT  2.304 5.305 9.27 7.531 ;
     RECT  2.268 7.531 9.27 7.655 ;
     RECT  99.432 3.605 100.602 7.663 ;
     RECT  101.412 3.875 101.43 7.663 ;
     RECT  36.468 7.079 37.926 7.691 ;
     RECT  131.472 4.205 132.354 7.691 ;
     RECT  23.616 4.793 24.297 7.699 ;
     RECT  39.24 7.079 39.258 7.727 ;
     RECT  2.268 7.655 2.697 7.763 ;
     RECT  149.868 7.723 149.886 7.763 ;
     RECT  144.9 6.749 145.278 7.771 ;
     RECT  72.615 7.421 74.862 7.799 ;
     RECT  142.815 5.909 143.334 7.861 ;
     RECT  147.204 6.845 147.258 7.963 ;
     RECT  142.815 7.861 144.054 8.045 ;
     RECT  3.42 7.655 9.27 8.159 ;
     RECT  22.428 8.041 22.446 8.167 ;
     RECT  114.084 6.421 114.102 8.167 ;
     RECT  119.412 4.289 119.43 8.195 ;
     RECT  146.484 7.963 147.258 8.195 ;
     RECT  103.428 7.195 109.53 8.203 ;
     RECT  147.204 8.195 147.258 8.203 ;
     RECT  148.176 6.749 148.878 8.203 ;
     RECT  70.308 7.421 71.874 8.239 ;
     RECT  72.615 7.799 73.494 8.239 ;
     RECT  36.828 7.691 37.926 8.267 ;
     RECT  54 4.691 57.294 8.275 ;
     RECT  103.428 8.203 109.602 8.275 ;
     RECT  110.415 4.523 110.862 8.275 ;
     RECT  3.456 8.159 9.27 8.303 ;
     RECT  33.012 6.845 33.03 8.303 ;
     RECT  114.084 8.167 114.642 8.303 ;
     RECT  114.084 8.303 114.102 8.339 ;
     RECT  103.428 8.275 110.862 8.501 ;
     RECT  22.428 8.167 22.662 8.581 ;
     RECT  23.436 7.699 24.297 8.581 ;
     RECT  22.428 8.581 24.297 8.671 ;
     RECT  144.072 8.581 144.09 8.699 ;
     RECT  61.2 5.269 64.17 8.815 ;
     RECT  102.42 3.839 102.51 8.815 ;
     RECT  103.428 8.501 109.134 8.815 ;
     RECT  36.828 8.267 36.846 8.843 ;
     RECT  133.668 4.415 133.686 8.843 ;
     RECT  149.868 8.779 149.886 8.843 ;
     RECT  144.828 7.771 145.278 8.875 ;
     RECT  92.52 4.493 92.538 8.941 ;
     RECT  144.828 8.875 145.638 8.969 ;
     RECT  22.428 8.671 24.462 8.977 ;
     RECT  25.308 6.845 26.658 8.977 ;
     RECT  40.215 4.487 40.59 9.005 ;
     RECT  115.815 7.115 116.586 9.005 ;
     RECT  144.828 8.969 145.53 9.053 ;
     RECT  2.304 7.763 2.697 9.067 ;
     RECT  3.492 8.303 9.27 9.067 ;
     RECT  34.815 7.079 35.622 9.419 ;
     RECT  142.815 8.045 143.334 9.419 ;
     RECT  27.432 6.809 31.662 9.509 ;
     RECT  131.472 7.691 132.297 9.545 ;
     RECT  146.376 9.499 146.394 9.545 ;
     RECT  142.815 9.419 143.097 9.589 ;
     RECT  147.204 8.203 148.878 9.625 ;
     RECT  142.524 9.589 143.097 9.689 ;
     RECT  147.06 9.625 148.878 9.835 ;
     RECT  147.06 9.835 149.238 9.887 ;
     RECT  99.432 7.663 101.43 9.895 ;
     RECT  102.42 8.815 109.134 9.895 ;
     RECT  147.204 9.887 149.238 9.923 ;
     RECT  59.796 5.305 60.246 9.931 ;
     RECT  61.2 8.815 64.35 9.931 ;
     RECT  2.304 9.067 9.27 9.959 ;
     RECT  37.836 8.267 37.926 9.959 ;
     RECT  11.268 4.445 11.322 10.057 ;
     RECT  10.8 10.057 11.322 10.085 ;
     RECT  135.612 4.145 135.63 10.157 ;
     RECT  22.428 8.977 26.658 10.165 ;
     RECT  27.432 9.509 31.338 10.165 ;
     RECT  22.428 10.165 31.338 10.193 ;
     RECT  14.544 4.445 14.562 10.327 ;
     RECT  15.3 4.445 15.318 10.327 ;
     RECT  97.704 4.379 98.334 10.327 ;
     RECT  14.544 10.327 15.318 10.355 ;
     RECT  14.796 10.355 15.318 10.391 ;
     RECT  12.384 4.379 12.402 10.435 ;
     RECT  13.215 3.875 13.554 10.435 ;
     RECT  144.828 9.053 145.278 10.555 ;
     RECT  10.8 10.085 11.286 10.589 ;
     RECT  12.384 10.435 13.554 10.589 ;
     RECT  97.704 10.327 98.622 10.589 ;
     RECT  146.412 10.327 146.43 10.589 ;
     RECT  34.815 9.419 35.226 10.741 ;
     RECT  144.828 10.555 145.494 10.741 ;
     RECT  34.776 10.741 35.226 10.769 ;
     RECT  147.204 9.923 148.878 10.843 ;
     RECT  2.304 9.959 9.234 10.895 ;
     RECT  54 8.275 57.618 10.975 ;
     RECT  147.204 10.843 149.418 11.003 ;
     RECT  51.015 4.523 51.297 11.011 ;
     RECT  88.632 4.205 90.342 11.011 ;
     RECT  91.692 4.205 91.71 11.011 ;
     RECT  53.928 10.975 57.618 11.021 ;
     RECT  144.828 10.741 145.962 11.039 ;
     RECT  50.832 11.011 51.297 11.101 ;
     RECT  10.8 10.589 10.818 11.129 ;
     RECT  88.632 11.011 91.71 11.129 ;
     RECT  147.204 11.003 148.878 11.129 ;
     RECT  0.108 10.291 0.126 11.165 ;
     RECT  13.215 10.589 13.554 11.201 ;
     RECT  50.796 11.101 51.297 11.201 ;
     RECT  129.78 4.415 129.798 11.201 ;
     RECT  91.692 11.129 91.71 11.209 ;
     RECT  92.52 8.941 92.718 11.209 ;
     RECT  15.3 10.391 15.318 11.237 ;
     RECT  140.4 4.415 140.418 11.237 ;
     RECT  50.832 11.201 51.297 11.273 ;
     RECT  91.692 11.209 92.718 11.309 ;
     RECT  12.348 11.365 12.366 11.371 ;
     RECT  13.215 11.201 13.497 11.371 ;
     RECT  91.692 11.309 91.926 11.399 ;
     RECT  12.348 11.371 13.497 11.405 ;
     RECT  12.636 11.405 13.497 11.453 ;
     RECT  137.052 6.611 137.697 11.579 ;
     RECT  37.908 9.959 37.926 11.669 ;
     RECT  34.776 10.769 35.097 11.749 ;
     RECT  70.308 8.239 73.494 11.755 ;
     RECT  92.7 11.309 92.718 11.821 ;
     RECT  93.708 4.523 94.77 11.821 ;
     RECT  96.948 8.743 96.966 11.821 ;
     RECT  97.704 10.589 98.334 11.821 ;
     RECT  147.204 11.129 148.806 11.821 ;
     RECT  2.304 10.895 8.334 11.899 ;
     RECT  65.376 6.953 69.39 11.911 ;
     RECT  2.268 11.899 8.334 11.939 ;
     RECT  92.7 11.821 94.77 11.939 ;
     RECT  65.16 11.911 69.39 11.947 ;
     RECT  147.024 11.821 148.806 11.947 ;
     RECT  2.268 11.939 3.87 11.975 ;
     RECT  149.868 11.899 149.886 11.975 ;
     RECT  13.104 11.453 13.497 11.981 ;
     RECT  146.916 11.947 148.806 11.981 ;
     RECT  4.716 11.939 8.334 11.983 ;
     RECT  146.916 11.981 148.497 11.984 ;
     RECT  22.428 10.193 25.65 12.091 ;
     RECT  26.46 10.193 31.338 12.091 ;
     RECT  96.948 11.821 98.334 12.091 ;
     RECT  99.432 9.895 109.134 12.091 ;
     RECT  54 11.021 57.618 12.181 ;
     RECT  84.744 3.875 84.762 12.181 ;
     RECT  0.54 11.209 0.558 12.221 ;
     RECT  93.492 11.939 94.77 12.253 ;
     RECT  95.58 4.397 95.598 12.253 ;
     RECT  93.492 12.253 95.598 12.281 ;
     RECT  110.415 8.501 110.862 12.289 ;
     RECT  111.6 4.145 112.59 12.289 ;
     RECT  141.372 4.793 141.39 12.317 ;
     RECT  22.428 12.091 31.338 12.325 ;
     RECT  51.015 11.273 51.297 12.325 ;
     RECT  58.68 6.583 59.022 12.325 ;
     RECT  59.796 9.931 64.35 12.325 ;
     RECT  84.744 12.181 85.05 12.331 ;
     RECT  85.824 3.875 85.842 12.331 ;
     RECT  33.948 11.137 33.966 12.361 ;
     RECT  34.776 11.749 35.478 12.361 ;
     RECT  50.796 12.325 51.297 12.361 ;
     RECT  53.064 4.559 53.082 12.361 ;
     RECT  70.164 11.755 73.494 12.361 ;
     RECT  74.376 7.799 74.862 12.361 ;
     RECT  4.716 11.983 8.478 12.451 ;
     RECT  9.216 10.895 9.234 12.451 ;
     RECT  53.82 12.181 57.618 12.451 ;
     RECT  58.68 12.325 64.35 12.451 ;
     RECT  65.088 11.947 69.39 12.451 ;
     RECT  70.164 12.361 74.862 12.451 ;
     RECT  22.428 12.325 31.59 12.475 ;
     RECT  33.948 12.361 35.478 12.475 ;
     RECT  88.632 11.129 90.666 12.479 ;
     RECT  41.688 12.451 41.706 12.509 ;
     RECT  22.284 12.475 31.59 12.515 ;
     RECT  33.768 12.475 35.478 12.515 ;
     RECT  40.215 9.005 40.497 12.523 ;
     RECT  93.492 12.281 95.202 12.551 ;
     RECT  52.92 12.361 53.082 12.557 ;
     RECT  50.76 12.361 51.297 12.559 ;
     RECT  53.064 12.557 53.082 12.619 ;
     RECT  53.82 12.451 64.35 12.619 ;
     RECT  53.064 12.619 64.35 12.631 ;
     RECT  65.088 12.451 74.862 12.631 ;
     RECT  2.268 11.975 3.654 12.659 ;
     RECT  53.064 12.631 74.862 12.659 ;
     RECT  53.82 12.659 74.862 12.755 ;
     RECT  53.82 12.755 62.91 12.785 ;
     RECT  63.756 12.755 74.862 12.785 ;
     RECT  110.415 12.289 112.59 12.793 ;
     RECT  147.204 11.984 148.497 12.821 ;
     RECT  66.708 12.785 74.862 12.857 ;
     RECT  2.304 12.659 3.654 12.865 ;
     RECT  96.948 12.091 109.134 12.865 ;
     RECT  2.304 12.865 3.798 12.901 ;
     RECT  4.716 12.451 9.234 12.901 ;
     RECT  142.815 9.689 143.097 12.901 ;
     RECT  96.732 12.865 109.134 12.907 ;
     RECT  63.756 12.785 65.934 12.929 ;
     RECT  69.192 12.857 74.862 12.929 ;
     RECT  60.876 12.785 62.91 12.941 ;
     RECT  110.376 12.793 112.59 12.955 ;
     RECT  142.815 12.901 143.622 12.991 ;
     RECT  144.828 11.039 145.242 12.991 ;
     RECT  60.948 12.941 62.91 13.019 ;
     RECT  69.192 12.929 71.55 13.019 ;
     RECT  84.744 12.331 85.842 13.019 ;
     RECT  109.908 12.955 112.59 13.019 ;
     RECT  96.588 12.907 109.134 13.051 ;
     RECT  142.815 12.991 145.242 13.051 ;
     RECT  53.82 12.785 60.138 13.055 ;
     RECT  64.08 12.929 65.934 13.055 ;
     RECT  69.192 13.019 71.514 13.055 ;
     RECT  96.588 13.051 109.602 13.055 ;
     RECT  142.632 13.051 145.242 13.055 ;
     RECT  144.216 13.055 145.242 13.063 ;
     RECT  66.708 12.857 68.418 13.091 ;
     RECT  69.912 13.055 71.514 13.091 ;
     RECT  142.632 13.055 143.097 13.091 ;
     RECT  149.292 12.955 149.31 13.091 ;
     RECT  18.615 4.829 18.897 13.135 ;
     RECT  72.615 12.929 74.862 13.171 ;
     RECT  75.744 7.421 81.054 13.171 ;
     RECT  50.724 12.559 51.297 13.261 ;
     RECT  72.615 13.171 81.054 13.289 ;
     RECT  18.615 13.135 19.026 13.325 ;
     RECT  59.868 13.055 60.138 13.325 ;
     RECT  144.216 13.063 145.926 13.325 ;
     RECT  91.692 11.399 91.71 13.333 ;
     RECT  92.7 11.939 92.718 13.333 ;
     RECT  86.904 4.379 86.922 13.339 ;
     RECT  61.236 13.019 62.91 13.397 ;
     RECT  91.692 13.333 92.718 13.405 ;
     RECT  93.492 12.551 94.77 13.405 ;
     RECT  13.215 11.981 13.497 13.432 ;
     RECT  45.615 4.523 45.897 13.432 ;
     RECT  40.14 12.523 40.497 13.441 ;
     RECT  75.744 13.289 81.054 13.441 ;
     RECT  91.692 13.405 94.77 13.441 ;
     RECT  45.504 13.432 45.897 13.469 ;
     RECT  86.652 13.339 86.922 13.469 ;
     RECT  144.216 13.325 145.242 13.469 ;
     RECT  53.82 13.055 59.022 13.559 ;
     RECT  61.308 13.397 62.91 13.559 ;
     RECT  13.104 13.432 13.497 13.595 ;
     RECT  22.428 12.515 31.59 13.595 ;
     RECT  91.692 13.441 95.238 13.595 ;
     RECT  91.692 13.595 92.718 13.603 ;
     RECT  121.215 4.928 121.497 13.603 ;
     RECT  0.108 12.793 0.162 13.613 ;
     RECT  13.176 13.595 13.497 13.613 ;
     RECT  75.744 13.441 81.774 13.667 ;
     RECT  110.376 13.019 112.59 13.667 ;
     RECT  53.064 12.659 53.082 13.675 ;
     RECT  93.492 13.595 95.238 13.675 ;
     RECT  38.628 11.947 38.646 13.711 ;
     RECT  137.415 11.579 137.697 13.711 ;
     RECT  38.628 13.711 38.754 13.739 ;
     RECT  0.108 13.613 0.126 13.757 ;
     RECT  10.404 12.829 10.422 13.801 ;
     RECT  96.732 13.055 109.602 13.829 ;
     RECT  93.492 13.675 95.274 13.837 ;
     RECT  96.732 13.829 109.098 13.853 ;
     RECT  96.876 13.853 109.098 13.865 ;
     RECT  83.052 7.187 83.697 13.867 ;
     RECT  142.815 13.091 143.097 13.873 ;
     RECT  38.736 13.739 38.754 13.901 ;
     RECT  82.656 13.867 83.697 13.901 ;
     RECT  82.656 13.901 82.674 13.907 ;
     RECT  75.996 13.667 81.774 13.945 ;
     RECT  137.415 13.711 138.258 13.981 ;
     RECT  146.484 13.945 146.502 13.981 ;
     RECT  147.24 12.821 148.497 13.981 ;
     RECT  10.404 13.801 10.818 14.009 ;
     RECT  96.876 13.865 107.586 14.045 ;
     RECT  84.744 13.019 84.762 14.071 ;
     RECT  85.5 13.019 85.842 14.071 ;
     RECT  75.996 13.945 82.17 14.099 ;
     RECT  84.744 14.071 85.842 14.099 ;
     RECT  110.376 13.667 111.618 14.099 ;
     RECT  39.564 13.441 40.497 14.107 ;
     RECT  135.072 13.171 135.09 14.143 ;
     RECT  91.656 13.603 92.718 14.171 ;
     RECT  149.868 13.963 149.886 14.171 ;
     RECT  84.744 14.099 85.05 14.189 ;
     RECT  29.016 13.595 31.59 14.207 ;
     RECT  53.82 13.559 57.222 14.207 ;
     RECT  110.376 14.099 110.862 14.215 ;
     RECT  146.484 13.981 148.497 14.237 ;
     RECT  22.428 13.595 28.206 14.243 ;
     RECT  29.016 14.207 30.798 14.243 ;
     RECT  88.632 12.479 90.342 14.251 ;
     RECT  91.116 14.215 91.638 14.251 ;
     RECT  46.62 4.523 46.638 14.279 ;
     RECT  14.22 12.325 14.238 14.299 ;
     RECT  15.192 13.405 15.21 14.299 ;
     RECT  27.576 14.243 28.206 14.341 ;
     RECT  29.016 14.243 30.762 14.341 ;
     RECT  86.904 13.469 86.922 14.377 ;
     RECT  92.628 14.171 92.718 14.377 ;
     RECT  93.492 13.837 95.778 14.377 ;
     RECT  27.576 14.341 30.762 14.405 ;
     RECT  147.06 14.237 148.497 14.405 ;
     RECT  111.6 14.099 111.618 14.44 ;
     RECT  112.572 13.667 112.59 14.44 ;
     RECT  2.304 12.901 9.234 14.477 ;
     RECT  27.72 14.405 30.762 14.477 ;
     RECT  111.6 14.44 112.59 14.477 ;
     RECT  92.628 14.377 95.778 14.521 ;
     RECT  14.22 14.299 15.21 14.639 ;
     RECT  75.996 14.099 81.774 14.639 ;
     RECT  14.22 14.639 14.346 14.669 ;
     RECT  28.512 14.477 30.762 14.675 ;
     RECT  87.768 3.341 87.786 14.683 ;
     RECT  92.628 14.521 95.922 14.683 ;
     RECT  108.468 13.865 109.098 14.683 ;
     RECT  87.768 14.683 87.894 14.731 ;
     RECT  88.632 14.251 91.638 14.731 ;
     RECT  96.876 14.045 107.55 14.779 ;
     RECT  75.996 14.639 76.014 14.791 ;
     RECT  96.84 14.779 107.55 14.791 ;
     RECT  108.324 14.683 109.098 14.791 ;
     RECT  109.836 14.215 110.862 14.791 ;
     RECT  96.84 14.791 107.586 14.819 ;
     RECT  96.948 14.819 107.586 14.881 ;
     RECT  108.324 14.791 110.862 14.881 ;
     RECT  75.816 14.791 76.014 14.909 ;
     RECT  92.628 14.683 95.994 14.909 ;
     RECT  111.6 14.477 111.69 14.909 ;
     RECT  87.768 14.731 91.638 14.917 ;
     RECT  144.828 13.469 145.242 14.917 ;
     RECT  92.628 14.909 95.922 14.945 ;
     RECT  96.948 14.881 110.862 14.945 ;
     RECT  72.615 13.289 74.862 14.953 ;
     RECT  75.816 14.909 75.906 14.953 ;
     RECT  144.432 14.917 145.242 14.957 ;
     RECT  96.948 14.945 109.098 15.017 ;
     RECT  149.868 15.016 149.886 15.053 ;
     RECT  92.628 14.945 95.238 15.061 ;
     RECT  72.615 14.953 75.906 15.179 ;
     RECT  87.768 14.917 91.674 15.179 ;
     RECT  109.836 14.945 110.862 15.179 ;
     RECT  111.672 14.909 111.69 15.179 ;
     RECT  75.6 15.179 75.906 15.251 ;
     RECT  2.415 14.477 9.234 15.259 ;
     RECT  84.744 14.189 84.762 15.331 ;
     RECT  85.824 14.099 85.842 15.331 ;
     RECT  86.652 14.377 86.922 15.331 ;
     RECT  87.768 15.179 90.954 15.331 ;
     RECT  75.78 15.251 75.906 15.359 ;
     RECT  84.744 15.331 90.954 15.485 ;
     RECT  92.556 15.061 95.238 15.529 ;
     RECT  2.412 15.259 9.234 15.601 ;
     RECT  92.088 15.529 95.238 15.629 ;
     RECT  13.215 13.613 13.497 15.691 ;
     RECT  45.615 13.469 45.897 15.691 ;
     RECT  96.948 15.017 108.882 15.727 ;
     RECT  13.104 15.691 13.497 15.728 ;
     RECT  45.504 15.691 45.897 15.728 ;
     RECT  96.912 15.727 108.882 15.763 ;
     RECT  75.888 15.359 75.906 15.773 ;
     RECT  110.415 15.179 110.862 15.827 ;
     RECT  86.58 15.485 90.954 15.961 ;
     RECT  144.576 14.957 145.242 15.979 ;
     RECT  96.912 15.763 109.386 15.989 ;
     RECT  2.304 15.601 9.234 15.997 ;
     RECT  86.58 15.961 91.278 15.997 ;
     RECT  92.088 15.629 95.202 15.997 ;
     RECT  96.912 15.989 109.242 15.997 ;
     RECT  86.58 15.997 95.202 16.013 ;
     RECT  76.968 14.639 81.774 16.025 ;
     RECT  86.58 16.013 91.098 16.061 ;
     RECT  142.815 13.873 143.19 16.069 ;
     RECT  91.836 16.013 95.202 16.097 ;
     RECT  96.012 15.997 109.242 16.105 ;
     RECT  149.868 16.075 149.886 16.133 ;
     RECT  142.2 16.069 143.19 16.141 ;
     RECT  144.18 15.979 145.242 16.141 ;
     RECT  2.304 15.997 9.558 16.169 ;
     RECT  84.744 15.485 85.842 16.169 ;
     RECT  82.656 15.187 82.674 16.259 ;
     RECT  91.98 16.097 95.202 16.295 ;
     RECT  2.304 16.169 9.486 16.331 ;
     RECT  95.976 16.105 109.242 16.331 ;
     RECT  142.2 16.141 145.242 16.367 ;
     RECT  99.54 16.331 109.242 16.397 ;
     RECT  95.976 16.331 98.766 16.403 ;
     RECT  86.58 16.061 90.954 16.411 ;
     RECT  2.304 16.331 9.45 16.529 ;
     RECT  84.744 16.169 85.626 16.529 ;
     RECT  96.588 16.403 98.766 16.541 ;
     RECT  132.015 9.545 132.297 16.609 ;
     RECT  99.615 16.397 109.242 16.673 ;
     RECT  86.4 16.411 90.954 16.835 ;
     RECT  84.744 16.529 85.482 16.871 ;
     RECT  96.912 16.541 98.766 16.871 ;
     RECT  77.076 16.025 81.774 16.943 ;
     RECT  144.828 16.367 145.242 16.951 ;
     RECT  146.196 15.223 146.214 16.951 ;
     RECT  96.984 16.871 98.766 17.069 ;
     RECT  142.2 16.367 144.054 17.069 ;
     RECT  144.828 16.951 146.214 17.069 ;
     RECT  86.4 16.835 87.498 17.077 ;
     RECT  145.224 17.069 146.214 17.077 ;
     RECT  97.02 17.069 98.766 17.105 ;
     RECT  142.2 17.069 143.91 17.117 ;
     RECT  149.868 17.077 149.886 17.117 ;
     RECT  92.124 16.295 95.202 17.275 ;
     RECT  21.528 12.865 21.546 17.311 ;
     RECT  92.124 17.275 95.886 17.339 ;
     RECT  99.615 16.673 105.93 17.339 ;
     RECT  56.124 14.207 57.222 17.375 ;
     RECT  99.615 17.339 105.75 17.405 ;
     RECT  2.304 16.529 9.234 17.491 ;
     RECT  17.136 12.523 17.154 17.491 ;
     RECT  33.948 12.515 35.478 17.491 ;
     RECT  114.228 14.449 114.246 17.491 ;
     RECT  59.94 13.325 60.138 17.519 ;
     RECT  90.396 16.835 90.954 17.581 ;
     RECT  92.124 17.339 95.202 17.581 ;
     RECT  114.228 17.491 114.858 17.581 ;
     RECT  115.815 9.005 116.097 17.581 ;
     RECT  78.015 16.943 81.774 17.609 ;
     RECT  2.304 17.491 9.342 17.645 ;
     RECT  53.82 14.207 55.35 17.645 ;
     RECT  90.396 17.581 95.202 17.645 ;
     RECT  41.94 17.491 41.958 17.653 ;
     RECT  33.948 17.491 36.054 17.717 ;
     RECT  96.228 17.611 96.246 17.717 ;
     RECT  39.132 14.107 40.497 17.761 ;
     RECT  41.868 17.653 41.958 17.761 ;
     RECT  145.224 17.077 146.43 17.761 ;
     RECT  147.24 14.405 148.497 17.761 ;
     RECT  41.868 17.761 42.138 17.789 ;
     RECT  80.496 17.609 81.774 17.789 ;
     RECT  2.304 17.645 9.234 17.851 ;
     RECT  38.808 17.761 40.497 17.879 ;
     RECT  42.12 17.789 42.138 17.879 ;
     RECT  18.615 13.325 18.897 17.887 ;
     RECT  20.016 17.851 20.034 17.887 ;
     RECT  37.296 17.761 37.314 17.915 ;
     RECT  54.144 17.645 55.35 17.915 ;
     RECT  132.015 16.609 132.642 17.923 ;
     RECT  2.268 17.851 9.234 17.951 ;
     RECT  125.784 16.573 125.802 17.959 ;
     RECT  126.615 4.451 126.897 17.959 ;
     RECT  145.224 17.761 148.497 18.029 ;
     RECT  146.196 18.029 148.497 18.149 ;
     RECT  90.9 17.645 95.202 18.193 ;
     RECT  149.292 18.139 149.31 18.221 ;
     RECT  90.9 18.193 95.238 18.229 ;
     RECT  99.615 17.405 100.062 18.229 ;
     RECT  100.8 17.405 105.75 18.229 ;
     RECT  97.02 17.105 97.506 18.235 ;
     RECT  98.316 17.105 98.766 18.235 ;
     RECT  88.236 16.835 89.658 18.329 ;
     RECT  90.9 18.229 95.31 18.329 ;
     RECT  0.54 17.995 0.558 18.365 ;
     RECT  94.215 18.329 95.238 18.419 ;
     RECT  90.9 18.329 93.474 18.427 ;
     RECT  139.032 18.391 139.05 18.461 ;
     RECT  90.684 18.427 93.474 18.499 ;
     RECT  90.648 18.499 93.474 18.5 ;
     RECT  90.648 18.5 90.666 18.535 ;
     RECT  97.02 18.235 98.766 18.571 ;
     RECT  99.615 18.229 105.75 18.571 ;
     RECT  140.184 16.375 140.202 18.571 ;
     RECT  88.815 18.329 89.658 18.661 ;
     RECT  85.464 16.871 85.482 18.689 ;
     RECT  90.576 18.535 90.666 18.689 ;
     RECT  91.404 18.5 93.474 18.689 ;
     RECT  83.415 13.901 83.697 18.697 ;
     RECT  29.016 14.675 30.762 18.797 ;
     RECT  140.184 18.571 140.598 18.797 ;
     RECT  10.404 14.009 10.422 18.805 ;
     RECT  52.38 13.675 53.082 18.805 ;
     RECT  54.144 17.915 54.414 18.805 ;
     RECT  10.332 18.805 10.422 18.833 ;
     RECT  52.38 18.805 54.414 18.833 ;
     RECT  106.884 16.673 109.242 18.841 ;
     RECT  145.224 18.029 145.242 18.859 ;
     RECT  146.196 18.149 146.214 19.003 ;
     RECT  97.02 18.571 105.75 19.031 ;
     RECT  106.56 18.841 109.242 19.031 ;
     RECT  99.324 19.031 105.75 19.039 ;
     RECT  83.415 18.697 84.186 19.075 ;
     RECT  131.544 17.923 132.642 19.075 ;
     RECT  58.176 13.559 59.022 19.103 ;
     RECT  29.016 18.797 30.69 19.139 ;
     RECT  80.496 17.789 80.514 19.139 ;
     RECT  77.076 16.943 77.094 19.229 ;
     RECT  99.324 19.039 106.542 19.229 ;
     RECT  146.196 19.003 146.25 19.229 ;
     RECT  145.224 18.859 145.314 19.345 ;
     RECT  146.196 19.229 146.214 19.345 ;
     RECT  149.22 19.195 149.238 19.373 ;
     RECT  99.324 19.229 105.75 19.379 ;
     RECT  86.256 17.077 87.498 19.499 ;
     RECT  107.28 19.031 109.242 19.499 ;
     RECT  82.764 19.075 84.186 19.579 ;
     RECT  93.456 18.689 93.474 19.643 ;
     RECT  29.415 19.139 30.69 19.679 ;
     RECT  145.224 19.345 146.214 19.679 ;
     RECT  52.38 18.833 52.398 19.741 ;
     RECT  33.948 17.717 35.478 19.769 ;
     RECT  86.256 19.499 86.274 19.769 ;
     RECT  39.132 17.879 40.497 19.777 ;
     RECT  97.02 19.031 98.334 19.813 ;
     RECT  99.324 19.379 104.094 19.813 ;
     RECT  97.02 19.813 104.094 19.913 ;
     RECT  91.404 18.689 92.538 19.949 ;
     RECT  2.304 17.951 9.234 20.039 ;
     RECT  146.196 19.679 146.214 20.047 ;
     RECT  147.24 18.149 148.497 20.047 ;
     RECT  78.015 17.609 79.11 20.111 ;
     RECT  99.18 19.913 104.094 20.111 ;
     RECT  104.04 20.111 104.094 20.155 ;
     RECT  104.832 19.379 105.75 20.155 ;
     RECT  145.224 19.679 145.422 20.189 ;
     RECT  128.628 16.645 128.646 20.191 ;
     RECT  22.428 14.243 26.766 20.219 ;
     RECT  149.364 20.155 149.382 20.237 ;
     RECT  22.428 20.219 24.894 20.309 ;
     RECT  106.524 19.229 106.542 20.317 ;
     RECT  107.28 19.499 107.874 20.317 ;
     RECT  111.996 18.427 112.014 20.317 ;
     RECT  146.196 20.047 148.497 20.345 ;
     RECT  106.524 20.317 107.874 20.417 ;
     RECT  99.18 20.111 103.05 20.453 ;
     RECT  88.815 18.661 89.766 20.539 ;
     RECT  22.932 20.309 24.894 20.885 ;
     RECT  29.415 19.679 29.697 20.893 ;
     RECT  97.128 19.913 98.334 20.921 ;
     RECT  2.34 20.039 9.234 20.923 ;
     RECT  97.956 20.921 98.334 20.957 ;
     RECT  30.672 19.679 30.69 21.091 ;
     RECT  31.572 14.207 31.59 21.091 ;
     RECT  32.724 12.991 32.742 21.091 ;
     RECT  146.196 20.345 146.214 21.115 ;
     RECT  147.24 20.345 148.497 21.115 ;
     RECT  145.224 20.189 145.242 21.119 ;
     RECT  87.3 19.499 87.498 21.127 ;
     RECT  88.236 20.539 89.766 21.163 ;
     RECT  90.576 18.689 90.594 21.163 ;
     RECT  146.196 21.115 148.497 21.199 ;
     RECT  99.18 20.453 102.978 21.235 ;
     RECT  104.04 20.155 105.75 21.235 ;
     RECT  106.524 20.417 106.542 21.235 ;
     RECT  29.415 20.893 29.898 21.271 ;
     RECT  30.672 21.091 30.798 21.271 ;
     RECT  31.572 21.091 32.742 21.271 ;
     RECT  81.756 17.789 81.774 21.271 ;
     RECT  87.228 21.127 87.498 21.271 ;
     RECT  88.236 21.163 90.594 21.271 ;
     RECT  94.215 18.419 94.497 21.271 ;
     RECT  144.252 21.115 144.27 21.271 ;
     RECT  149.364 21.235 149.382 21.293 ;
     RECT  64.08 13.055 64.17 21.299 ;
     RECT  46.8 14.341 46.818 21.389 ;
     RECT  58.176 19.103 58.194 21.389 ;
     RECT  91.44 19.949 92.538 21.389 ;
     RECT  144.108 21.271 144.27 21.389 ;
     RECT  28.692 21.271 29.898 21.397 ;
     RECT  30.672 21.271 32.742 21.397 ;
     RECT  34.488 19.769 35.478 21.397 ;
     RECT  36.36 21.235 36.378 21.397 ;
     RECT  49.644 19.651 49.662 21.397 ;
     RECT  50.472 13.261 51.297 21.397 ;
     RECT  44.856 20.191 44.874 21.403 ;
     RECT  45.615 15.728 45.897 21.403 ;
     RECT  49.644 21.397 51.297 21.437 ;
     RECT  20.988 17.311 21.546 21.469 ;
     RECT  42.948 12.901 42.966 21.505 ;
     RECT  69.912 13.091 69.93 21.505 ;
     RECT  87.228 21.271 90.594 21.505 ;
     RECT  91.44 21.389 91.53 21.505 ;
     RECT  108.72 19.499 109.242 21.505 ;
     RECT  2.304 20.923 9.234 21.541 ;
     RECT  28.692 21.397 32.742 21.541 ;
     RECT  34.488 21.397 36.99 21.541 ;
     RECT  38.052 21.163 38.07 21.541 ;
     RECT  43.92 13.369 43.938 21.541 ;
     RECT  47.7 13.171 47.718 21.541 ;
     RECT  55.332 17.915 55.35 21.541 ;
     RECT  59.004 19.103 59.022 21.541 ;
     RECT  62.892 13.559 62.91 21.541 ;
     RECT  81.54 21.271 81.774 21.541 ;
     RECT  82.656 19.579 84.186 21.541 ;
     RECT  10.332 18.833 10.35 21.631 ;
     RECT  14.22 14.669 14.238 21.631 ;
     RECT  41.94 19.201 41.958 21.631 ;
     RECT  53.64 18.833 54.414 21.631 ;
     RECT  69.732 21.505 69.93 21.631 ;
     RECT  70.74 13.091 71.514 21.631 ;
     RECT  81.54 21.541 84.186 21.631 ;
     RECT  93.636 21.271 94.497 21.631 ;
     RECT  108.684 21.505 109.458 21.631 ;
     RECT  110.415 15.827 110.697 21.631 ;
     RECT  120.636 13.603 121.497 21.631 ;
     RECT  123.768 16.303 123.786 21.631 ;
     RECT  128.628 20.191 128.826 21.631 ;
     RECT  130.644 13.945 130.662 21.631 ;
     RECT  131.544 19.075 132.822 21.631 ;
     RECT  137.376 13.981 138.258 21.631 ;
     RECT  139.104 19.813 139.122 21.631 ;
     RECT  140.184 18.797 140.202 21.631 ;
     RECT  39.132 19.777 41.022 21.643 ;
     RECT  44.856 21.403 45.897 21.643 ;
     RECT  49.644 21.437 49.662 21.643 ;
     RECT  53.64 21.631 54.45 21.643 ;
     RECT  55.296 21.541 55.35 21.643 ;
     RECT  61.308 13.559 62.097 21.643 ;
     RECT  66.816 13.091 68.418 21.643 ;
     RECT  80.64 21.271 80.766 21.643 ;
     RECT  81.54 21.631 84.798 21.643 ;
     RECT  41.796 21.631 41.958 21.659 ;
     RECT  49.5 21.643 49.662 21.659 ;
     RECT  53.496 21.643 54.45 21.659 ;
     RECT  125.028 18.571 125.046 21.659 ;
     RECT  139.104 21.631 140.202 21.659 ;
     RECT  64.08 21.299 64.098 21.667 ;
     RECT  65.088 13.055 65.934 21.667 ;
     RECT  130.644 21.631 132.822 21.667 ;
     RECT  54.36 21.659 54.45 21.677 ;
     RECT  58.032 21.505 58.05 21.677 ;
     RECT  44.712 21.643 45.897 21.682 ;
     RECT  129.816 19.849 129.834 21.691 ;
     RECT  49.5 21.659 49.518 21.695 ;
     RECT  139.248 21.659 139.59 21.695 ;
     RECT  130.608 21.667 132.822 21.725 ;
     RECT  2.304 21.541 9.45 21.739 ;
     RECT  10.332 21.631 10.422 21.739 ;
     RECT  13.215 15.728 13.497 21.739 ;
     RECT  14.22 21.631 14.31 21.739 ;
     RECT  17.136 17.491 17.658 21.739 ;
     RECT  18.615 17.887 20.034 21.739 ;
     RECT  20.988 21.469 22.194 21.739 ;
     RECT  23.904 20.885 24.894 21.739 ;
     RECT  25.776 20.219 26.766 21.739 ;
     RECT  28.692 21.541 33.354 21.739 ;
     RECT  34.488 21.541 38.07 21.739 ;
     RECT  38.952 21.643 41.022 21.739 ;
     RECT  62.856 21.541 62.91 21.739 ;
     RECT  78.015 20.111 78.966 21.739 ;
     RECT  80.64 21.643 84.798 21.739 ;
     RECT  93.6 21.631 94.497 21.739 ;
     RECT  95.22 18.419 95.238 21.739 ;
     RECT  97.956 20.957 98.046 21.739 ;
     RECT  16.128 14.179 16.146 21.775 ;
     RECT  17.136 21.739 22.194 21.775 ;
     RECT  28.692 21.739 33.714 21.775 ;
     RECT  85.608 19.885 85.626 21.775 ;
     RECT  92.52 21.389 92.538 21.775 ;
     RECT  93.6 21.739 95.238 21.775 ;
     RECT  97.128 20.921 97.146 21.775 ;
     RECT  97.956 21.739 98.406 21.775 ;
     RECT  99.18 21.235 103.014 21.775 ;
     RECT  113.436 21.631 113.454 21.775 ;
     RECT  114.228 17.581 116.097 21.775 ;
     RECT  2.304 21.739 10.422 21.787 ;
     RECT  97.128 21.775 103.014 21.787 ;
     RECT  12.276 13.639 12.294 21.811 ;
     RECT  13.14 21.739 14.31 21.811 ;
     RECT  27.72 14.477 27.738 21.811 ;
     RECT  28.548 21.775 33.714 21.811 ;
     RECT  42.804 21.505 42.966 21.811 ;
     RECT  45.615 21.682 45.897 21.811 ;
     RECT  46.62 21.397 46.782 21.811 ;
     RECT  50.436 21.437 51.297 21.811 ;
     RECT  66.816 21.643 68.778 21.811 ;
     RECT  69.732 21.631 71.514 21.811 ;
     RECT  117.18 19.885 117.198 21.811 ;
     RECT  119.232 18.535 119.25 21.811 ;
     RECT  120.168 21.631 121.497 21.811 ;
     RECT  128.196 21.631 128.826 21.811 ;
     RECT  23.904 21.739 26.766 21.835 ;
     RECT  49.428 21.811 49.446 21.901 ;
     RECT  61.164 21.643 62.097 21.901 ;
     RECT  72.615 15.179 74.862 21.901 ;
     RECT  76.968 19.345 76.986 21.901 ;
     RECT  78.015 21.739 84.798 21.901 ;
     RECT  85.608 21.775 86.274 21.901 ;
     RECT  111.636 20.317 112.014 21.901 ;
     RECT  135.072 14.143 135.306 21.901 ;
     RECT  136.368 16.105 136.386 21.901 ;
     RECT  34.488 21.739 41.022 21.929 ;
     RECT  41.796 21.659 41.886 21.929 ;
     RECT  43.74 21.541 43.938 21.929 ;
     RECT  60.12 17.519 60.138 21.929 ;
     RECT  63.9 21.667 64.098 21.929 ;
     RECT  64.944 21.667 65.934 21.929 ;
     RECT  123.768 21.631 124.254 21.929 ;
     RECT  134.928 21.901 136.386 21.929 ;
     RECT  142.2 17.117 143.19 21.929 ;
     RECT  146.16 21.199 148.497 21.929 ;
     RECT  66.708 21.811 71.514 21.931 ;
     RECT  144.18 21.389 144.27 21.931 ;
     RECT  2.304 21.787 10.458 21.937 ;
     RECT  11.376 14.449 11.394 21.937 ;
     RECT  12.168 21.811 14.31 21.937 ;
     RECT  15.984 21.775 16.146 21.937 ;
     RECT  17.064 21.775 22.194 21.937 ;
     RECT  23.724 21.835 26.766 21.937 ;
     RECT  27.72 21.811 33.714 21.937 ;
     RECT  47.556 21.541 47.718 21.937 ;
     RECT  48.564 19.111 48.582 21.937 ;
     RECT  76.968 21.901 77.022 21.937 ;
     RECT  78.015 21.901 86.274 21.937 ;
     RECT  111.636 21.901 112.482 21.937 ;
     RECT  113.256 21.775 116.097 21.937 ;
     RECT  15.984 21.937 22.194 21.973 ;
     RECT  22.932 20.885 22.95 21.973 ;
     RECT  43.776 21.929 43.938 21.973 ;
     RECT  52.38 19.741 52.434 21.979 ;
     RECT  42.732 21.811 42.966 22.009 ;
     RECT  56.376 17.375 57.222 22.009 ;
     RECT  57.996 21.901 58.014 22.009 ;
     RECT  76.968 21.937 86.274 22.009 ;
     RECT  47.556 21.937 48.582 22.013 ;
     RECT  53.496 21.659 53.514 22.013 ;
     RECT  127.692 21.811 128.826 22.013 ;
     RECT  56.376 22.009 58.014 22.027 ;
     RECT  66.708 21.931 71.658 22.027 ;
     RECT  119.232 21.811 121.497 22.027 ;
     RECT  58.932 21.541 59.022 22.045 ;
     RECT  62.856 21.739 63.126 22.045 ;
     RECT  64.944 21.929 65.898 22.045 ;
     RECT  104.04 21.235 106.542 22.045 ;
     RECT  107.28 20.417 107.874 22.045 ;
     RECT  111.636 21.937 116.097 22.045 ;
     RECT  117.18 21.811 117.234 22.045 ;
     RECT  119.232 22.027 121.77 22.045 ;
     RECT  133.992 18.499 134.01 22.045 ;
     RECT  122.832 21.643 122.85 22.061 ;
     RECT  43.776 21.973 43.974 22.073 ;
     RECT  66.672 22.027 71.658 22.073 ;
     RECT  146.7 21.929 148.497 22.073 ;
     RECT  50.436 21.811 51.354 22.081 ;
     RECT  55.188 21.643 55.35 22.081 ;
     RECT  142.2 21.929 143.097 22.081 ;
     RECT  145.224 21.931 145.242 22.081 ;
     RECT  146.844 22.073 148.497 22.081 ;
     RECT  2.304 21.937 14.31 22.109 ;
     RECT  42.66 22.009 42.966 22.109 ;
     RECT  45.615 21.811 46.782 22.109 ;
     RECT  66.672 22.073 70.758 22.109 ;
     RECT  130.644 21.725 132.822 22.109 ;
     RECT  108.684 21.631 110.697 22.123 ;
     RECT  111.636 22.045 117.234 22.123 ;
     RECT  141.768 22.081 143.097 22.123 ;
     RECT  76.644 22.009 86.274 22.171 ;
     RECT  87.228 21.505 91.53 22.171 ;
     RECT  92.52 21.775 95.238 22.171 ;
     RECT  96.876 21.787 103.014 22.171 ;
     RECT  103.896 22.045 107.874 22.171 ;
     RECT  118.152 14.485 118.17 22.171 ;
     RECT  127.836 22.013 128.826 22.171 ;
     RECT  141.3 22.123 143.097 22.171 ;
     RECT  2.304 22.109 12.186 22.199 ;
     RECT  23.724 21.937 33.714 22.199 ;
     RECT  42.732 22.109 42.858 22.199 ;
     RECT  43.776 22.073 43.938 22.199 ;
     RECT  52.272 21.979 52.434 22.199 ;
     RECT  58.896 22.045 59.022 22.199 ;
     RECT  69.732 22.109 70.758 22.199 ;
     RECT  118.152 22.171 118.314 22.199 ;
     RECT  119.232 22.045 121.914 22.199 ;
     RECT  123.804 21.929 124.254 22.199 ;
     RECT  130.644 22.109 132.297 22.199 ;
     RECT  136.404 22.009 136.422 22.199 ;
     RECT  119.7 22.199 121.914 22.205 ;
     RECT  2.304 22.199 9.45 22.207 ;
     RECT  108.684 22.123 117.234 22.207 ;
     RECT  118.296 22.199 118.314 22.207 ;
     RECT  96.156 22.171 103.014 22.219 ;
     RECT  103.824 22.171 107.946 22.219 ;
     RECT  108.684 22.207 117.378 22.219 ;
     RECT  2.232 22.207 9.45 22.235 ;
     RECT  43.776 22.199 43.83 22.235 ;
     RECT  66.672 22.109 67.914 22.235 ;
     RECT  68.652 22.109 68.958 22.235 ;
     RECT  69.732 22.199 70.578 22.235 ;
     RECT  72.576 21.901 74.862 22.235 ;
     RECT  96.156 22.219 117.378 22.235 ;
     RECT  118.296 22.207 118.53 22.235 ;
     RECT  54.396 21.677 54.45 22.243 ;
     RECT  55.188 22.081 55.422 22.243 ;
     RECT  58.968 22.199 59.022 22.243 ;
     RECT  59.976 21.931 59.994 22.243 ;
     RECT  60.912 21.901 62.097 22.243 ;
     RECT  62.856 22.045 63.162 22.243 ;
     RECT  0.108 22.207 0.126 22.253 ;
     RECT  130.932 22.199 132.297 22.253 ;
     RECT  15.984 21.973 22.95 22.279 ;
     RECT  23.724 22.199 27.63 22.279 ;
     RECT  76.644 22.171 95.238 22.279 ;
     RECT  96.156 22.235 112.482 22.279 ;
     RECT  2.232 22.235 8.406 22.307 ;
     RECT  76.644 22.279 112.482 22.307 ;
     RECT  28.368 22.199 33.714 22.315 ;
     RECT  34.488 21.929 40.986 22.315 ;
     RECT  141.264 22.171 143.097 22.315 ;
     RECT  149.904 22.207 149.922 22.349 ;
     RECT  44.712 21.682 44.874 22.351 ;
     RECT  56.268 22.027 58.014 22.351 ;
     RECT  75.708 22.171 75.726 22.351 ;
     RECT  76.644 22.307 98.01 22.351 ;
     RECT  129.708 21.691 129.834 22.351 ;
     RECT  146.844 22.081 148.626 22.351 ;
     RECT  75.708 22.351 98.01 22.379 ;
     RECT  98.82 22.307 112.482 22.379 ;
     RECT  44.676 22.351 44.874 22.441 ;
     RECT  45.615 22.109 46.386 22.441 ;
     RECT  137.376 21.631 138.33 22.441 ;
     RECT  10.26 22.199 12.186 22.469 ;
     RECT  15.984 22.279 27.63 22.469 ;
     RECT  68.796 22.235 68.958 22.469 ;
     RECT  72.615 22.235 74.862 22.469 ;
     RECT  75.708 22.379 90.342 22.469 ;
     RECT  91.152 22.379 98.01 22.469 ;
     RECT  106.452 22.379 112.482 22.469 ;
     RECT  113.256 22.235 117.378 22.469 ;
     RECT  140.796 22.315 143.097 22.469 ;
     RECT  146.844 22.351 148.914 22.469 ;
     RECT  98.82 22.379 105.714 22.493 ;
     RECT  50.436 22.081 51.39 22.505 ;
     RECT  64.656 22.045 65.898 22.505 ;
     RECT  106.452 22.469 111.51 22.505 ;
     RECT  127.836 22.171 128.898 22.505 ;
     RECT  133.02 22.219 133.038 22.505 ;
     RECT  133.992 22.045 134.118 22.505 ;
     RECT  98.964 22.493 105.714 22.513 ;
     RECT  15.984 22.469 26.766 22.541 ;
     RECT  28.368 22.315 40.986 22.541 ;
     RECT  77.796 22.469 84.618 22.541 ;
     RECT  86.436 22.469 90.342 22.541 ;
     RECT  91.296 22.469 98.01 22.541 ;
     RECT  98.964 22.513 102.042 22.541 ;
     RECT  102.78 22.513 105.714 22.541 ;
     RECT  49.356 21.901 49.446 22.549 ;
     RECT  91.296 22.541 96.174 22.577 ;
     RECT  15.192 14.639 15.21 22.585 ;
     RECT  15.984 22.541 22.734 22.585 ;
     RECT  60.912 22.243 63.162 22.585 ;
     RECT  63.9 21.929 63.918 22.585 ;
     RECT  23.508 22.541 26.766 22.613 ;
     RECT  28.368 22.541 28.53 22.613 ;
     RECT  113.256 22.469 113.634 22.613 ;
     RECT  114.444 22.469 117.378 22.613 ;
     RECT  140.796 22.469 141.714 22.613 ;
     RECT  47.556 22.013 47.718 22.621 ;
     RECT  48.744 22.549 49.446 22.621 ;
     RECT  54.396 22.243 55.422 22.621 ;
     RECT  124.236 22.199 124.254 22.621 ;
     RECT  129.708 22.351 129.87 22.621 ;
     RECT  134.928 21.929 135.666 22.621 ;
     RECT  82.584 22.541 84.618 22.649 ;
     RECT  100.8 22.541 102.042 22.649 ;
     RECT  114.588 22.613 117.378 22.649 ;
     RECT  124.236 22.621 124.434 22.649 ;
     RECT  124.272 22.649 124.434 22.699 ;
     RECT  12.924 22.109 14.31 22.711 ;
     RECT  144.18 21.931 144.45 22.711 ;
     RECT  145.224 22.081 145.71 22.711 ;
     RECT  139.572 21.695 139.59 22.738 ;
     RECT  75.852 22.469 77.022 22.739 ;
     RECT  100.8 22.649 100.926 22.739 ;
     RECT  112.356 22.469 112.482 22.739 ;
     RECT  119.844 22.205 121.914 22.739 ;
     RECT  124.272 22.699 124.866 22.739 ;
     RECT  125.784 17.959 126.897 22.739 ;
     RECT  127.836 22.505 128.214 22.739 ;
     RECT  130.932 22.253 131.058 22.739 ;
     RECT  131.832 22.253 132.297 22.739 ;
     RECT  137.304 22.441 138.33 22.739 ;
     RECT  139.572 22.738 139.626 22.739 ;
     RECT  142.524 22.469 143.097 22.739 ;
     RECT  12.924 22.711 14.382 22.747 ;
     RECT  15.192 22.585 22.734 22.747 ;
     RECT  144.18 22.711 145.71 22.747 ;
     RECT  25.704 22.613 26.766 22.775 ;
     RECT  41.796 21.929 41.814 22.775 ;
     RECT  48.744 22.621 49.662 22.783 ;
     RECT  136.44 22.441 136.458 22.783 ;
     RECT  137.304 22.739 137.754 22.783 ;
     RECT  136.44 22.783 137.754 22.798 ;
     RECT  12.924 22.747 22.734 22.811 ;
     RECT  29.268 22.541 40.986 22.811 ;
     RECT  127.836 22.739 128.07 22.855 ;
     RECT  10.476 22.469 12.186 22.891 ;
     RECT  12.924 22.811 20.862 22.891 ;
     RECT  48.672 22.783 49.662 22.891 ;
     RECT  121.176 22.739 121.914 22.891 ;
     RECT  121.176 22.891 122.31 22.919 ;
     RECT  146.844 22.469 148.77 22.919 ;
     RECT  39.024 22.811 40.986 22.981 ;
     RECT  50.472 22.505 51.39 22.981 ;
     RECT  52.272 22.199 52.398 22.981 ;
     RECT  53.208 22.351 53.37 22.981 ;
     RECT  144.108 22.747 145.71 22.981 ;
     RECT  9.144 22.235 9.45 23.009 ;
     RECT  133.236 22.621 133.398 23.009 ;
     RECT  2.304 22.307 8.406 23.017 ;
     RECT  9.144 23.009 9.342 23.017 ;
     RECT  1.152 21.199 1.17 23.053 ;
     RECT  2.304 23.017 9.342 23.053 ;
     RECT  114.804 22.649 117.378 23.053 ;
     RECT  129.204 22.621 129.87 23.053 ;
     RECT  134.424 22.621 135.666 23.053 ;
     RECT  53.208 22.981 53.55 23.081 ;
     RECT  60.912 22.585 63.918 23.089 ;
     RECT  64.656 22.505 65.61 23.089 ;
     RECT  123.048 22.081 123.066 23.125 ;
     RECT  146.844 22.919 148.734 23.125 ;
     RECT  41.832 22.891 41.85 23.161 ;
     RECT  42.768 22.199 42.858 23.161 ;
     RECT  43.812 22.235 43.83 23.161 ;
     RECT  44.676 22.441 46.386 23.161 ;
     RECT  50.472 22.981 52.398 23.161 ;
     RECT  53.208 23.081 53.478 23.161 ;
     RECT  58.968 22.243 59.994 23.161 ;
     RECT  60.912 23.089 65.61 23.161 ;
     RECT  66.708 22.235 67.914 23.161 ;
     RECT  71.496 22.073 71.658 23.161 ;
     RECT  72.615 22.469 72.897 23.161 ;
     RECT  149.904 23.125 149.922 23.161 ;
     RECT  21.636 22.811 22.734 23.189 ;
     RECT  29.268 22.811 38.214 23.189 ;
     RECT  39.024 22.981 41.022 23.251 ;
     RECT  41.832 23.161 43.83 23.251 ;
     RECT  44.64 23.161 46.386 23.251 ;
     RECT  48.492 22.891 49.662 23.251 ;
     RECT  50.472 23.161 53.478 23.251 ;
     RECT  66.708 23.161 67.95 23.251 ;
     RECT  69.948 22.235 70.398 23.251 ;
     RECT  71.46 23.161 72.897 23.251 ;
     RECT  73.944 22.469 74.862 23.251 ;
     RECT  10.476 22.891 20.862 23.279 ;
     RECT  21.672 23.189 22.734 23.279 ;
     RECT  33.264 23.189 38.214 23.279 ;
     RECT  41.832 23.251 46.746 23.279 ;
     RECT  48.492 23.251 53.478 23.279 ;
     RECT  56.196 22.351 58.014 23.279 ;
     RECT  58.968 23.161 65.61 23.279 ;
     RECT  71.244 23.251 72.954 23.279 ;
     RECT  75.852 22.739 76.77 23.279 ;
     RECT  77.796 22.541 80.802 23.279 ;
     RECT  81.612 22.541 81.702 23.279 ;
     RECT  85.5 22.469 85.59 23.279 ;
     RECT  87.408 22.541 89.478 23.279 ;
     RECT  90.324 22.541 90.342 23.279 ;
     RECT  91.296 22.577 92.286 23.279 ;
     RECT  93.168 22.577 93.33 23.279 ;
     RECT  94.14 22.577 96.174 23.279 ;
     RECT  97.02 22.541 97.038 23.279 ;
     RECT  98.964 22.541 100.062 23.279 ;
     RECT  100.8 22.739 100.818 23.279 ;
     RECT  102.78 22.541 103.842 23.279 ;
     RECT  106.632 22.505 111.51 23.279 ;
     RECT  112.356 22.739 112.374 23.279 ;
     RECT  129.204 23.053 129.906 23.279 ;
     RECT  131.976 22.739 132.297 23.279 ;
     RECT  133.236 23.009 133.254 23.279 ;
     RECT  142.776 22.739 143.097 23.279 ;
     RECT  146.592 23.125 148.734 23.279 ;
     RECT  1.152 23.053 9.342 23.315 ;
     RECT  11.088 23.279 12.258 23.315 ;
     RECT  28.368 22.613 28.494 23.315 ;
     RECT  45.615 23.279 46.746 23.323 ;
     RECT  47.52 22.621 47.718 23.323 ;
     RECT  68.94 22.469 68.958 23.323 ;
     RECT  130.932 22.739 130.95 23.323 ;
     RECT  132.015 23.279 132.297 23.323 ;
     RECT  142.815 23.279 143.097 23.323 ;
     RECT  144.108 22.981 145.818 23.323 ;
     RECT  146.592 23.279 148.698 23.323 ;
     RECT  13.032 23.279 20.754 23.351 ;
     RECT  33.516 23.279 36.126 23.351 ;
     RECT  41.832 23.279 44.838 23.351 ;
     RECT  48.492 23.279 52.65 23.351 ;
     RECT  72.576 23.279 72.954 23.351 ;
     RECT  58.968 23.279 60.39 23.359 ;
     RECT  23.508 22.613 24.606 23.395 ;
     RECT  27.504 22.469 27.63 23.395 ;
     RECT  28.368 23.315 28.458 23.395 ;
     RECT  54.288 22.621 55.422 23.395 ;
     RECT  56.196 23.279 57.33 23.395 ;
     RECT  61.164 23.279 65.61 23.395 ;
     RECT  66.708 23.251 68.094 23.395 ;
     RECT  68.868 23.323 68.958 23.395 ;
     RECT  69.768 23.251 70.398 23.395 ;
     RECT  71.244 23.279 71.73 23.395 ;
     RECT  73.692 23.251 74.862 23.395 ;
     RECT  114.804 23.053 117.594 23.395 ;
     RECT  129.204 23.279 129.258 23.395 ;
     RECT  33.588 23.351 36.126 23.405 ;
     RECT  144.108 23.323 148.698 23.405 ;
     RECT  23.472 23.395 24.858 23.431 ;
     RECT  25.704 22.775 26.658 23.431 ;
     RECT  27.504 23.395 28.458 23.431 ;
     RECT  29.268 23.189 32.382 23.431 ;
     RECT  45.615 23.323 47.718 23.431 ;
     RECT  48.492 23.351 49.626 23.431 ;
     RECT  66.708 23.395 68.958 23.431 ;
     RECT  69.768 23.395 71.73 23.431 ;
     RECT  73.656 23.395 74.862 23.431 ;
     RECT  77.796 23.279 79.398 23.431 ;
     RECT  82.584 22.649 82.602 23.431 ;
     RECT  83.415 22.649 84.618 23.431 ;
     RECT  86.436 22.541 86.562 23.431 ;
     RECT  94.14 23.279 94.842 23.431 ;
     RECT  95.76 23.279 96.174 23.431 ;
     RECT  97.956 22.541 98.01 23.431 ;
     RECT  99.432 23.279 100.062 23.431 ;
     RECT  101.988 22.649 102.042 23.431 ;
     RECT  103.464 23.279 103.842 23.431 ;
     RECT  104.688 22.541 105.714 23.431 ;
     RECT  113.436 22.613 113.634 23.431 ;
     RECT  114.66 23.395 117.594 23.431 ;
     RECT  126.54 22.739 126.897 23.431 ;
     RECT  127.8 22.855 128.07 23.431 ;
     RECT  134.424 23.053 135.738 23.431 ;
     RECT  138.564 22.747 138.582 23.431 ;
     RECT  141.12 22.613 141.714 23.431 ;
     RECT  13.032 23.351 18.897 23.507 ;
     RECT  54.288 23.395 57.33 23.507 ;
     RECT  72.576 23.351 72.897 23.507 ;
     RECT  88.092 23.279 89.097 23.507 ;
     RECT  114.66 23.431 117.63 23.507 ;
     RECT  144.108 23.405 148.497 23.507 ;
     RECT  23.472 23.431 26.658 23.521 ;
     RECT  27.396 23.431 28.458 23.521 ;
     RECT  10.08 23.395 10.206 23.549 ;
     RECT  11.088 23.315 11.502 23.549 ;
     RECT  14.112 23.507 18.81 23.549 ;
     RECT  21.672 23.279 21.942 23.549 ;
     RECT  23.472 23.521 28.458 23.549 ;
     RECT  29.196 23.431 32.382 23.549 ;
     RECT  34.02 23.405 36.126 23.549 ;
     RECT  37.26 23.279 38.214 23.549 ;
     RECT  39.024 23.251 41.058 23.549 ;
     RECT  44.568 23.351 44.838 23.549 ;
     RECT  45.615 23.431 49.626 23.549 ;
     RECT  50.508 23.351 51.57 23.549 ;
     RECT  52.452 23.351 52.65 23.549 ;
     RECT  54.288 23.507 56.574 23.549 ;
     RECT  58.248 23.359 60.39 23.549 ;
     RECT  61.164 23.395 65.826 23.549 ;
     RECT  66.708 23.431 71.73 23.549 ;
     RECT  73.656 23.431 75.582 23.549 ;
     RECT  76.536 23.279 76.77 23.549 ;
     RECT  77.508 23.431 79.398 23.549 ;
     RECT  80.352 23.279 80.406 23.549 ;
     RECT  81.144 23.431 81.342 23.549 ;
     RECT  82.296 23.431 85.194 23.549 ;
     RECT  86.148 23.431 87.138 23.549 ;
     RECT  88.092 23.507 88.974 23.549 ;
     RECT  90.792 23.431 91.026 23.549 ;
     RECT  91.908 23.279 91.962 23.549 ;
     RECT  92.7 23.431 92.898 23.549 ;
     RECT  93.852 23.431 94.842 23.549 ;
     RECT  95.76 23.431 96.75 23.549 ;
     RECT  97.704 23.431 98.694 23.549 ;
     RECT  99.432 23.431 100.566 23.549 ;
     RECT  101.7 23.431 102.51 23.549 ;
     RECT  103.464 23.431 106.362 23.549 ;
     RECT  107.316 23.279 111.222 23.549 ;
     RECT  111.96 23.431 112.194 23.549 ;
     RECT  114.66 23.507 115.905 23.549 ;
     RECT  116.64 23.507 117.63 23.549 ;
     RECT  118.512 22.235 118.53 23.549 ;
     RECT  119.844 22.739 120.258 23.549 ;
     RECT  122.292 22.919 122.31 23.549 ;
     RECT  123.048 23.125 123.138 23.549 ;
     RECT  124.272 22.739 124.29 23.549 ;
     RECT  126.54 23.431 128.07 23.549 ;
     RECT  130.428 23.323 130.95 23.549 ;
     RECT  133.164 23.431 133.182 23.549 ;
     RECT  134.316 23.431 135.738 23.549 ;
     RECT  136.8 22.798 137.754 23.549 ;
     RECT  138.564 23.431 138.654 23.549 ;
     RECT  139.608 22.739 139.626 23.549 ;
     RECT  141.012 23.431 141.714 23.549 ;
     RECT  142.815 23.323 143.19 23.549 ;
     RECT  144.108 23.507 148.305 23.549 ;
     RECT  121.176 22.919 121.497 23.557 ;
     RECT  125.1 22.891 125.226 23.557 ;
     RECT  129.096 23.395 129.258 23.557 ;
     RECT  136.98 23.549 137.754 23.557 ;
     RECT  1.152 23.315 8.37 23.585 ;
     RECT  14.94 23.549 16.902 23.585 ;
     RECT  23.616 23.549 25.65 23.585 ;
     RECT  26.496 23.549 28.458 23.585 ;
     RECT  29.196 23.549 30.366 23.585 ;
     RECT  39.024 23.549 40.986 23.585 ;
     RECT  41.832 23.351 42.894 23.585 ;
     RECT  44.64 23.549 44.838 23.585 ;
     RECT  45.615 23.549 46.602 23.585 ;
     RECT  47.484 23.549 47.682 23.585 ;
     RECT  48.42 23.549 49.626 23.585 ;
     RECT  51.015 23.549 51.57 23.585 ;
     RECT  54.576 23.549 55.386 23.585 ;
     RECT  58.248 23.549 58.446 23.585 ;
     RECT  64.188 23.549 65.754 23.585 ;
     RECT  66.708 23.549 67.95 23.585 ;
     RECT  68.868 23.549 69.786 23.585 ;
     RECT  107.352 23.549 111.222 23.585 ;
     RECT  145.872 23.549 148.305 23.585 ;
     RECT  9.18 23.315 9.342 23.621 ;
     RECT  21.672 23.549 21.87 23.621 ;
     RECT  26.496 23.585 26.73 23.621 ;
     RECT  29.415 23.585 30.366 23.621 ;
     RECT  56.34 23.549 56.574 23.621 ;
     RECT  59.22 23.549 59.382 23.621 ;
     RECT  4.284 23.585 5.994 23.657 ;
     RECT  9.18 23.621 9.306 23.657 ;
     RECT  76.572 23.549 76.77 23.665 ;
     RECT  77.508 23.549 79.218 23.665 ;
     RECT  101.7 23.549 102.33 23.665 ;
     RECT  113.148 23.431 113.634 23.665 ;
     RECT  118.908 23.557 118.926 23.665 ;
     RECT  120.816 23.557 121.497 23.665 ;
     RECT  124.668 23.557 125.226 23.665 ;
     RECT  130.464 23.549 130.95 23.665 ;
     RECT  132.015 23.323 132.39 23.665 ;
     RECT  140.076 23.557 140.094 23.665 ;
     RECT  37.26 23.549 38.07 23.693 ;
     RECT  73.692 23.549 75.366 23.693 ;
     RECT  4.356 23.657 4.482 23.729 ;
     RECT  5.22 23.657 5.994 23.729 ;
     RECT  16.776 23.585 16.902 23.729 ;
     RECT  17.712 23.549 18.81 23.729 ;
     RECT  19.8 23.351 20.754 23.729 ;
     RECT  27.576 23.585 28.458 23.729 ;
     RECT  69.696 23.585 69.786 23.729 ;
     RECT  6.804 23.585 8.37 23.741 ;
     RECT  74.628 23.693 75.366 23.741 ;
     RECT  84.24 23.549 84.978 23.741 ;
     RECT  86.184 23.549 86.922 23.741 ;
     RECT  90.792 23.549 90.81 23.741 ;
     RECT  95.796 23.549 96.534 23.741 ;
     RECT  105.015 23.549 106.146 23.741 ;
     RECT  109.296 23.585 111.222 23.741 ;
     RECT  111.96 23.549 111.978 23.741 ;
     RECT  120.816 23.665 121.698 23.741 ;
     RECT  130.464 23.665 131.202 23.741 ;
     RECT  139.104 23.665 139.122 23.741 ;
     RECT  140.076 23.665 140.814 23.741 ;
     RECT  144.792 23.549 144.81 23.741 ;
     RECT  7.236 23.741 8.37 23.777 ;
     RECT  13.032 23.507 13.305 23.777 ;
     RECT  23.616 23.585 24.606 23.777 ;
     RECT  29.415 23.621 29.574 23.777 ;
     RECT  34.2 23.549 35.262 23.777 ;
     RECT  39.96 23.585 40.986 23.777 ;
     RECT  45.615 23.585 45.954 23.777 ;
     RECT  51.015 23.585 51.534 23.777 ;
     RECT  56.34 23.621 56.505 23.777 ;
     RECT  61.164 23.549 61.974 23.777 ;
     RECT  66.924 23.585 67.95 23.777 ;
     RECT  72.576 23.507 72.705 23.777 ;
     RECT  76.572 23.665 79.218 23.777 ;
     RECT  82.332 23.549 83.505 23.777 ;
     RECT  88.092 23.549 88.905 23.777 ;
     RECT  93.888 23.549 94.662 23.777 ;
     RECT  105.015 23.741 105.462 23.777 ;
     RECT  110.415 23.741 111.222 23.777 ;
     RECT  115.056 23.549 115.905 23.777 ;
     RECT  120.816 23.741 121.305 23.777 ;
     RECT  126.54 23.549 127.386 23.777 ;
     RECT  132.015 23.665 133.002 23.777 ;
     RECT  136.98 23.557 138.186 23.777 ;
     RECT  142.815 23.549 142.974 23.777 ;
     RECT  147.78 23.585 148.305 23.777 ;
     RECT  0.108 23.131 0.126 23.789 ;
     RECT  126.54 23.777 126.63 23.855 ;
     RECT  142.956 23.777 142.974 23.885 ;
     RECT  99.432 23.549 100.386 23.927 ;
     RECT  1.152 23.585 3.402 23.933 ;
     RECT  15.948 23.585 15.966 23.933 ;
     RECT  19.8 23.729 19.818 23.933 ;
     RECT  25.632 23.585 25.65 23.933 ;
     RECT  27.576 23.729 27.594 23.933 ;
     RECT  31.32 23.549 31.338 23.933 ;
     RECT  35.244 23.777 35.262 23.933 ;
     RECT  40.968 23.777 40.986 23.933 ;
     RECT  44.82 23.585 44.838 23.933 ;
     RECT  60.372 23.549 60.39 23.933 ;
     RECT  61.956 23.777 61.974 23.933 ;
     RECT  81.144 23.549 81.162 23.933 ;
     RECT  94.644 23.777 94.662 23.933 ;
     RECT  99.648 23.927 100.386 23.933 ;
     RECT  101.592 23.665 102.33 23.933 ;
     RECT  117 23.549 117.45 23.933 ;
     RECT  127.368 23.777 127.386 23.933 ;
     RECT  132.372 23.777 133.002 23.933 ;
     RECT  136.98 23.777 136.998 23.933 ;
     RECT  145.872 23.585 146.61 23.933 ;
     RECT  4.356 23.729 4.374 23.981 ;
     RECT  69.768 23.729 69.786 23.981 ;
     RECT  71.712 23.549 71.73 23.981 ;
     RECT  1.152 23.933 2.574 24.029 ;
     RECT  2.556 24.029 2.574 24.317 ;
     RECT  149.724 23.161 149.922 24.413 ;
     RECT  10.188 23.549 10.206 24.509 ;
     RECT  12.24 23.315 12.258 24.509 ;
     RECT  23.616 23.777 23.634 24.509 ;
     RECT  37.26 23.693 37.278 24.509 ;
     RECT  39.024 23.585 39.042 24.509 ;
     RECT  42.876 23.585 42.894 24.509 ;
     RECT  48.96 23.585 49.626 24.509 ;
     RECT  52.632 23.549 52.65 24.509 ;
     RECT  54.576 23.585 54.594 24.509 ;
     RECT  56.34 23.777 56.358 24.509 ;
     RECT  58.428 23.585 58.446 24.509 ;
     RECT  64.188 23.585 64.206 24.509 ;
     RECT  65.016 23.585 65.754 24.509 ;
     RECT  67.932 23.777 67.95 24.509 ;
     RECT  73.692 23.693 73.71 24.509 ;
     RECT  1.152 24.029 1.71 24.557 ;
     RECT  1.692 24.557 1.71 24.797 ;
     RECT  76.572 23.777 77.31 25.133 ;
     RECT  82.332 23.777 83.034 25.133 ;
     RECT  88.092 23.777 88.794 25.133 ;
     RECT  97.74 23.549 98.478 25.133 ;
     RECT  103.5 23.549 104.202 25.133 ;
     RECT  107.352 23.585 108.09 25.133 ;
     RECT  115.056 23.777 115.542 25.133 ;
     RECT  118.908 23.665 119.646 25.133 ;
     RECT  123.516 23.665 123.534 25.133 ;
     RECT  128.52 23.557 129.258 25.133 ;
     RECT  8.352 23.777 8.37 25.805 ;
     RECT  14.112 23.549 14.13 25.805 ;
     RECT  18.144 23.729 18.81 25.805 ;
     RECT  21.852 23.621 21.87 25.805 ;
     RECT  29.556 23.777 29.574 25.805 ;
     RECT  78.48 23.777 79.218 25.805 ;
     RECT  92.7 23.549 92.718 25.805 ;
     RECT  113.148 23.665 113.886 25.805 ;
     RECT  124.668 23.665 125.334 25.805 ;
     RECT  134.316 23.549 135.054 25.805 ;
     RECT  22.716 23.279 22.734 25.861 ;
     RECT  41.832 23.585 41.85 25.861 ;
     RECT  43.74 23.351 43.758 25.861 ;
     RECT  45.936 23.777 45.954 25.861 ;
     RECT  72.576 23.777 72.594 25.861 ;
    LAYER M4 ;
     RECT  1.436 25.824 1.523 25.848 ;
     RECT  0.084 1.104 1.721 1.128 ;
     RECT  0.06 1.128 1.721 1.392 ;
     RECT  0.084 1.392 1.721 1.416 ;
     RECT  0.06 1.416 1.721 1.632 ;
     RECT  0.084 1.632 1.721 1.656 ;
     RECT  0.06 1.656 1.721 1.872 ;
     RECT  0.084 1.872 1.721 1.896 ;
     RECT  0.06 1.896 1.721 2.16 ;
     RECT  0.084 2.16 1.721 2.184 ;
     RECT  0.06 2.184 1.721 2.4 ;
     RECT  0.084 2.4 1.721 2.424 ;
     RECT  0.06 2.424 1.721 2.64 ;
     RECT  0.084 2.64 1.721 2.664 ;
     RECT  0.06 2.664 1.721 2.928 ;
     RECT  0.084 2.928 1.721 2.952 ;
     RECT  0.06 2.952 1.721 3.168 ;
     RECT  0.084 3.168 1.721 3.192 ;
     RECT  0.06 3.192 1.721 3.408 ;
     RECT  0.084 3.408 1.721 3.432 ;
     RECT  0.06 3.432 1.721 3.696 ;
     RECT  0.084 3.696 1.721 3.72 ;
     RECT  0.06 3.72 1.721 3.936 ;
     RECT  0.084 3.936 1.721 3.96 ;
     RECT  0.06 3.96 1.721 4.224 ;
     RECT  0.084 4.224 1.721 4.248 ;
     RECT  0.06 4.248 1.721 4.464 ;
     RECT  0.084 4.464 1.721 4.488 ;
     RECT  0.06 4.488 1.721 4.704 ;
     RECT  0.084 4.704 1.721 4.728 ;
     RECT  0.06 4.728 1.721 4.992 ;
     RECT  0.084 4.992 1.721 5.016 ;
     RECT  0.06 5.016 1.721 5.232 ;
     RECT  0.084 5.232 1.721 5.256 ;
     RECT  0.06 5.256 1.721 5.472 ;
     RECT  0.084 5.472 1.721 5.496 ;
     RECT  0.06 5.496 1.721 5.76 ;
     RECT  0.084 5.76 1.721 5.784 ;
     RECT  0.06 5.784 1.721 6 ;
     RECT  0.084 6 1.721 6.024 ;
     RECT  0.06 6.024 1.721 6.24 ;
     RECT  0.084 6.24 1.721 6.264 ;
     RECT  0.06 6.264 1.721 6.528 ;
     RECT  0.084 6.528 1.721 6.552 ;
     RECT  0.06 6.552 1.721 6.768 ;
     RECT  0.084 6.768 1.721 6.792 ;
     RECT  0.06 6.792 1.721 7.056 ;
     RECT  0.084 7.056 1.721 7.08 ;
     RECT  0.06 7.08 1.721 7.296 ;
     RECT  0.084 7.296 1.721 7.32 ;
     RECT  0.06 7.32 1.721 7.536 ;
     RECT  0.084 7.536 1.721 7.56 ;
     RECT  0.06 7.56 1.721 7.824 ;
     RECT  0.084 7.824 1.721 7.848 ;
     RECT  0.06 7.848 1.721 8.064 ;
     RECT  0.084 8.064 1.721 8.088 ;
     RECT  0.06 8.088 1.721 8.304 ;
     RECT  0.084 8.304 1.721 8.328 ;
     RECT  0.06 8.328 1.721 8.592 ;
     RECT  0.084 8.592 1.721 8.616 ;
     RECT  0.06 8.616 1.721 8.832 ;
     RECT  0.084 8.832 1.721 8.856 ;
     RECT  0.06 8.856 1.721 9.072 ;
     RECT  0.084 9.072 1.721 9.096 ;
     RECT  0.06 9.096 1.721 9.36 ;
     RECT  0.084 9.36 1.721 9.384 ;
     RECT  0.06 9.384 1.721 9.6 ;
     RECT  0.084 9.6 1.721 9.624 ;
     RECT  0.06 9.624 1.721 9.84 ;
     RECT  0.084 9.84 1.721 9.864 ;
     RECT  0.06 9.864 1.721 10.128 ;
     RECT  0.084 10.128 1.721 10.152 ;
     RECT  0.06 10.152 1.721 10.368 ;
     RECT  0.084 10.368 1.721 10.392 ;
     RECT  0.06 10.392 1.721 10.656 ;
     RECT  0.084 10.656 1.721 10.68 ;
     RECT  0.06 10.68 1.721 10.896 ;
     RECT  0.084 10.896 1.721 10.92 ;
     RECT  0.06 10.92 1.721 11.136 ;
     RECT  0.084 11.136 1.721 11.16 ;
     RECT  0.06 11.16 1.721 11.424 ;
     RECT  0.084 11.424 1.721 11.448 ;
     RECT  0.06 11.448 1.721 11.664 ;
     RECT  0.084 11.664 1.721 11.688 ;
     RECT  0.06 11.688 1.721 11.904 ;
     RECT  0.084 11.904 1.721 11.928 ;
     RECT  0.06 11.928 1.721 12.192 ;
     RECT  0.084 12.192 1.721 12.216 ;
     RECT  0.06 12.216 1.721 12.432 ;
     RECT  0.084 12.432 1.721 12.456 ;
     RECT  0.06 12.456 1.721 12.672 ;
     RECT  0.084 12.672 1.721 12.696 ;
     RECT  0.06 12.696 1.721 12.96 ;
     RECT  0.084 12.96 1.721 12.984 ;
     RECT  0.06 12.984 1.721 13.2 ;
     RECT  0.084 13.2 1.721 13.224 ;
     RECT  0.06 13.224 1.721 13.44 ;
     RECT  0.084 13.44 1.721 13.464 ;
     RECT  0.06 13.464 1.721 13.728 ;
     RECT  0.084 13.728 1.721 13.752 ;
     RECT  0.06 13.752 1.721 13.968 ;
     RECT  0.084 13.968 1.721 13.992 ;
     RECT  0.06 13.992 1.721 14.256 ;
     RECT  0.084 14.256 1.721 14.28 ;
     RECT  0.06 14.28 1.721 14.496 ;
     RECT  0.084 14.496 1.721 14.52 ;
     RECT  0.06 14.52 1.721 14.736 ;
     RECT  0.084 14.736 1.721 14.76 ;
     RECT  0.06 14.76 1.721 15.024 ;
     RECT  0.084 15.024 1.721 15.048 ;
     RECT  0.06 15.048 1.721 15.264 ;
     RECT  0.084 15.264 1.721 15.288 ;
     RECT  0.06 15.288 1.721 15.504 ;
     RECT  0.084 15.504 1.721 15.528 ;
     RECT  0.06 15.528 1.721 15.792 ;
     RECT  0.084 15.792 1.721 15.816 ;
     RECT  0.06 15.816 1.721 16.032 ;
     RECT  0.084 16.032 1.721 16.056 ;
     RECT  0.06 16.056 1.721 16.272 ;
     RECT  0.084 16.272 1.721 16.296 ;
     RECT  0.06 16.296 1.721 16.56 ;
     RECT  0.084 16.56 1.721 16.584 ;
     RECT  0.06 16.584 1.721 16.8 ;
     RECT  0.084 16.8 1.721 16.824 ;
     RECT  0.06 16.824 1.721 17.04 ;
     RECT  0.084 17.04 1.721 17.064 ;
     RECT  0.06 17.064 1.721 17.328 ;
     RECT  0.084 17.328 1.721 17.352 ;
     RECT  0.06 17.352 1.721 17.568 ;
     RECT  0.084 17.568 1.721 17.592 ;
     RECT  0.06 17.592 1.721 17.856 ;
     RECT  0.084 17.856 1.721 17.88 ;
     RECT  0.06 17.88 1.721 18.096 ;
     RECT  0.084 18.096 1.721 18.12 ;
     RECT  0.06 18.12 1.721 18.336 ;
     RECT  0.084 18.336 1.721 18.36 ;
     RECT  0.06 18.36 1.721 18.624 ;
     RECT  0.084 18.624 1.721 18.648 ;
     RECT  0.06 18.648 1.721 18.864 ;
     RECT  0.084 18.864 1.721 18.888 ;
     RECT  0.06 18.888 1.721 19.104 ;
     RECT  0.084 19.104 1.721 19.128 ;
     RECT  0.06 19.128 1.721 19.392 ;
     RECT  0.084 19.392 1.721 19.416 ;
     RECT  0.06 19.416 1.721 19.632 ;
     RECT  0.084 19.632 1.721 19.656 ;
     RECT  0.06 19.656 1.721 19.872 ;
     RECT  0.084 19.872 1.721 19.896 ;
     RECT  0.06 19.896 1.721 20.16 ;
     RECT  0.084 20.16 1.721 20.184 ;
     RECT  0.06 20.184 1.721 20.4 ;
     RECT  0.084 20.4 1.721 20.424 ;
     RECT  0.06 20.424 1.721 20.688 ;
     RECT  0.084 20.688 1.721 20.712 ;
     RECT  0.06 20.712 1.721 20.928 ;
     RECT  0.084 20.928 1.721 20.952 ;
     RECT  0.06 20.952 1.721 21.168 ;
     RECT  0.084 21.168 1.721 21.192 ;
     RECT  0.06 21.192 1.721 21.456 ;
     RECT  0.084 21.456 1.721 21.48 ;
     RECT  0.06 21.48 1.721 21.696 ;
     RECT  0.084 21.696 1.721 21.72 ;
     RECT  0.06 21.72 1.721 21.936 ;
     RECT  0.084 21.936 1.721 21.96 ;
     RECT  0.06 21.96 1.721 22.224 ;
     RECT  0.084 22.224 1.721 22.248 ;
     RECT  0.06 22.248 1.721 22.464 ;
     RECT  0.084 22.464 1.721 22.488 ;
     RECT  0.06 22.488 1.721 22.704 ;
     RECT  0.084 22.704 1.721 22.728 ;
     RECT  0.06 22.728 1.721 22.992 ;
     RECT  0.084 22.992 1.721 23.016 ;
     RECT  0.06 23.016 1.721 23.232 ;
     RECT  0.084 23.232 1.721 23.256 ;
     RECT  0.06 23.256 1.721 23.472 ;
     RECT  0.084 23.472 1.721 23.496 ;
     RECT  0.06 23.496 1.721 23.76 ;
     RECT  0.084 23.76 1.721 23.784 ;
     RECT  0.06 23.784 1.721 24 ;
     RECT  0.084 24 1.721 24.024 ;
     RECT  0.06 24.024 1.721 24.288 ;
     RECT  0.084 24.288 1.721 24.312 ;
     RECT  0.06 24.312 1.721 24.528 ;
     RECT  0.084 24.528 1.721 24.552 ;
     RECT  0.06 24.552 1.721 24.768 ;
     RECT  0.084 24.768 1.721 24.792 ;
     RECT  1.721 1.104 2.585 24.312 ;
     RECT  2.585 1.104 2.621 23.928 ;
     RECT  2.621 2.418 2.704 23.928 ;
     RECT  2.704 14.4 2.729 15.816 ;
     RECT  2.729 14.496 2.765 15.816 ;
     RECT  2.704 23.664 2.765 23.928 ;
     RECT  2.621 1.104 2.801 1.128 ;
     RECT  2.704 2.688 2.801 4.488 ;
     RECT  2.704 9.072 2.837 10.392 ;
     RECT  2.704 11.664 2.837 11.688 ;
     RECT  2.765 14.736 2.837 15.528 ;
     RECT  2.704 19.536 2.837 20.424 ;
     RECT  2.837 14.736 2.873 14.76 ;
     RECT  2.765 23.664 2.873 23.688 ;
     RECT  2.704 12.864 2.909 13.08 ;
     RECT  2.704 5.76 3.017 5.784 ;
     RECT  2.837 9.072 3.125 9.624 ;
     RECT  2.801 2.688 3.233 4.44 ;
     RECT  3.125 9.072 3.233 9.096 ;
     RECT  2.704 16.8 3.269 16.824 ;
     RECT  3.233 2.688 3.593 3.432 ;
     RECT  2.837 20.16 3.913 20.424 ;
     RECT  3.913 20.016 3.949 20.424 ;
     RECT  3.949 19.2 3.985 20.424 ;
     RECT  3.769 8.4 4.019 8.424 ;
     RECT  3.593 2.784 4.097 3.432 ;
     RECT  2.704 21.648 4.097 21.816 ;
     RECT  3.985 19.056 4.165 20.424 ;
     RECT  4.165 18.768 4.213 20.424 ;
     RECT  4.213 18.768 4.259 21.144 ;
     RECT  4.165 23.28 4.316 23.304 ;
     RECT  4.316 23.28 4.403 23.976 ;
     RECT  3.233 4.416 4.489 4.44 ;
     RECT  2.704 7.392 4.525 7.416 ;
     RECT  4.489 4.416 4.529 5.16 ;
     RECT  4.357 1.728 4.565 1.752 ;
     RECT  4.525 7.392 4.565 7.608 ;
     RECT  4.525 10.848 4.693 10.872 ;
     RECT  2.909 13.056 4.705 13.08 ;
     RECT  4.561 15.456 4.705 15.48 ;
     RECT  4.403 23.28 4.709 23.304 ;
     RECT  4.652 9.36 4.739 9.384 ;
     RECT  4.705 15.456 4.741 15.72 ;
     RECT  4.705 11.952 4.813 13.08 ;
     RECT  4.259 19.056 4.817 21.144 ;
     RECT  4.529 5.136 4.853 5.16 ;
     RECT  4.741 15.456 4.993 16.008 ;
     RECT  4.097 3.024 5.213 3.432 ;
     RECT  4.693 10.752 5.281 10.872 ;
     RECT  4.813 11.952 5.281 13.704 ;
     RECT  4.817 19.2 5.425 21.144 ;
     RECT  4.957 22.416 5.425 22.44 ;
     RECT  5.425 19.2 5.429 22.44 ;
     RECT  5.281 10.752 5.497 13.704 ;
     RECT  4.565 7.584 5.605 7.608 ;
     RECT  5.029 5.232 5.677 5.256 ;
     RECT  5.605 6.816 5.717 7.608 ;
     RECT  4.993 15.456 5.749 16.344 ;
     RECT  5.213 3.024 5.821 3.288 ;
     RECT  5.497 10.272 5.821 13.704 ;
     RECT  5.821 9.936 5.825 13.704 ;
     RECT  5.429 19.344 5.825 22.44 ;
     RECT  5.749 15.312 5.893 16.344 ;
     RECT  5.717 6.816 6.077 7.272 ;
     RECT  5.825 19.344 6.275 19.944 ;
     RECT  6.073 8.736 6.277 8.76 ;
     RECT  5.825 9.936 6.277 11.256 ;
     RECT  6.277 8.736 6.365 11.256 ;
     RECT  6.325 1.728 6.409 1.752 ;
     RECT  6.275 19.344 6.433 19.368 ;
     RECT  6.433 19.248 6.541 19.368 ;
     RECT  5.821 2.88 6.572 3.288 ;
     RECT  6.572 2.88 6.659 3.576 ;
     RECT  6.365 8.736 6.689 9.672 ;
     RECT  6.277 23.712 6.833 23.736 ;
     RECT  5.825 21.648 6.865 22.44 ;
     RECT  6.541 18.816 7.081 19.368 ;
     RECT  7.081 18.528 7.1 19.368 ;
     RECT  5.893 14.976 7.109 16.344 ;
     RECT  5.677 5.232 7.117 5.736 ;
     RECT  5.825 12.336 7.117 13.704 ;
     RECT  7.109 14.976 7.117 17.112 ;
     RECT  6.865 21.648 7.117 23.256 ;
     RECT  7.117 12.336 7.141 17.112 ;
     RECT  7.1 18.384 7.141 19.368 ;
     RECT  6.365 11.136 7.369 11.256 ;
     RECT  7.141 12.336 7.369 19.368 ;
     RECT  6.659 2.88 7.808 3.432 ;
     RECT  7.117 5.232 7.808 5.88 ;
     RECT  6.077 7.248 7.808 7.272 ;
     RECT  6.689 8.736 7.808 8.76 ;
     RECT  7.369 11.136 7.808 19.368 ;
     RECT  6.853 20.448 7.808 20.472 ;
     RECT  7.117 21.504 7.808 23.256 ;
     RECT  7.808 2.148 7.912 23.772 ;
     RECT  7.912 2.418 8.104 23.502 ;
     RECT  8.104 17.616 8.201 18.552 ;
     RECT  8.197 0.096 8.291 0.12 ;
     RECT  8.104 4.416 8.339 5.88 ;
     RECT  8.104 20.736 8.339 22.872 ;
     RECT  8.104 11.232 8.345 13.704 ;
     RECT  8.201 17.616 8.381 17.64 ;
     RECT  8.197 25.776 8.381 25.8 ;
     RECT  8.339 20.736 8.531 22.2 ;
     RECT  8.104 3.072 9.097 3.144 ;
     RECT  8.339 4.416 9.097 5.736 ;
     RECT  9.097 3.072 9.281 5.736 ;
     RECT  10.133 1.728 10.217 1.752 ;
     RECT  10.117 24.48 10.217 24.504 ;
     RECT  8.531 21.744 11.185 22.2 ;
     RECT  9.281 3.84 11.189 5.736 ;
     RECT  11.185 21.744 12.085 22.776 ;
     RECT  12.085 0.096 12.179 0.12 ;
     RECT  11.189 4.416 12.229 5.736 ;
     RECT  8.345 11.424 12.229 13.704 ;
     RECT  8.104 14.736 12.229 16.392 ;
     RECT  12.037 24.48 12.269 24.504 ;
     RECT  12.229 3.696 13.208 5.736 ;
     RECT  12.229 11.376 13.208 16.392 ;
     RECT  12.085 21.744 13.208 22.872 ;
     RECT  13.208 2.148 13.312 23.772 ;
     RECT  13.312 2.418 13.504 23.502 ;
     RECT  13.504 3.696 13.667 5.256 ;
     RECT  14.029 0.096 14.113 0.12 ;
     RECT  13.957 25.776 14.141 25.8 ;
     RECT  13.504 11.952 14.243 16.392 ;
     RECT  14.243 12.336 14.723 16.392 ;
     RECT  13.504 22.848 14.933 22.872 ;
     RECT  13.667 3.984 15.185 5.256 ;
     RECT  15.877 23.904 15.977 23.928 ;
     RECT  15.037 22.8 16.013 22.824 ;
     RECT  15.937 0.096 16.021 0.12 ;
     RECT  16.189 22.128 17.345 22.152 ;
     RECT  17.917 0.096 18.001 0.12 ;
     RECT  17.845 25.776 18.173 25.8 ;
     RECT  15.185 3.984 18.349 4.152 ;
     RECT  18.349 3.408 18.608 4.152 ;
     RECT  15.185 5.232 18.608 5.256 ;
     RECT  14.723 12.336 18.608 13.704 ;
     RECT  14.723 14.736 18.608 16.392 ;
     RECT  17.449 22.512 18.608 22.536 ;
     RECT  18.608 2.148 18.712 23.772 ;
     RECT  18.712 2.418 18.904 23.502 ;
     RECT  18.904 3.408 19.181 4.152 ;
     RECT  18.904 21.84 19.397 22.536 ;
     RECT  19.745 23.904 19.829 23.928 ;
     RECT  19.861 1.728 19.945 1.752 ;
     RECT  19.397 21.84 20.437 21.864 ;
     RECT  19.181 3.936 20.833 4.152 ;
     RECT  20.437 21.84 21.337 22.104 ;
     RECT  21.685 25.776 21.881 25.8 ;
     RECT  21.805 0.096 21.889 0.12 ;
     RECT  20.833 3.408 22.637 4.152 ;
     RECT  21.337 21.84 22.781 22.344 ;
     RECT  23.605 24.48 23.689 24.504 ;
     RECT  23.713 0.096 23.797 0.12 ;
     RECT  22.637 4.08 24.008 4.152 ;
     RECT  18.904 5.232 24.008 5.256 ;
     RECT  18.904 12.336 24.008 13.704 ;
     RECT  18.904 14.736 24.008 16.392 ;
     RECT  22.781 21.84 24.008 22.248 ;
     RECT  24.008 2.148 24.112 23.772 ;
     RECT  24.112 2.418 24.304 23.502 ;
     RECT  24.304 3.984 25.229 4.248 ;
     RECT  25.525 23.904 25.661 23.928 ;
     RECT  25.657 0.096 25.741 0.12 ;
     RECT  25.477 2.784 25.805 2.808 ;
     RECT  25.229 3.984 25.981 4.152 ;
     RECT  26.485 10.8 26.569 10.824 ;
     RECT  24.304 22.224 26.701 22.248 ;
     RECT  25.981 3.024 27.101 4.152 ;
     RECT  26.701 22.224 27.277 22.296 ;
     RECT  27.277 22.128 27.605 22.296 ;
     RECT  27.445 23.904 27.605 23.928 ;
     RECT  27.601 0.096 27.685 0.12 ;
     RECT  27.101 3.408 27.713 4.152 ;
     RECT  27.713 3.792 28.253 4.152 ;
     RECT  28.253 3.888 28.825 4.152 ;
     RECT  24.304 5.232 28.825 5.256 ;
     RECT  27.605 22.272 29.269 22.296 ;
     RECT  28.825 3.888 29.408 5.256 ;
     RECT  24.304 12.336 29.408 16.392 ;
     RECT  29.269 22.272 29.408 22.824 ;
     RECT  29.408 2.148 29.512 23.772 ;
     RECT  29.365 25.776 29.585 25.8 ;
     RECT  29.545 0.096 29.629 0.12 ;
     RECT  29.512 2.418 29.704 23.502 ;
     RECT  29.704 21.408 30.755 22.296 ;
     RECT  29.704 3.12 30.769 5.256 ;
     RECT  29.704 12.336 30.953 16.392 ;
     RECT  31.265 23.904 31.349 23.928 ;
     RECT  30.755 21.936 31.457 21.96 ;
     RECT  31.417 0.096 31.523 0.12 ;
     RECT  30.769 2.88 32.529 5.256 ;
     RECT  32.461 22.464 33.205 22.488 ;
     RECT  33.433 0.096 33.517 0.12 ;
     RECT  32.529 2.88 33.613 3.096 ;
     RECT  32.529 4.128 33.613 5.256 ;
     RECT  33.205 22.464 33.617 23.4 ;
     RECT  34.513 6.576 34.585 6.6 ;
     RECT  33.613 2.88 34.729 5.256 ;
     RECT  34.585 6.576 34.729 6.696 ;
     RECT  34.729 2.88 34.808 6.696 ;
     RECT  30.953 12.336 34.808 13.704 ;
     RECT  30.953 14.736 34.808 16.392 ;
     RECT  33.617 22.464 34.808 22.488 ;
     RECT  34.808 2.148 35.104 23.772 ;
     RECT  35.173 23.904 35.273 23.928 ;
     RECT  35.104 21.648 35.669 22.632 ;
     RECT  35.104 12 35.747 13.704 ;
     RECT  35.669 21.648 35.749 22.248 ;
     RECT  35.365 1.728 35.849 1.752 ;
     RECT  35.104 3.408 36.925 6.696 ;
     RECT  36.925 3.408 36.997 6.792 ;
     RECT  36.997 3.408 37.289 6.84 ;
     RECT  37.093 24.48 37.289 24.504 ;
     RECT  37.249 0.096 37.333 0.12 ;
     RECT  37.289 3.408 37.361 6.792 ;
     RECT  37.361 3.936 37.613 6.792 ;
     RECT  37.613 3.936 37.973 6.264 ;
     RECT  37.973 3.936 38.117 6.168 ;
     RECT  35.749 22.224 38.149 22.248 ;
     RECT  38.149 22.224 38.941 22.488 ;
     RECT  38.117 3.936 38.977 6.12 ;
     RECT  39.013 24.48 39.097 24.504 ;
     RECT  38.977 3.648 39.229 6.12 ;
     RECT  39.229 3.6 39.265 6.12 ;
     RECT  39.193 0.096 39.299 0.12 ;
     RECT  38.941 21.648 39.409 22.488 ;
     RECT  39.265 3.408 39.805 6.12 ;
     RECT  39.805 3.36 40.208 6.12 ;
     RECT  35.747 12.336 40.208 13.704 ;
     RECT  35.104 14.736 40.208 16.392 ;
     RECT  39.409 21.504 40.208 22.488 ;
     RECT  40.208 2.148 40.312 23.772 ;
     RECT  40.312 2.418 40.504 23.772 ;
     RECT  40.504 21.504 40.889 21.672 ;
     RECT  40.913 23.904 40.997 23.928 ;
     RECT  41.165 0.096 41.249 0.12 ;
     RECT  40.504 3.36 42.545 6.12 ;
     RECT  42.821 24.48 42.905 24.504 ;
     RECT  43.081 0.096 43.187 0.12 ;
     RECT  40.889 21.648 43.765 21.672 ;
     RECT  42.545 3.936 44.341 6.12 ;
     RECT  44.765 23.904 44.849 23.928 ;
     RECT  44.989 0.096 45.107 0.12 ;
     RECT  43.765 21.648 45.457 22.2 ;
     RECT  44.341 3.888 45.608 6.12 ;
     RECT  40.504 12.336 45.608 13.704 ;
     RECT  40.504 14.736 45.608 16.392 ;
     RECT  45.457 21.408 45.608 22.2 ;
     RECT  45.608 2.148 45.712 23.772 ;
     RECT  45.712 2.418 45.904 23.502 ;
     RECT  45.904 3.888 45.929 6.12 ;
     RECT  45.904 23.376 46.757 23.4 ;
     RECT  46.933 0.096 47.027 0.12 ;
     RECT  45.929 4.176 47.473 6.12 ;
     RECT  45.904 21.408 47.557 21.432 ;
     RECT  47.516 22.704 47.557 22.728 ;
     RECT  47.557 21.408 47.603 22.728 ;
     RECT  47.473 3.408 48.989 6.12 ;
     RECT  48.613 24.48 48.989 24.504 ;
     RECT  48.949 0.096 49.033 0.12 ;
     RECT  48.989 3.888 49.889 6.12 ;
     RECT  50.821 0.096 50.915 0.12 ;
     RECT  49.889 3.888 51.008 4.2 ;
     RECT  49.889 5.232 51.008 6.12 ;
     RECT  45.904 12.336 51.008 13.704 ;
     RECT  45.904 14.736 51.008 16.392 ;
     RECT  47.603 21.408 51.008 22.008 ;
     RECT  50.533 23.376 51.008 23.4 ;
     RECT  51.008 2.148 51.112 23.772 ;
     RECT  51.112 2.418 51.304 23.502 ;
     RECT  52.453 24.48 52.661 24.504 ;
     RECT  52.765 0.096 52.849 0.12 ;
     RECT  51.304 12.336 53.029 13.704 ;
     RECT  51.304 3.888 53.372 4.2 ;
     RECT  53.372 3.408 53.459 4.2 ;
     RECT  51.304 21.984 53.485 22.008 ;
     RECT  53.485 21.648 53.525 22.008 ;
     RECT  53.459 3.6 53.797 4.2 ;
     RECT  51.304 5.232 53.797 6.12 ;
     RECT  53.893 10.992 53.98 11.016 ;
     RECT  54.421 24.48 54.605 24.504 ;
     RECT  54.709 0.096 54.803 0.12 ;
     RECT  53.525 21.648 55.177 21.672 ;
     RECT  55.177 21.648 55.217 22.056 ;
     RECT  53.797 3.6 56.408 6.12 ;
     RECT  53.029 12 56.408 13.704 ;
     RECT  51.304 14.736 56.408 16.392 ;
     RECT  55.217 22.032 56.408 22.056 ;
     RECT  56.329 24.48 56.408 24.504 ;
     RECT  56.408 2.148 56.413 24.504 ;
     RECT  56.413 2.148 56.512 23.772 ;
     RECT  56.512 2.418 56.704 23.502 ;
     RECT  56.545 0.528 56.723 0.552 ;
     RECT  56.704 21.648 57.089 22.056 ;
     RECT  58.261 24.48 58.457 24.504 ;
     RECT  58.597 0.096 58.691 0.12 ;
     RECT  57.089 21.648 59.077 21.672 ;
     RECT  59.077 21.648 59.123 22.728 ;
     RECT  59.123 21.936 59.164 22.728 ;
     RECT  56.704 4.128 60.073 4.2 ;
     RECT  60.181 23.904 60.401 23.928 ;
     RECT  60.541 0.096 60.625 0.12 ;
     RECT  60.073 3.936 61.045 4.2 ;
     RECT  59.164 21.936 61.153 21.96 ;
     RECT  56.704 5.232 61.237 6.12 ;
     RECT  61.153 21.648 61.405 22.056 ;
     RECT  61.045 3.072 61.808 4.2 ;
     RECT  61.237 5.232 61.808 6.84 ;
     RECT  56.704 12 61.808 13.704 ;
     RECT  56.704 14.736 61.808 16.392 ;
     RECT  61.405 21.648 61.808 22.248 ;
     RECT  61.808 2.148 61.912 23.772 ;
     RECT  61.912 2.418 61.945 23.772 ;
     RECT  61.945 2.418 62.104 23.928 ;
     RECT  62.104 23.904 62.147 23.928 ;
     RECT  62.485 0.096 62.569 0.12 ;
     RECT  62.104 3.072 63.877 3.096 ;
     RECT  62.104 4.176 63.877 6.84 ;
     RECT  62.104 22.032 63.929 22.056 ;
     RECT  63.877 3.072 63.964 6.84 ;
     RECT  64.021 24.48 64.217 24.504 ;
     RECT  64.429 0.096 64.513 0.12 ;
     RECT  62.104 12 65.261 13.704 ;
     RECT  63.964 4.176 65.545 6.84 ;
     RECT  64.933 21.936 65.765 21.96 ;
     RECT  65.545 4.128 65.945 6.84 ;
     RECT  65.725 24.48 65.987 24.504 ;
     RECT  66.373 0.096 66.457 0.12 ;
     RECT  65.261 12.336 67.201 13.704 ;
     RECT  63.964 3.072 67.208 3.096 ;
     RECT  65.945 4.128 67.208 4.2 ;
     RECT  65.945 5.232 67.208 6.84 ;
     RECT  67.201 11.76 67.208 13.704 ;
     RECT  62.104 14.736 67.208 16.392 ;
     RECT  66.661 22.032 67.208 22.056 ;
     RECT  67.208 2.148 67.312 23.772 ;
     RECT  67.312 2.418 67.504 23.502 ;
     RECT  67.861 24.48 67.961 24.504 ;
     RECT  68.245 0.096 68.339 0.12 ;
     RECT  67.504 22.032 68.749 22.056 ;
     RECT  68.749 21.648 68.789 22.056 ;
     RECT  68.789 21.648 69.825 21.96 ;
     RECT  69.74 23.952 69.827 23.976 ;
     RECT  67.504 4.128 69.877 4.2 ;
     RECT  67.504 5.232 69.877 6.84 ;
     RECT  69.877 4.128 69.964 6.84 ;
     RECT  67.504 11.76 70.193 13.704 ;
     RECT  70.261 0.096 70.345 0.12 ;
     RECT  67.504 3.072 70.741 3.096 ;
     RECT  69.964 5.568 70.796 6.84 ;
     RECT  70.741 2.832 70.805 3.096 ;
     RECT  70.193 11.952 71.129 13.704 ;
     RECT  70.796 5.568 71.377 7.224 ;
     RECT  71.377 5.568 71.597 7.416 ;
     RECT  69.964 4.128 71.629 4.2 ;
     RECT  71.701 23.952 71.795 23.976 ;
     RECT  72.133 0.096 72.227 0.12 ;
     RECT  70.805 2.832 72.608 2.856 ;
     RECT  71.629 3.936 72.608 4.2 ;
     RECT  71.597 5.568 72.608 6.696 ;
     RECT  71.129 12.24 72.608 13.704 ;
     RECT  67.504 14.736 72.608 16.392 ;
     RECT  69.825 21.936 72.608 21.96 ;
     RECT  72.608 2.148 72.712 23.772 ;
     RECT  72.712 2.418 72.904 23.502 ;
     RECT  72.904 3.936 73.289 4.2 ;
     RECT  72.904 12.24 73.427 13.704 ;
     RECT  73.637 24.48 73.721 24.504 ;
     RECT  72.904 21.648 73.829 21.672 ;
     RECT  74.077 0.096 74.161 0.12 ;
     RECT  73.289 4.176 74.221 4.2 ;
     RECT  72.904 5.568 74.225 6.84 ;
     RECT  74.225 5.568 74.291 6.504 ;
     RECT  74.221 4.176 74.305 4.536 ;
     RECT  72.904 2.832 74.837 2.856 ;
     RECT  74.305 4.176 75.193 4.2 ;
     RECT  75.337 23.712 75.635 23.736 ;
     RECT  75.193 3.696 75.829 4.2 ;
     RECT  74.291 5.568 75.829 6.12 ;
     RECT  75.589 7.344 75.829 7.368 ;
     RECT  75.829 3.072 75.916 4.536 ;
     RECT  75.829 5.568 75.916 7.368 ;
     RECT  75.841 1.728 76.115 1.752 ;
     RECT  75.916 3.696 76.601 4.536 ;
     RECT  75.916 7.296 76.817 7.368 ;
     RECT  76.601 3.696 76.981 4.248 ;
     RECT  75.697 22.176 77.245 22.2 ;
     RECT  75.916 5.568 77.461 6.168 ;
     RECT  77.281 25.104 77.555 25.128 ;
     RECT  77.245 22.08 77.677 22.2 ;
     RECT  77.785 1.728 78.008 1.752 ;
     RECT  76.981 3.312 78.008 4.248 ;
     RECT  77.461 5.568 78.008 6.312 ;
     RECT  76.817 7.344 78.008 7.368 ;
     RECT  73.427 12.336 78.008 13.704 ;
     RECT  72.904 14.736 78.008 16.392 ;
     RECT  77.677 22.08 78.008 22.248 ;
     RECT  78.008 1.728 78.035 23.772 ;
     RECT  78.035 2.148 78.112 23.772 ;
     RECT  78.112 2.418 78.304 23.502 ;
     RECT  78.304 2.736 78.617 6.312 ;
     RECT  78.617 2.736 79.013 3.336 ;
     RECT  78.617 4.656 79.229 6.312 ;
     RECT  79.189 25.776 79.475 25.8 ;
     RECT  78.304 14.736 79.841 16.44 ;
     RECT  78.304 12.336 79.981 13.704 ;
     RECT  79.841 14.736 79.981 16.392 ;
     RECT  79.229 4.896 80.003 6.312 ;
     RECT  80.003 5.184 80.021 6.312 ;
     RECT  79.945 0.576 80.029 0.6 ;
     RECT  80.021 6.288 80.269 6.312 ;
     RECT  80.269 6.288 80.341 6.792 ;
     RECT  80.341 6.288 80.489 6.84 ;
     RECT  78.304 22.224 80.993 22.248 ;
     RECT  80.489 6.288 81.281 6.792 ;
     RECT  81.133 23.904 81.395 23.928 ;
     RECT  81.673 1.728 81.923 1.752 ;
     RECT  79.919 3.888 82.145 3.912 ;
     RECT  81.281 6.768 82.289 6.792 ;
     RECT  81.457 21.648 82.429 21.672 ;
     RECT  83.005 25.104 83.315 25.128 ;
     RECT  79.013 2.736 83.408 2.76 ;
     RECT  83.257 4.176 83.408 4.2 ;
     RECT  80.021 5.184 83.408 5.208 ;
     RECT  79.981 12.336 83.408 16.392 ;
     RECT  82.429 21.648 83.408 22.248 ;
     RECT  83.408 2.148 83.512 23.772 ;
     RECT  83.512 2.418 83.704 23.502 ;
     RECT  83.797 0.576 83.881 0.6 ;
     RECT  83.704 2.736 84.881 4.2 ;
     RECT  83.704 12.336 85.021 16.392 ;
     RECT  84.949 23.712 85.235 23.736 ;
     RECT  85.561 1.728 85.811 1.752 ;
     RECT  84.881 2.736 85.921 2.76 ;
     RECT  84.881 3.84 85.921 4.2 ;
     RECT  85.021 12.192 86.681 16.392 ;
     RECT  86.893 23.712 87.155 23.736 ;
     RECT  86.681 12.192 87.685 16.344 ;
     RECT  87.433 1.728 87.731 1.752 ;
     RECT  87.397 21.12 88.076 21.144 ;
     RECT  83.704 22.224 88.076 22.248 ;
     RECT  88.076 21.12 88.225 22.248 ;
     RECT  85.921 2.736 88.808 4.2 ;
     RECT  83.704 5.184 88.808 5.208 ;
     RECT  87.685 12.192 88.808 16.536 ;
     RECT  88.261 17.616 88.808 17.64 ;
     RECT  88.225 20.544 88.808 22.248 ;
     RECT  88.808 2.148 88.912 23.772 ;
     RECT  88.912 2.418 89.104 23.502 ;
     RECT  88.765 25.104 89.123 25.128 ;
     RECT  89.593 0.576 89.677 0.6 ;
     RECT  89.104 12.192 90.029 17.64 ;
     RECT  90.029 12.192 90.137 16.632 ;
     RECT  90.137 12.192 90.209 16.584 ;
     RECT  89.104 21.12 90.349 21.768 ;
     RECT  90.209 12.192 90.497 16.536 ;
     RECT  90.781 23.712 91.043 23.736 ;
     RECT  90.349 21.12 91.141 21.816 ;
     RECT  91.141 21.12 91.181 22.44 ;
     RECT  89.104 4.176 91.537 4.2 ;
     RECT  91.537 3.984 91.577 4.2 ;
     RECT  91.321 1.728 91.619 1.752 ;
     RECT  91.181 22.176 92.081 22.44 ;
     RECT  90.497 12.192 92.509 16.392 ;
     RECT  90.029 17.616 92.509 17.64 ;
     RECT  92.509 12.192 92.627 17.64 ;
     RECT  91.577 3.984 92.761 4.008 ;
     RECT  89.104 5.184 92.761 5.208 ;
     RECT  92.761 3.984 92.801 5.208 ;
     RECT  92.689 25.776 92.963 25.8 ;
     RECT  92.081 22.176 93.053 22.2 ;
     RECT  93.481 0.576 93.565 0.6 ;
     RECT  91.181 21.12 93.985 21.144 ;
     RECT  89.104 2.736 94.208 2.76 ;
     RECT  92.801 4.464 94.208 5.208 ;
     RECT  92.627 12.192 94.208 16.392 ;
     RECT  93.985 21.12 94.208 21.816 ;
     RECT  94.208 2.148 94.504 23.772 ;
     RECT  94.633 23.904 94.883 23.928 ;
     RECT  95.209 1.728 95.507 1.752 ;
     RECT  94.504 4.368 95.749 5.208 ;
     RECT  94.504 12.192 95.852 16.488 ;
     RECT  94.504 21.12 95.939 22.488 ;
     RECT  95.749 3.936 96.035 5.208 ;
     RECT  94.504 2.736 96.133 2.76 ;
     RECT  96.035 3.936 96.133 4.392 ;
     RECT  96.133 2.736 96.179 4.392 ;
     RECT  95.852 12.192 96.217 17.304 ;
     RECT  96.179 2.736 96.437 3.816 ;
     RECT  96.505 23.712 96.803 23.736 ;
     RECT  97.153 1.728 97.427 1.752 ;
     RECT  96.217 12.192 97.477 17.64 ;
     RECT  97.477 12.192 97.625 18.264 ;
     RECT  95.939 21.792 97.981 22.488 ;
     RECT  97.625 12.192 98.012 17.4 ;
     RECT  98.012 11.664 98.099 17.4 ;
     RECT  98.099 12.192 98.147 17.4 ;
     RECT  98.449 25.104 98.723 25.128 ;
     RECT  99.169 0.576 99.347 0.6 ;
     RECT  98.147 12.864 99.457 17.4 ;
     RECT  96.437 2.736 99.608 3.432 ;
     RECT  99.457 12.528 99.608 17.4 ;
     RECT  97.981 21.744 99.608 22.488 ;
     RECT  99.608 2.148 99.712 23.772 ;
     RECT  99.712 2.418 99.904 23.772 ;
     RECT  100.357 23.904 100.643 23.928 ;
     RECT  99.904 21.744 100.649 22.488 ;
     RECT  99.904 12.432 100.933 16.296 ;
     RECT  99.904 17.376 100.933 17.4 ;
     RECT  100.925 18.816 100.933 18.84 ;
     RECT  100.933 12.432 100.979 18.84 ;
     RECT  100.979 18.096 101.009 18.84 ;
     RECT  101.041 1.728 101.315 1.752 ;
     RECT  100.979 12.432 101.549 17.064 ;
     RECT  100.649 22.464 101.708 22.488 ;
     RECT  101.708 21.84 101.795 22.488 ;
     RECT  101.549 12.816 102.524 17.064 ;
     RECT  102.301 23.904 102.563 23.928 ;
     RECT  102.524 12.384 102.611 17.064 ;
     RECT  101.795 22.464 102.629 22.488 ;
     RECT  102.611 12.816 102.841 17.064 ;
     RECT  101.009 18.096 102.841 18.12 ;
     RECT  102.841 12.816 102.881 18.12 ;
     RECT  102.517 9.696 103.205 9.72 ;
     RECT  103.165 0.576 103.249 0.6 ;
     RECT  102.881 12.816 103.565 18.024 ;
     RECT  103.565 12.816 103.673 16.296 ;
     RECT  103.673 12.816 103.745 16.248 ;
     RECT  103.565 17.472 103.925 18.024 ;
     RECT  103.745 12.816 104.245 16.104 ;
     RECT  104.173 25.104 104.483 25.128 ;
     RECT  102.301 20.064 104.485 20.088 ;
     RECT  103.597 22.224 104.497 22.248 ;
     RECT  104.245 12.528 104.857 16.104 ;
     RECT  104.893 1.728 105.008 1.752 ;
     RECT  99.904 2.736 105.008 3.432 ;
     RECT  101.941 11.328 105.008 11.352 ;
     RECT  104.857 12.528 105.008 16.344 ;
     RECT  103.925 17.472 105.008 17.496 ;
     RECT  104.485 19.344 105.008 20.088 ;
     RECT  104.497 21.792 105.008 22.248 ;
     RECT  105.008 1.728 105.112 23.772 ;
     RECT  105.112 1.728 105.155 23.502 ;
     RECT  105.155 2.418 105.304 23.502 ;
     RECT  105.304 2.736 105.443 4.152 ;
     RECT  105.304 21.792 105.581 22.248 ;
     RECT  105.304 11.952 105.617 16.344 ;
     RECT  105.617 11.952 105.827 16.104 ;
     RECT  106.117 23.712 106.403 23.736 ;
     RECT  105.827 12.528 106.877 16.104 ;
     RECT  106.837 1.728 107.123 1.752 ;
     RECT  106.877 12.864 107.125 16.104 ;
     RECT  107.125 12.864 107.197 16.392 ;
     RECT  107.197 12.864 107.372 17.016 ;
     RECT  107.372 12.864 107.459 17.496 ;
     RECT  107.459 12.864 107.777 17.016 ;
     RECT  107.777 12.864 108.101 16.392 ;
     RECT  105.443 2.736 108.133 3.432 ;
     RECT  108.101 12.864 108.133 15.48 ;
     RECT  108.133 12.528 108.217 15.48 ;
     RECT  108.061 25.104 108.371 25.128 ;
     RECT  108.217 12.864 108.605 15.48 ;
     RECT  105.581 22.224 108.673 22.248 ;
     RECT  108.997 0.576 109.081 0.6 ;
     RECT  108.133 4.992 109.909 5.016 ;
     RECT  108.133 2.736 110.408 3.96 ;
     RECT  109.909 4.992 110.408 5.496 ;
     RECT  108.605 12.864 110.408 14.952 ;
     RECT  107.413 18.48 110.408 18.504 ;
     RECT  108.673 22.224 110.408 22.488 ;
     RECT  110.005 23.712 110.408 23.736 ;
     RECT  110.408 2.148 110.512 23.772 ;
     RECT  110.512 2.148 110.653 23.502 ;
     RECT  110.653 1.728 110.704 23.502 ;
     RECT  110.704 13.632 110.909 14.472 ;
     RECT  110.704 1.728 110.963 1.752 ;
     RECT  111.949 23.712 112.211 23.736 ;
     RECT  110.909 13.92 112.313 14.472 ;
     RECT  110.704 22.128 112.669 22.488 ;
     RECT  112.885 0.576 112.969 0.6 ;
     RECT  110.704 2.736 113.029 2.76 ;
     RECT  110.704 3.936 113.029 5.496 ;
     RECT  112.669 22.08 113.069 22.488 ;
     RECT  113.069 22.128 113.285 22.488 ;
     RECT  113.857 25.776 114.131 25.8 ;
     RECT  113.285 22.464 114.433 22.488 ;
     RECT  114.685 0.576 114.851 0.6 ;
     RECT  113.029 2.736 115.808 5.496 ;
     RECT  112.313 13.92 115.808 13.944 ;
     RECT  110.704 18.48 115.808 18.504 ;
     RECT  114.433 22.176 115.808 22.488 ;
     RECT  115.808 2.148 115.912 23.772 ;
     RECT  115.513 25.104 116.051 25.128 ;
     RECT  115.912 2.148 116.104 23.502 ;
     RECT  116.104 3.84 116.381 5.496 ;
     RECT  116.557 1.728 116.819 1.752 ;
     RECT  116.104 2.736 117.733 2.76 ;
     RECT  116.381 4.128 117.733 5.496 ;
     RECT  117.421 23.904 117.971 23.928 ;
     RECT  117.733 2.736 118.613 5.496 ;
     RECT  118.681 0.576 118.765 0.6 ;
     RECT  118.613 2.832 118.937 5.496 ;
     RECT  119.617 25.104 119.891 25.128 ;
     RECT  116.104 22.176 120.625 22.488 ;
     RECT  120.373 1.728 120.659 1.752 ;
     RECT  118.937 2.832 121.208 2.856 ;
     RECT  118.937 4.128 121.208 5.496 ;
     RECT  116.104 13.92 121.208 13.944 ;
     RECT  116.104 18.48 121.208 18.504 ;
     RECT  120.625 22.032 121.208 22.488 ;
     RECT  121.208 2.148 121.312 23.772 ;
     RECT  121.312 2.418 121.504 23.736 ;
     RECT  121.504 23.712 121.811 23.736 ;
     RECT  121.504 2.832 122.579 5.496 ;
     RECT  122.569 0.576 122.653 0.6 ;
     RECT  121.504 22.032 122.821 22.488 ;
     RECT  122.579 2.832 123.073 5.208 ;
     RECT  123.073 2.64 123.725 5.208 ;
     RECT  123.505 25.104 123.731 25.128 ;
     RECT  123.725 2.64 124.261 2.664 ;
     RECT  124.261 1.728 124.547 2.664 ;
     RECT  122.821 21.648 124.837 22.488 ;
     RECT  124.547 2.64 125.413 2.664 ;
     RECT  123.725 3.888 125.413 5.208 ;
     RECT  125.413 2.64 125.459 5.208 ;
     RECT  125.305 25.776 125.699 25.8 ;
     RECT  125.459 2.64 126.205 3.432 ;
     RECT  126.205 1.728 126.467 3.432 ;
     RECT  126.467 2.148 126.529 3.432 ;
     RECT  126.529 2.148 126.608 3.72 ;
     RECT  125.459 4.896 126.608 5.208 ;
     RECT  121.504 13.92 126.608 13.944 ;
     RECT  121.504 18.48 126.608 18.504 ;
     RECT  124.837 21.648 126.608 22.728 ;
     RECT  126.608 2.148 126.712 23.772 ;
     RECT  126.712 2.418 126.904 23.772 ;
     RECT  126.904 3.696 127.577 5.208 ;
     RECT  127.357 23.904 127.619 23.928 ;
     RECT  126.904 21.984 127.721 22.488 ;
     RECT  128.365 0.576 128.449 0.6 ;
     RECT  126.904 2.64 129.445 2.664 ;
     RECT  127.577 3.936 129.445 5.208 ;
     RECT  129.229 25.104 129.539 25.128 ;
     RECT  127.721 22.176 129.697 22.488 ;
     RECT  129.445 2.64 130.093 5.208 ;
     RECT  130.093 1.728 130.355 5.208 ;
     RECT  130.355 2.64 132.008 5.208 ;
     RECT  126.904 13.92 132.008 13.944 ;
     RECT  126.904 18.48 132.008 18.504 ;
     RECT  129.697 21.696 132.008 22.488 ;
     RECT  131.173 23.712 132.008 23.736 ;
     RECT  132.008 2.148 132.112 23.772 ;
     RECT  132.112 2.418 132.304 23.772 ;
     RECT  132.253 0.576 132.337 0.6 ;
     RECT  132.304 2.64 133.285 2.664 ;
     RECT  132.304 4.128 133.285 5.208 ;
     RECT  132.973 23.904 133.379 23.928 ;
     RECT  133.285 2.64 133.981 5.208 ;
     RECT  133.981 1.728 134.003 5.208 ;
     RECT  132.304 22.224 134.129 22.488 ;
     RECT  134.003 1.728 134.243 3.48 ;
     RECT  134.243 2.64 135.097 3.48 ;
     RECT  134.129 22.464 135.164 22.488 ;
     RECT  135.164 22.416 135.169 22.488 ;
     RECT  132.304 18.48 135.205 18.504 ;
     RECT  135.169 22.416 135.251 22.776 ;
     RECT  135.097 2.64 135.277 3.912 ;
     RECT  134.003 4.896 135.277 5.208 ;
     RECT  135.251 22.464 135.281 22.776 ;
     RECT  135.025 25.776 135.299 25.8 ;
     RECT  135.277 2.64 135.317 5.208 ;
     RECT  135.317 2.64 135.889 2.664 ;
     RECT  135.889 1.728 136.163 2.664 ;
     RECT  135.317 3.888 136.253 5.208 ;
     RECT  136.969 23.904 137.219 23.928 ;
     RECT  136.163 2.64 137.221 2.664 ;
     RECT  136.253 3.888 137.221 3.912 ;
     RECT  135.281 22.752 137.293 22.776 ;
     RECT  137.221 2.64 137.408 3.912 ;
     RECT  136.253 4.896 137.408 5.208 ;
     RECT  132.304 13.92 137.408 13.944 ;
     RECT  135.205 18.432 137.408 18.504 ;
     RECT  137.293 22.512 137.408 22.776 ;
     RECT  137.408 2.148 137.512 23.772 ;
     RECT  137.512 2.418 137.704 23.502 ;
     RECT  137.704 2.64 138.035 3.912 ;
     RECT  138.013 0.576 138.131 0.6 ;
     RECT  137.704 18.432 138.757 18.504 ;
     RECT  138.757 18.432 139.061 18.792 ;
     RECT  138.035 2.64 139.129 3.672 ;
     RECT  137.704 4.896 139.129 5.208 ;
     RECT  139.052 23.712 139.139 23.736 ;
     RECT  139.129 2.64 139.169 5.208 ;
     RECT  137.704 21.648 139.277 22.536 ;
     RECT  139.169 2.64 139.777 2.664 ;
     RECT  139.777 1.728 140.051 2.664 ;
     RECT  140.051 2.64 140.725 2.664 ;
     RECT  139.169 3.648 140.725 5.208 ;
     RECT  139.277 22.512 140.825 22.536 ;
     RECT  140.785 23.712 141.059 23.736 ;
     RECT  140.725 2.64 141.113 5.208 ;
     RECT  141.893 0.576 141.977 0.6 ;
     RECT  141.113 4.896 142.081 5.208 ;
     RECT  141.289 22.128 142.225 22.152 ;
     RECT  137.704 13.92 142.621 13.944 ;
     RECT  141.113 2.64 142.808 3.624 ;
     RECT  142.081 4.656 142.808 5.208 ;
     RECT  142.621 13.056 142.808 13.944 ;
     RECT  139.061 18.768 142.808 18.792 ;
     RECT  142.225 21.936 142.808 22.152 ;
     RECT  142.808 2.148 142.94 23.772 ;
     RECT  142.94 2.148 143.027 23.88 ;
     RECT  143.027 2.148 143.104 23.502 ;
     RECT  143.104 2.148 143.665 2.664 ;
     RECT  143.665 1.728 143.939 2.664 ;
     RECT  143.104 7.872 143.939 9.528 ;
     RECT  143.104 17.088 143.939 17.112 ;
     RECT  143.104 21.936 144.241 21.96 ;
     RECT  144.169 15.984 144.253 16.008 ;
     RECT  143.104 3.888 144.421 5.64 ;
     RECT  143.104 13.056 144.421 13.944 ;
     RECT  144.181 14.928 144.421 14.952 ;
     RECT  143.104 6.672 144.461 6.696 ;
     RECT  144.421 13.056 144.467 14.952 ;
     RECT  143.939 2.64 144.524 2.664 ;
     RECT  144.421 3.744 144.524 5.64 ;
     RECT  144.467 13.92 144.525 14.952 ;
     RECT  144.781 23.712 144.947 23.736 ;
     RECT  144.524 2.64 145.109 5.64 ;
     RECT  144.241 21.12 145.213 21.96 ;
     RECT  145.213 21.12 145.253 22.248 ;
     RECT  143.104 18.768 145.285 18.792 ;
     RECT  145.285 18.768 145.381 19.368 ;
     RECT  145.253 21.12 145.381 21.144 ;
     RECT  145.381 18.768 145.427 21.144 ;
     RECT  145.427 18.768 145.429 18.888 ;
     RECT  144.925 11.424 145.436 11.448 ;
     RECT  145.427 20.16 145.468 21.144 ;
     RECT  145.429 18 145.475 18.888 ;
     RECT  145.436 10.56 145.523 11.448 ;
     RECT  145.475 18 145.577 18.024 ;
     RECT  145.109 2.64 145.609 3.768 ;
     RECT  143.939 8.016 145.649 9.528 ;
     RECT  145.109 4.896 145.793 5.64 ;
     RECT  145.609 1.728 145.859 3.768 ;
     RECT  145.859 2.64 146.293 3.768 ;
     RECT  145.649 9.024 146.405 9.528 ;
     RECT  145.649 8.016 146.473 8.04 ;
     RECT  145.793 4.896 146.513 5.016 ;
     RECT  144.525 13.92 146.513 14.232 ;
     RECT  146.473 7.968 146.621 8.04 ;
     RECT  144.565 6.72 146.725 6.744 ;
     RECT  145.468 21.12 146.837 21.144 ;
     RECT  146.581 23.904 146.867 23.928 ;
     RECT  146.725 6.72 146.909 6.84 ;
     RECT  145.253 22.224 146.909 22.248 ;
     RECT  146.293 2.64 147.445 3.912 ;
     RECT  147.625 0.576 147.779 0.6 ;
     RECT  147.445 2.64 147.805 3.96 ;
     RECT  146.513 4.944 147.805 5.016 ;
     RECT  147.805 2.64 148.208 5.016 ;
     RECT  146.909 6.816 148.208 6.84 ;
     RECT  146.621 7.968 148.208 7.992 ;
     RECT  146.405 9.024 148.208 9.048 ;
     RECT  146.905 11.952 148.208 11.976 ;
     RECT  146.513 13.92 148.208 13.944 ;
     RECT  147.589 23.28 148.208 23.304 ;
     RECT  148.208 2.148 148.312 23.772 ;
     RECT  148.312 2.418 148.504 23.502 ;
     RECT  148.504 4.464 148.565 5.016 ;
     RECT  148.504 23.376 148.787 23.4 ;
     RECT  148.565 4.512 148.817 5.016 ;
     RECT  148.504 6.72 148.817 6.84 ;
     RECT  148.504 7.968 148.817 7.992 ;
     RECT  148.504 11.952 148.817 11.976 ;
     RECT  148.817 4.608 148.925 5.016 ;
     RECT  149.66 2.256 149.747 2.28 ;
    LAYER M5 ;
     RECT  2.4 2.137 2.52 2.151 ;
     RECT  7.8 2.137 7.92 2.151 ;
     RECT  13.2 2.137 13.32 2.151 ;
     RECT  18.6 2.137 18.72 2.151 ;
     RECT  24 2.137 24.12 2.151 ;
     RECT  29.4 2.137 29.52 2.151 ;
     RECT  40.2 2.137 40.32 2.151 ;
     RECT  45.6 2.137 45.72 2.151 ;
     RECT  51 2.137 51.12 2.151 ;
     RECT  56.4 2.137 56.52 2.151 ;
     RECT  61.8 2.137 61.92 2.151 ;
     RECT  67.2 2.137 67.32 2.151 ;
     RECT  72.6 2.137 72.72 2.151 ;
     RECT  78 2.137 78.12 2.151 ;
     RECT  83.4 2.137 83.52 2.151 ;
     RECT  88.8 2.137 88.92 2.151 ;
     RECT  94.2 2.137 94.32 2.151 ;
     RECT  99.6 2.137 99.72 2.151 ;
     RECT  105 2.137 105.144 2.151 ;
     RECT  121.2 2.137 121.32 2.151 ;
     RECT  126.6 2.137 126.72 2.151 ;
     RECT  132 2.137 132.12 2.151 ;
     RECT  137.4 2.137 137.52 2.151 ;
     RECT  142.8 2.137 142.92 2.151 ;
     RECT  148.2 2.137 148.32 2.151 ;
     RECT  61.8 2.151 62.112 3.061 ;
     RECT  70.752 2.821 70.776 3.107 ;
     RECT  88.8 2.151 89.112 3.301 ;
     RECT  137.4 2.151 137.712 3.349 ;
     RECT  34.8 2.137 35.112 3.397 ;
     RECT  105 2.151 105.312 3.397 ;
     RECT  121.2 2.151 121.512 3.397 ;
     RECT  133.968 3.349 133.992 3.397 ;
     RECT  144.576 2.821 144.6 3.443 ;
     RECT  53.424 3.397 53.448 3.589 ;
     RECT  13.2 2.151 13.512 3.685 ;
     RECT  32.448 3.061 32.472 3.875 ;
     RECT  63.888 3.061 63.912 3.875 ;
     RECT  137.4 3.349 138.024 3.923 ;
     RECT  96.144 3.301 96.168 3.925 ;
     RECT  13.2 3.685 13.656 4.115 ;
     RECT  61.056 3.061 62.112 4.115 ;
     RECT  76.992 3.301 77.016 4.115 ;
     RECT  113.04 3.685 113.064 4.115 ;
     RECT  125.424 3.397 125.448 4.115 ;
     RECT  129.456 3.445 129.48 4.115 ;
     RECT  13.2 4.115 13.512 4.117 ;
     RECT  34.8 3.397 35.448 4.117 ;
     RECT  105 3.397 105.432 4.163 ;
     RECT  117.744 3.397 117.768 4.163 ;
     RECT  121.2 3.397 121.656 4.163 ;
     RECT  133.296 3.397 133.992 4.163 ;
     RECT  140.736 3.397 140.76 4.163 ;
     RECT  144.624 3.589 144.648 4.163 ;
     RECT  88.128 3.301 89.112 4.165 ;
     RECT  133.968 4.163 133.992 4.211 ;
     RECT  95.76 3.925 96.168 4.403 ;
     RECT  7.8 2.151 8.112 4.405 ;
     RECT  47.856 3.397 47.88 4.499 ;
     RECT  78 2.151 78.312 4.645 ;
     RECT  53.424 3.589 53.832 4.691 ;
     RECT  69.888 4.117 69.912 5.027 ;
     RECT  95.76 4.403 96.024 5.219 ;
     RECT  78 4.645 78.408 5.315 ;
     RECT  110.4 2.137 110.712 5.461 ;
     RECT  122.544 4.261 122.568 5.507 ;
     RECT  142.8 2.151 143.112 5.605 ;
     RECT  6.624 3.541 6.648 5.747 ;
     RECT  7.8 4.405 8.328 5.891 ;
     RECT  79.968 3.877 79.992 6.323 ;
     RECT  74.256 4.501 74.28 6.515 ;
     RECT  61.8 4.115 62.112 6.805 ;
     RECT  75.84 3.061 75.864 7.331 ;
     RECT  76.944 6.133 76.968 7.379 ;
     RECT  3.984 7.381 4.008 8.435 ;
     RECT  142.8 5.605 143.928 9.539 ;
     RECT  4.704 9.349 4.728 10.787 ;
     RECT  6.288 9.637 6.312 10.883 ;
     RECT  53.424 4.691 53.448 10.981 ;
     RECT  12.384 4.117 13.512 11.365 ;
     RECT  7.8 5.891 8.112 11.413 ;
     RECT  145.488 9.493 145.512 11.459 ;
     RECT  12.24 11.365 13.512 11.941 ;
     RECT  105 4.163 105.312 11.941 ;
     RECT  70.848 7.189 70.872 11.987 ;
     RECT  34.8 4.117 35.592 11.989 ;
     RECT  53.424 10.981 53.928 11.989 ;
     RECT  98.064 11.653 98.088 12.181 ;
     RECT  72.6 2.151 72.912 12.229 ;
     RECT  72.6 12.229 73.416 12.371 ;
     RECT  7.68 11.413 8.112 12.515 ;
     RECT  12.24 11.941 14.232 12.515 ;
     RECT  53.04 11.989 53.928 12.515 ;
     RECT  53.904 12.515 53.928 12.517 ;
     RECT  53.904 12.517 54.888 12.563 ;
     RECT  105 11.941 105.816 12.563 ;
     RECT  108.144 4.981 108.168 12.563 ;
     RECT  26.496 10.789 26.52 12.755 ;
     RECT  63.648 11.989 63.672 12.755 ;
     RECT  99.6 2.151 99.912 12.853 ;
     RECT  98.064 12.181 98.136 12.899 ;
     RECT  102.576 12.373 102.6 12.899 ;
     RECT  96 5.219 96.024 12.901 ;
     RECT  61.248 6.805 62.112 12.947 ;
     RECT  96 12.901 96.648 12.949 ;
     RECT  99.504 12.853 99.912 12.995 ;
     RECT  2.4 2.151 2.712 13.045 ;
     RECT  54.864 12.563 54.888 13.523 ;
     RECT  98.112 12.899 98.136 13.523 ;
     RECT  109.92 5.461 110.712 13.765 ;
     RECT  95.904 12.949 96.648 14.099 ;
     RECT  14.688 13.573 14.712 14.339 ;
     RECT  106.56 14.197 106.584 14.867 ;
     RECT  94.2 2.151 94.512 14.917 ;
     RECT  144.432 13.045 144.456 14.917 ;
     RECT  144.192 14.917 144.456 14.963 ;
     RECT  88.032 4.165 89.112 15.011 ;
     RECT  91.536 13.621 91.56 15.155 ;
     RECT  100.896 12.805 100.92 15.203 ;
     RECT  7.8 12.515 8.112 15.301 ;
     RECT  88.176 15.011 89.112 15.443 ;
     RECT  93.456 14.917 94.512 15.443 ;
     RECT  7.008 15.301 8.112 15.491 ;
     RECT  99.6 12.995 99.912 15.493 ;
     RECT  99.504 15.493 99.912 15.635 ;
     RECT  144.192 14.963 144.216 16.019 ;
     RECT  103.392 16.021 103.416 16.403 ;
     RECT  95.904 14.099 95.928 16.453 ;
     RECT  7.8 15.491 8.112 17.077 ;
     RECT  142.8 9.539 143.112 17.077 ;
     RECT  92.592 17.029 92.616 17.651 ;
     RECT  95.904 16.453 96.312 17.651 ;
     RECT  97.488 17.317 97.512 18.275 ;
     RECT  7.152 17.077 8.112 18.419 ;
     RECT  107.424 16.501 107.448 18.515 ;
     RECT  142.8 17.077 143.928 18.803 ;
     RECT  100.944 16.981 100.968 18.851 ;
     RECT  145.44 17.989 145.464 18.899 ;
     RECT  105 12.563 105.312 19.333 ;
     RECT  4.224 18.757 4.248 19.909 ;
     RECT  104.496 19.333 105.312 20.099 ;
     RECT  6.24 19.909 6.264 20.437 ;
     RECT  7.8 18.419 8.112 20.437 ;
     RECT  4.224 19.909 4.584 20.531 ;
     RECT  88.272 15.443 89.112 20.579 ;
     RECT  6.24 20.437 8.112 20.725 ;
     RECT  4.224 20.531 4.248 21.155 ;
     RECT  95.904 17.651 95.928 21.155 ;
     RECT  145.392 19.333 145.416 21.155 ;
     RECT  88.8 20.579 89.112 21.637 ;
     RECT  126.6 2.151 126.912 21.637 ;
     RECT  6.24 20.725 8.52 21.683 ;
     RECT  34.8 11.989 35.736 21.683 ;
     RECT  49.488 21.397 49.512 21.683 ;
     RECT  138.768 18.469 138.792 21.683 ;
     RECT  7.8 21.683 8.52 21.779 ;
     RECT  69.744 21.637 69.768 21.971 ;
     RECT  12.24 12.515 13.512 22.117 ;
     RECT  6.24 21.683 6.264 22.211 ;
     RECT  12.096 22.117 13.512 22.211 ;
     RECT  61.44 12.947 62.112 22.259 ;
     RECT  88.128 21.637 89.112 22.259 ;
     RECT  29.4 2.151 29.712 22.261 ;
     RECT  30.72 21.397 30.744 22.307 ;
     RECT  135.216 18.421 135.24 22.451 ;
     RECT  101.76 21.829 101.784 22.499 ;
     RECT  109.584 13.765 110.712 22.499 ;
     RECT  47.568 21.973 47.592 22.739 ;
     RECT  59.088 21.637 59.112 22.739 ;
     RECT  125.952 21.637 126.912 22.739 ;
     RECT  29.28 22.261 29.712 22.835 ;
     RECT  7.8 21.779 8.328 22.883 ;
     RECT  12.096 22.211 12.12 22.883 ;
     RECT  45.6 2.151 45.912 23.365 ;
     RECT  51 2.151 51.312 23.365 ;
     RECT  148.2 2.151 148.512 23.365 ;
     RECT  110.4 22.499 110.712 23.701 ;
     RECT  121.2 4.163 121.512 23.701 ;
     RECT  132 2.151 132.312 23.701 ;
     RECT  1.488 13.045 2.712 23.769 ;
     RECT  7.8 22.883 8.112 23.769 ;
     RECT  13.2 22.211 13.512 23.769 ;
     RECT  18.6 2.151 18.912 23.769 ;
     RECT  24 2.151 24.312 23.769 ;
     RECT  29.4 22.835 29.712 23.769 ;
     RECT  45.6 23.365 46.728 23.769 ;
     RECT  50.544 23.365 51.312 23.769 ;
     RECT  56.4 2.151 56.712 23.769 ;
     RECT  78 5.315 78.312 23.769 ;
     RECT  83.4 2.151 83.712 23.769 ;
     RECT  88.8 22.259 89.112 23.769 ;
     RECT  105 20.099 105.312 23.769 ;
     RECT  110.256 23.701 110.712 23.769 ;
     RECT  115.8 2.137 116.112 23.769 ;
     RECT  131.424 23.701 132.312 23.769 ;
     RECT  137.4 3.923 137.712 23.769 ;
     RECT  142.8 18.803 143.112 23.769 ;
     RECT  1.488 23.769 2.52 23.783 ;
     RECT  7.8 23.769 7.92 23.783 ;
     RECT  13.2 23.769 13.32 23.783 ;
     RECT  18.6 23.769 18.72 23.783 ;
     RECT  24 23.769 24.12 23.783 ;
     RECT  29.4 23.769 29.52 23.783 ;
     RECT  34.8 21.683 35.112 23.783 ;
     RECT  40.2 2.151 40.512 23.783 ;
     RECT  45.6 23.769 45.72 23.783 ;
     RECT  50.544 23.769 51.12 23.783 ;
     RECT  56.4 23.769 56.52 23.783 ;
     RECT  61.8 22.259 62.112 23.783 ;
     RECT  67.2 2.151 67.512 23.783 ;
     RECT  72.6 12.371 72.912 23.783 ;
     RECT  78 23.769 78.12 23.783 ;
     RECT  83.4 23.769 83.52 23.783 ;
     RECT  88.8 23.769 88.92 23.783 ;
     RECT  94.2 15.443 94.512 23.783 ;
     RECT  99.6 15.635 99.912 23.783 ;
     RECT  105 23.769 105.12 23.783 ;
     RECT  110.256 23.769 110.52 23.783 ;
     RECT  115.8 23.769 115.92 23.783 ;
     RECT  121.2 23.701 121.8 23.783 ;
     RECT  126.6 22.739 126.912 23.783 ;
     RECT  131.424 23.769 132.12 23.783 ;
     RECT  137.4 23.769 137.52 23.783 ;
     RECT  142.8 23.769 143.016 23.783 ;
     RECT  148.2 23.365 148.776 23.783 ;
     RECT  143.112 2.821 144.576 3.443 ;
     RECT  75.864 3.301 76.992 4.115 ;
     RECT  77.016 3.301 78 4.115 ;
     RECT  125.448 3.397 126.6 4.115 ;
     RECT  132.312 3.397 133.296 4.163 ;
     RECT  143.112 3.443 144.6 3.589 ;
     RECT  6.648 3.541 7.8 5.747 ;
     RECT  143.112 3.589 144.624 4.163 ;
     RECT  94.512 3.925 95.76 5.219 ;
     RECT  121.512 4.163 121.656 4.261 ;
     RECT  143.112 4.163 143.928 5.605 ;
     RECT  121.512 4.261 122.544 5.507 ;
     RECT  72.912 4.501 74.256 6.515 ;
     RECT  94.512 5.219 96 12.949 ;
     RECT  75.864 6.133 76.944 7.331 ;
     RECT  76.968 6.133 78 7.379 ;
     RECT  2.712 7.381 3.984 8.435 ;
     RECT  6.312 9.637 7.8 10.883 ;
     RECT  7.68 10.883 7.8 11.413 ;
     RECT  98.088 11.653 99.6 12.181 ;
     RECT  98.136 12.181 99.6 12.853 ;
     RECT  13.512 12.515 14.232 13.573 ;
     RECT  54.888 12.517 56.4 13.523 ;
     RECT  99.912 12.805 100.896 15.203 ;
     RECT  98.136 12.853 99.504 12.995 ;
     RECT  98.064 12.899 98.112 12.901 ;
     RECT  96.648 12.901 98.112 13.523 ;
     RECT  94.512 12.949 95.904 21.155 ;
     RECT  98.136 12.995 99.6 13.523 ;
     RECT  143.112 13.045 144.432 14.917 ;
     RECT  13.512 13.573 14.688 14.339 ;
     RECT  105.312 14.197 106.56 14.867 ;
     RECT  143.112 14.917 144.192 16.019 ;
     RECT  143.112 16.019 143.928 17.077 ;
     RECT  99.912 16.981 100.944 18.851 ;
     RECT  96.312 17.317 97.488 17.651 ;
     RECT  143.928 17.989 145.44 18.803 ;
     RECT  137.712 18.469 138.768 21.683 ;
     RECT  2.712 18.757 4.224 21.155 ;
     RECT  145.392 18.803 145.44 18.899 ;
     RECT  145.392 18.899 145.416 19.333 ;
     RECT  88.272 20.579 88.8 21.637 ;
     RECT  29.712 21.397 30.72 22.307 ;
     RECT  49.512 21.397 51 21.683 ;
     RECT  12.12 22.211 13.2 22.883 ;
     RECT  110.256 22.499 110.4 23.701 ;
  END
END qkd_static_kv_landing_row
END LIBRARY
